VERSION 5.8 ;
BUSBITCHARS "[]" ;
DIVIDERCHAR "/" ;
UNITS
    DATABASE MICRONS 1000 ;
END UNITS

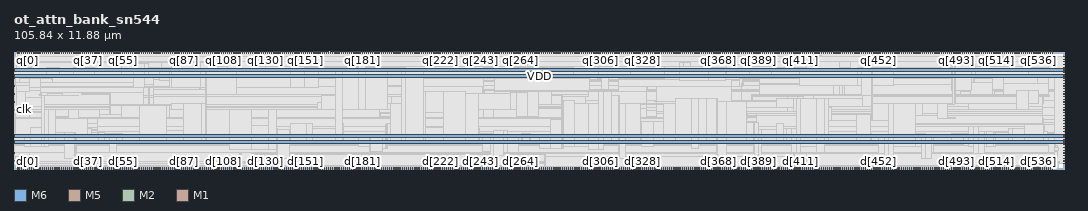
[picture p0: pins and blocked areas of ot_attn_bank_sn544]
MACRO ot_attn_bank_sn544
  FOREIGN ot_attn_bank_sn544 0 0 ;
  CLASS BLOCK ;
  SIZE 105.84 BY 11.88 ;
  PIN clk
    DIRECTION INPUT ;
    USE SIGNAL ;
    PORT
      LAYER M6 ;
        RECT  0 5.952 0.192 5.984 ;
    END
    PORT
      LAYER M6 ;
        RECT  0.144 5.952 0.613 5.984 ;
    END
  END clk
  PIN d[0]
    DIRECTION INPUT ;
    USE SIGNAL ;
    PORT
      LAYER M5 ;
        RECT  0.384 0 0.408 0.192 ;
    END
  END d[0]
  PIN d[100]
    DIRECTION INPUT ;
    USE SIGNAL ;
    PORT
      LAYER M5 ;
        RECT  19.584 0 19.608 0.192 ;
    END
  END d[100]
  PIN d[101]
    DIRECTION INPUT ;
    USE SIGNAL ;
    PORT
      LAYER M5 ;
        RECT  19.776 0 19.8 0.192 ;
    END
  END d[101]
  PIN d[102]
    DIRECTION INPUT ;
    USE SIGNAL ;
    PORT
      LAYER M5 ;
        RECT  19.968 0 19.992 0.192 ;
    END
  END d[102]
  PIN d[103]
    DIRECTION INPUT ;
    USE SIGNAL ;
    PORT
      LAYER M5 ;
        RECT  20.16 0 20.184 0.192 ;
    END
  END d[103]
  PIN d[104]
    DIRECTION INPUT ;
    USE SIGNAL ;
    PORT
      LAYER M5 ;
        RECT  20.352 0 20.376 0.192 ;
    END
  END d[104]
  PIN d[105]
    DIRECTION INPUT ;
    USE SIGNAL ;
    PORT
      LAYER M5 ;
        RECT  20.544 0 20.568 0.192 ;
    END
  END d[105]
  PIN d[106]
    DIRECTION INPUT ;
    USE SIGNAL ;
    PORT
      LAYER M5 ;
        RECT  20.736 0 20.76 0.192 ;
    END
  END d[106]
  PIN d[107]
    DIRECTION INPUT ;
    USE SIGNAL ;
    PORT
      LAYER M5 ;
        RECT  20.928 0 20.952 0.192 ;
    END
  END d[107]
  PIN d[108]
    DIRECTION INPUT ;
    USE SIGNAL ;
    PORT
      LAYER M5 ;
        RECT  21.12 0 21.144 0.192 ;
    END
  END d[108]
  PIN d[109]
    DIRECTION INPUT ;
    USE SIGNAL ;
    PORT
      LAYER M5 ;
        RECT  21.312 0 21.336 0.192 ;
    END
  END d[109]
  PIN d[10]
    DIRECTION INPUT ;
    USE SIGNAL ;
    PORT
      LAYER M5 ;
        RECT  2.304 0 2.328 0.192 ;
    END
  END d[10]
  PIN d[110]
    DIRECTION INPUT ;
    USE SIGNAL ;
    PORT
      LAYER M5 ;
        RECT  21.504 0 21.528 0.192 ;
    END
  END d[110]
  PIN d[111]
    DIRECTION INPUT ;
    USE SIGNAL ;
    PORT
      LAYER M5 ;
        RECT  21.696 0 21.72 0.192 ;
    END
  END d[111]
  PIN d[112]
    DIRECTION INPUT ;
    USE SIGNAL ;
    PORT
      LAYER M5 ;
        RECT  21.888 0 21.912 0.192 ;
    END
  END d[112]
  PIN d[113]
    DIRECTION INPUT ;
    USE SIGNAL ;
    PORT
      LAYER M5 ;
        RECT  22.08 0 22.104 0.192 ;
    END
  END d[113]
  PIN d[114]
    DIRECTION INPUT ;
    USE SIGNAL ;
    PORT
      LAYER M5 ;
        RECT  22.272 0 22.296 0.192 ;
    END
  END d[114]
  PIN d[115]
    DIRECTION INPUT ;
    USE SIGNAL ;
    PORT
      LAYER M5 ;
        RECT  22.464 0 22.488 0.192 ;
    END
  END d[115]
  PIN d[116]
    DIRECTION INPUT ;
    USE SIGNAL ;
    PORT
      LAYER M5 ;
        RECT  22.656 0 22.68 0.192 ;
    END
  END d[116]
  PIN d[117]
    DIRECTION INPUT ;
    USE SIGNAL ;
    PORT
      LAYER M5 ;
        RECT  22.848 0 22.872 0.192 ;
    END
  END d[117]
  PIN d[118]
    DIRECTION INPUT ;
    USE SIGNAL ;
    PORT
      LAYER M5 ;
        RECT  23.04 0 23.064 0.192 ;
    END
  END d[118]
  PIN d[119]
    DIRECTION INPUT ;
    USE SIGNAL ;
    PORT
      LAYER M5 ;
        RECT  23.232 0 23.256 0.192 ;
    END
  END d[119]
  PIN d[11]
    DIRECTION INPUT ;
    USE SIGNAL ;
    PORT
      LAYER M5 ;
        RECT  2.496 0 2.52 0.192 ;
    END
  END d[11]
  PIN d[120]
    DIRECTION INPUT ;
    USE SIGNAL ;
    PORT
      LAYER M5 ;
        RECT  23.424 0 23.448 0.192 ;
    END
  END d[120]
  PIN d[121]
    DIRECTION INPUT ;
    USE SIGNAL ;
    PORT
      LAYER M5 ;
        RECT  23.616 0 23.64 0.192 ;
    END
  END d[121]
  PIN d[122]
    DIRECTION INPUT ;
    USE SIGNAL ;
    PORT
      LAYER M5 ;
        RECT  23.808 0 23.832 0.192 ;
    END
  END d[122]
  PIN d[123]
    DIRECTION INPUT ;
    USE SIGNAL ;
    PORT
      LAYER M5 ;
        RECT  24 0 24.024 0.192 ;
    END
  END d[123]
  PIN d[124]
    DIRECTION INPUT ;
    USE SIGNAL ;
    PORT
      LAYER M5 ;
        RECT  24.192 0 24.216 0.192 ;
    END
  END d[124]
  PIN d[125]
    DIRECTION INPUT ;
    USE SIGNAL ;
    PORT
      LAYER M5 ;
        RECT  24.384 0 24.408 0.192 ;
    END
  END d[125]
  PIN d[126]
    DIRECTION INPUT ;
    USE SIGNAL ;
    PORT
      LAYER M5 ;
        RECT  24.576 0 24.6 0.192 ;
    END
  END d[126]
  PIN d[127]
    DIRECTION INPUT ;
    USE SIGNAL ;
    PORT
      LAYER M5 ;
        RECT  24.768 0 24.792 0.192 ;
    END
  END d[127]
  PIN d[128]
    DIRECTION INPUT ;
    USE SIGNAL ;
    PORT
      LAYER M5 ;
        RECT  24.96 0 24.984 0.192 ;
    END
  END d[128]
  PIN d[129]
    DIRECTION INPUT ;
    USE SIGNAL ;
    PORT
      LAYER M5 ;
        RECT  25.152 0 25.176 0.192 ;
    END
  END d[129]
  PIN d[12]
    DIRECTION INPUT ;
    USE SIGNAL ;
    PORT
      LAYER M5 ;
        RECT  2.688 0 2.712 0.192 ;
    END
  END d[12]
  PIN d[130]
    DIRECTION INPUT ;
    USE SIGNAL ;
    PORT
      LAYER M5 ;
        RECT  25.344 0 25.368 0.192 ;
    END
  END d[130]
  PIN d[131]
    DIRECTION INPUT ;
    USE SIGNAL ;
    PORT
      LAYER M5 ;
        RECT  25.536 0 25.56 0.192 ;
    END
  END d[131]
  PIN d[132]
    DIRECTION INPUT ;
    USE SIGNAL ;
    PORT
      LAYER M5 ;
        RECT  25.728 0 25.752 0.192 ;
    END
  END d[132]
  PIN d[133]
    DIRECTION INPUT ;
    USE SIGNAL ;
    PORT
      LAYER M5 ;
        RECT  25.92 0 25.944 0.192 ;
    END
  END d[133]
  PIN d[134]
    DIRECTION INPUT ;
    USE SIGNAL ;
    PORT
      LAYER M5 ;
        RECT  26.112 0 26.136 0.192 ;
    END
  END d[134]
  PIN d[135]
    DIRECTION INPUT ;
    USE SIGNAL ;
    PORT
      LAYER M5 ;
        RECT  26.304 0 26.328 0.192 ;
    END
  END d[135]
  PIN d[136]
    DIRECTION INPUT ;
    USE SIGNAL ;
    PORT
      LAYER M5 ;
        RECT  26.496 0 26.52 0.192 ;
    END
  END d[136]
  PIN d[137]
    DIRECTION INPUT ;
    USE SIGNAL ;
    PORT
      LAYER M5 ;
        RECT  26.688 0 26.712 0.192 ;
    END
  END d[137]
  PIN d[138]
    DIRECTION INPUT ;
    USE SIGNAL ;
    PORT
      LAYER M5 ;
        RECT  26.88 0 26.904 0.192 ;
    END
  END d[138]
  PIN d[139]
    DIRECTION INPUT ;
    USE SIGNAL ;
    PORT
      LAYER M5 ;
        RECT  27.072 0 27.096 0.192 ;
    END
  END d[139]
  PIN d[13]
    DIRECTION INPUT ;
    USE SIGNAL ;
    PORT
      LAYER M5 ;
        RECT  2.88 0 2.904 0.192 ;
    END
  END d[13]
  PIN d[140]
    DIRECTION INPUT ;
    USE SIGNAL ;
    PORT
      LAYER M5 ;
        RECT  27.264 0 27.288 0.192 ;
    END
  END d[140]
  PIN d[141]
    DIRECTION INPUT ;
    USE SIGNAL ;
    PORT
      LAYER M5 ;
        RECT  27.456 0 27.48 0.192 ;
    END
  END d[141]
  PIN d[142]
    DIRECTION INPUT ;
    USE SIGNAL ;
    PORT
      LAYER M5 ;
        RECT  27.648 0 27.672 0.192 ;
    END
  END d[142]
  PIN d[143]
    DIRECTION INPUT ;
    USE SIGNAL ;
    PORT
      LAYER M5 ;
        RECT  27.84 0 27.864 0.192 ;
    END
  END d[143]
  PIN d[144]
    DIRECTION INPUT ;
    USE SIGNAL ;
    PORT
      LAYER M5 ;
        RECT  28.032 0 28.056 0.192 ;
    END
  END d[144]
  PIN d[145]
    DIRECTION INPUT ;
    USE SIGNAL ;
    PORT
      LAYER M5 ;
        RECT  28.224 0 28.248 0.192 ;
    END
  END d[145]
  PIN d[146]
    DIRECTION INPUT ;
    USE SIGNAL ;
    PORT
      LAYER M5 ;
        RECT  28.416 0 28.44 0.192 ;
    END
  END d[146]
  PIN d[147]
    DIRECTION INPUT ;
    USE SIGNAL ;
    PORT
      LAYER M5 ;
        RECT  28.608 0 28.632 0.192 ;
    END
  END d[147]
  PIN d[148]
    DIRECTION INPUT ;
    USE SIGNAL ;
    PORT
      LAYER M5 ;
        RECT  28.8 0 28.824 0.192 ;
    END
  END d[148]
  PIN d[149]
    DIRECTION INPUT ;
    USE SIGNAL ;
    PORT
      LAYER M5 ;
        RECT  28.992 0 29.016 0.192 ;
    END
  END d[149]
  PIN d[14]
    DIRECTION INPUT ;
    USE SIGNAL ;
    PORT
      LAYER M5 ;
        RECT  3.072 0 3.096 0.192 ;
    END
  END d[14]
  PIN d[150]
    DIRECTION INPUT ;
    USE SIGNAL ;
    PORT
      LAYER M5 ;
        RECT  29.184 0 29.208 0.192 ;
    END
  END d[150]
  PIN d[151]
    DIRECTION INPUT ;
    USE SIGNAL ;
    PORT
      LAYER M5 ;
        RECT  29.376 0 29.4 0.192 ;
    END
  END d[151]
  PIN d[152]
    DIRECTION INPUT ;
    USE SIGNAL ;
    PORT
      LAYER M5 ;
        RECT  29.568 0 29.592 0.192 ;
    END
  END d[152]
  PIN d[153]
    DIRECTION INPUT ;
    USE SIGNAL ;
    PORT
      LAYER M5 ;
        RECT  29.76 0 29.784 0.192 ;
    END
  END d[153]
  PIN d[154]
    DIRECTION INPUT ;
    USE SIGNAL ;
    PORT
      LAYER M5 ;
        RECT  29.952 0 29.976 0.192 ;
    END
  END d[154]
  PIN d[155]
    DIRECTION INPUT ;
    USE SIGNAL ;
    PORT
      LAYER M5 ;
        RECT  30.144 0 30.168 0.192 ;
    END
  END d[155]
  PIN d[156]
    DIRECTION INPUT ;
    USE SIGNAL ;
    PORT
      LAYER M5 ;
        RECT  30.336 0 30.36 0.192 ;
    END
  END d[156]
  PIN d[157]
    DIRECTION INPUT ;
    USE SIGNAL ;
    PORT
      LAYER M5 ;
        RECT  30.528 0 30.552 0.192 ;
    END
  END d[157]
  PIN d[158]
    DIRECTION INPUT ;
    USE SIGNAL ;
    PORT
      LAYER M5 ;
        RECT  30.72 0 30.744 0.192 ;
    END
  END d[158]
  PIN d[159]
    DIRECTION INPUT ;
    USE SIGNAL ;
    PORT
      LAYER M5 ;
        RECT  30.912 0 30.936 0.192 ;
    END
  END d[159]
  PIN d[15]
    DIRECTION INPUT ;
    USE SIGNAL ;
    PORT
      LAYER M5 ;
        RECT  3.264 0 3.288 0.192 ;
    END
  END d[15]
  PIN d[160]
    DIRECTION INPUT ;
    USE SIGNAL ;
    PORT
      LAYER M5 ;
        RECT  31.104 0 31.128 0.192 ;
    END
  END d[160]
  PIN d[161]
    DIRECTION INPUT ;
    USE SIGNAL ;
    PORT
      LAYER M5 ;
        RECT  31.296 0 31.32 0.192 ;
    END
  END d[161]
  PIN d[162]
    DIRECTION INPUT ;
    USE SIGNAL ;
    PORT
      LAYER M5 ;
        RECT  31.488 0 31.512 0.192 ;
    END
  END d[162]
  PIN d[163]
    DIRECTION INPUT ;
    USE SIGNAL ;
    PORT
      LAYER M5 ;
        RECT  31.68 0 31.704 0.192 ;
    END
  END d[163]
  PIN d[164]
    DIRECTION INPUT ;
    USE SIGNAL ;
    PORT
      LAYER M5 ;
        RECT  31.872 0 31.896 0.192 ;
    END
  END d[164]
  PIN d[165]
    DIRECTION INPUT ;
    USE SIGNAL ;
    PORT
      LAYER M5 ;
        RECT  32.064 0 32.088 0.192 ;
    END
  END d[165]
  PIN d[166]
    DIRECTION INPUT ;
    USE SIGNAL ;
    PORT
      LAYER M5 ;
        RECT  32.256 0 32.28 0.192 ;
    END
  END d[166]
  PIN d[167]
    DIRECTION INPUT ;
    USE SIGNAL ;
    PORT
      LAYER M5 ;
        RECT  32.448 0 32.472 0.192 ;
    END
  END d[167]
  PIN d[168]
    DIRECTION INPUT ;
    USE SIGNAL ;
    PORT
      LAYER M5 ;
        RECT  32.64 0 32.664 0.192 ;
    END
  END d[168]
  PIN d[169]
    DIRECTION INPUT ;
    USE SIGNAL ;
    PORT
      LAYER M5 ;
        RECT  32.832 0 32.856 0.192 ;
    END
  END d[169]
  PIN d[16]
    DIRECTION INPUT ;
    USE SIGNAL ;
    PORT
      LAYER M5 ;
        RECT  3.456 0 3.48 0.192 ;
    END
  END d[16]
  PIN d[170]
    DIRECTION INPUT ;
    USE SIGNAL ;
    PORT
      LAYER M5 ;
        RECT  33.024 0 33.048 0.192 ;
    END
  END d[170]
  PIN d[171]
    DIRECTION INPUT ;
    USE SIGNAL ;
    PORT
      LAYER M5 ;
        RECT  33.216 0 33.24 0.192 ;
    END
  END d[171]
  PIN d[172]
    DIRECTION INPUT ;
    USE SIGNAL ;
    PORT
      LAYER M5 ;
        RECT  33.408 0 33.432 0.192 ;
    END
  END d[172]
  PIN d[173]
    DIRECTION INPUT ;
    USE SIGNAL ;
    PORT
      LAYER M5 ;
        RECT  33.6 0 33.624 0.192 ;
    END
  END d[173]
  PIN d[174]
    DIRECTION INPUT ;
    USE SIGNAL ;
    PORT
      LAYER M5 ;
        RECT  33.792 0 33.816 0.192 ;
    END
  END d[174]
  PIN d[175]
    DIRECTION INPUT ;
    USE SIGNAL ;
    PORT
      LAYER M5 ;
        RECT  33.984 0 34.008 0.192 ;
    END
  END d[175]
  PIN d[176]
    DIRECTION INPUT ;
    USE SIGNAL ;
    PORT
      LAYER M5 ;
        RECT  34.176 0 34.2 0.192 ;
    END
  END d[176]
  PIN d[177]
    DIRECTION INPUT ;
    USE SIGNAL ;
    PORT
      LAYER M5 ;
        RECT  34.368 0 34.392 0.192 ;
    END
  END d[177]
  PIN d[178]
    DIRECTION INPUT ;
    USE SIGNAL ;
    PORT
      LAYER M5 ;
        RECT  34.56 0 34.584 0.192 ;
    END
  END d[178]
  PIN d[179]
    DIRECTION INPUT ;
    USE SIGNAL ;
    PORT
      LAYER M5 ;
        RECT  34.752 0 34.776 0.192 ;
    END
  END d[179]
  PIN d[17]
    DIRECTION INPUT ;
    USE SIGNAL ;
    PORT
      LAYER M5 ;
        RECT  3.648 0 3.672 0.192 ;
    END
  END d[17]
  PIN d[180]
    DIRECTION INPUT ;
    USE SIGNAL ;
    PORT
      LAYER M5 ;
        RECT  34.944 0 34.968 0.192 ;
    END
  END d[180]
  PIN d[181]
    DIRECTION INPUT ;
    USE SIGNAL ;
    PORT
      LAYER M5 ;
        RECT  35.136 0 35.16 0.192 ;
    END
  END d[181]
  PIN d[182]
    DIRECTION INPUT ;
    USE SIGNAL ;
    PORT
      LAYER M5 ;
        RECT  35.328 0 35.352 0.192 ;
    END
  END d[182]
  PIN d[183]
    DIRECTION INPUT ;
    USE SIGNAL ;
    PORT
      LAYER M5 ;
        RECT  35.52 0 35.544 0.192 ;
    END
  END d[183]
  PIN d[184]
    DIRECTION INPUT ;
    USE SIGNAL ;
    PORT
      LAYER M5 ;
        RECT  35.712 0 35.736 0.192 ;
    END
  END d[184]
  PIN d[185]
    DIRECTION INPUT ;
    USE SIGNAL ;
    PORT
      LAYER M5 ;
        RECT  35.904 0 35.928 0.192 ;
    END
  END d[185]
  PIN d[186]
    DIRECTION INPUT ;
    USE SIGNAL ;
    PORT
      LAYER M5 ;
        RECT  36.096 0 36.12 0.192 ;
    END
  END d[186]
  PIN d[187]
    DIRECTION INPUT ;
    USE SIGNAL ;
    PORT
      LAYER M5 ;
        RECT  36.288 0 36.312 0.192 ;
    END
  END d[187]
  PIN d[188]
    DIRECTION INPUT ;
    USE SIGNAL ;
    PORT
      LAYER M5 ;
        RECT  36.48 0 36.504 0.192 ;
    END
  END d[188]
  PIN d[189]
    DIRECTION INPUT ;
    USE SIGNAL ;
    PORT
      LAYER M5 ;
        RECT  36.672 0 36.696 0.192 ;
    END
  END d[189]
  PIN d[18]
    DIRECTION INPUT ;
    USE SIGNAL ;
    PORT
      LAYER M5 ;
        RECT  3.84 0 3.864 0.192 ;
    END
  END d[18]
  PIN d[190]
    DIRECTION INPUT ;
    USE SIGNAL ;
    PORT
      LAYER M5 ;
        RECT  36.864 0 36.888 0.192 ;
    END
  END d[190]
  PIN d[191]
    DIRECTION INPUT ;
    USE SIGNAL ;
    PORT
      LAYER M5 ;
        RECT  37.056 0 37.08 0.192 ;
    END
  END d[191]
  PIN d[192]
    DIRECTION INPUT ;
    USE SIGNAL ;
    PORT
      LAYER M5 ;
        RECT  37.248 0 37.272 0.192 ;
    END
  END d[192]
  PIN d[193]
    DIRECTION INPUT ;
    USE SIGNAL ;
    PORT
      LAYER M5 ;
        RECT  37.44 0 37.464 0.192 ;
    END
  END d[193]
  PIN d[194]
    DIRECTION INPUT ;
    USE SIGNAL ;
    PORT
      LAYER M5 ;
        RECT  37.632 0 37.656 0.192 ;
    END
  END d[194]
  PIN d[195]
    DIRECTION INPUT ;
    USE SIGNAL ;
    PORT
      LAYER M5 ;
        RECT  37.824 0 37.848 0.192 ;
    END
  END d[195]
  PIN d[196]
    DIRECTION INPUT ;
    USE SIGNAL ;
    PORT
      LAYER M5 ;
        RECT  38.016 0 38.04 0.192 ;
    END
  END d[196]
  PIN d[197]
    DIRECTION INPUT ;
    USE SIGNAL ;
    PORT
      LAYER M5 ;
        RECT  38.208 0 38.232 0.192 ;
    END
  END d[197]
  PIN d[198]
    DIRECTION INPUT ;
    USE SIGNAL ;
    PORT
      LAYER M5 ;
        RECT  38.4 0 38.424 0.192 ;
    END
  END d[198]
  PIN d[199]
    DIRECTION INPUT ;
    USE SIGNAL ;
    PORT
      LAYER M5 ;
        RECT  38.592 0 38.616 0.192 ;
    END
  END d[199]
  PIN d[19]
    DIRECTION INPUT ;
    USE SIGNAL ;
    PORT
      LAYER M5 ;
        RECT  4.032 0 4.056 0.192 ;
    END
  END d[19]
  PIN d[1]
    DIRECTION INPUT ;
    USE SIGNAL ;
    PORT
      LAYER M5 ;
        RECT  0.576 0 0.6 0.192 ;
    END
  END d[1]
  PIN d[200]
    DIRECTION INPUT ;
    USE SIGNAL ;
    PORT
      LAYER M5 ;
        RECT  38.784 0 38.808 0.192 ;
    END
  END d[200]
  PIN d[201]
    DIRECTION INPUT ;
    USE SIGNAL ;
    PORT
      LAYER M5 ;
        RECT  38.976 0 39 0.192 ;
    END
  END d[201]
  PIN d[202]
    DIRECTION INPUT ;
    USE SIGNAL ;
    PORT
      LAYER M5 ;
        RECT  39.168 0 39.192 0.192 ;
    END
  END d[202]
  PIN d[203]
    DIRECTION INPUT ;
    USE SIGNAL ;
    PORT
      LAYER M5 ;
        RECT  39.36 0 39.384 0.192 ;
    END
  END d[203]
  PIN d[204]
    DIRECTION INPUT ;
    USE SIGNAL ;
    PORT
      LAYER M5 ;
        RECT  39.552 0 39.576 0.192 ;
    END
  END d[204]
  PIN d[205]
    DIRECTION INPUT ;
    USE SIGNAL ;
    PORT
      LAYER M5 ;
        RECT  39.744 0 39.768 0.192 ;
    END
  END d[205]
  PIN d[206]
    DIRECTION INPUT ;
    USE SIGNAL ;
    PORT
      LAYER M5 ;
        RECT  39.936 0 39.96 0.192 ;
    END
  END d[206]
  PIN d[207]
    DIRECTION INPUT ;
    USE SIGNAL ;
    PORT
      LAYER M5 ;
        RECT  40.128 0 40.152 0.192 ;
    END
  END d[207]
  PIN d[208]
    DIRECTION INPUT ;
    USE SIGNAL ;
    PORT
      LAYER M5 ;
        RECT  40.32 0 40.344 0.192 ;
    END
  END d[208]
  PIN d[209]
    DIRECTION INPUT ;
    USE SIGNAL ;
    PORT
      LAYER M5 ;
        RECT  40.512 0 40.536 0.192 ;
    END
  END d[209]
  PIN d[20]
    DIRECTION INPUT ;
    USE SIGNAL ;
    PORT
      LAYER M5 ;
        RECT  4.224 0 4.248 0.192 ;
    END
  END d[20]
  PIN d[210]
    DIRECTION INPUT ;
    USE SIGNAL ;
    PORT
      LAYER M5 ;
        RECT  40.704 0 40.728 0.192 ;
    END
  END d[210]
  PIN d[211]
    DIRECTION INPUT ;
    USE SIGNAL ;
    PORT
      LAYER M5 ;
        RECT  40.896 0 40.92 0.192 ;
    END
  END d[211]
  PIN d[212]
    DIRECTION INPUT ;
    USE SIGNAL ;
    PORT
      LAYER M5 ;
        RECT  41.088 0 41.112 0.192 ;
    END
  END d[212]
  PIN d[213]
    DIRECTION INPUT ;
    USE SIGNAL ;
    PORT
      LAYER M5 ;
        RECT  41.28 0 41.304 0.192 ;
    END
  END d[213]
  PIN d[214]
    DIRECTION INPUT ;
    USE SIGNAL ;
    PORT
      LAYER M5 ;
        RECT  41.472 0 41.496 0.192 ;
    END
  END d[214]
  PIN d[215]
    DIRECTION INPUT ;
    USE SIGNAL ;
    PORT
      LAYER M5 ;
        RECT  41.664 0 41.688 0.192 ;
    END
  END d[215]
  PIN d[216]
    DIRECTION INPUT ;
    USE SIGNAL ;
    PORT
      LAYER M5 ;
        RECT  41.856 0 41.88 0.192 ;
    END
  END d[216]
  PIN d[217]
    DIRECTION INPUT ;
    USE SIGNAL ;
    PORT
      LAYER M5 ;
        RECT  42.048 0 42.072 0.192 ;
    END
  END d[217]
  PIN d[218]
    DIRECTION INPUT ;
    USE SIGNAL ;
    PORT
      LAYER M5 ;
        RECT  42.24 0 42.264 0.192 ;
    END
  END d[218]
  PIN d[219]
    DIRECTION INPUT ;
    USE SIGNAL ;
    PORT
      LAYER M5 ;
        RECT  42.432 0 42.456 0.192 ;
    END
  END d[219]
  PIN d[21]
    DIRECTION INPUT ;
    USE SIGNAL ;
    PORT
      LAYER M5 ;
        RECT  4.416 0 4.44 0.192 ;
    END
  END d[21]
  PIN d[220]
    DIRECTION INPUT ;
    USE SIGNAL ;
    PORT
      LAYER M5 ;
        RECT  42.624 0 42.648 0.192 ;
    END
  END d[220]
  PIN d[221]
    DIRECTION INPUT ;
    USE SIGNAL ;
    PORT
      LAYER M5 ;
        RECT  42.816 0 42.84 0.192 ;
    END
  END d[221]
  PIN d[222]
    DIRECTION INPUT ;
    USE SIGNAL ;
    PORT
      LAYER M5 ;
        RECT  43.008 0 43.032 0.192 ;
    END
  END d[222]
  PIN d[223]
    DIRECTION INPUT ;
    USE SIGNAL ;
    PORT
      LAYER M5 ;
        RECT  43.2 0 43.224 0.192 ;
    END
  END d[223]
  PIN d[224]
    DIRECTION INPUT ;
    USE SIGNAL ;
    PORT
      LAYER M5 ;
        RECT  43.392 0 43.416 0.192 ;
    END
  END d[224]
  PIN d[225]
    DIRECTION INPUT ;
    USE SIGNAL ;
    PORT
      LAYER M5 ;
        RECT  43.584 0 43.608 0.192 ;
    END
  END d[225]
  PIN d[226]
    DIRECTION INPUT ;
    USE SIGNAL ;
    PORT
      LAYER M5 ;
        RECT  43.776 0 43.8 0.192 ;
    END
  END d[226]
  PIN d[227]
    DIRECTION INPUT ;
    USE SIGNAL ;
    PORT
      LAYER M5 ;
        RECT  43.968 0 43.992 0.192 ;
    END
  END d[227]
  PIN d[228]
    DIRECTION INPUT ;
    USE SIGNAL ;
    PORT
      LAYER M5 ;
        RECT  44.16 0 44.184 0.192 ;
    END
  END d[228]
  PIN d[229]
    DIRECTION INPUT ;
    USE SIGNAL ;
    PORT
      LAYER M5 ;
        RECT  44.352 0 44.376 0.192 ;
    END
  END d[229]
  PIN d[22]
    DIRECTION INPUT ;
    USE SIGNAL ;
    PORT
      LAYER M5 ;
        RECT  4.608 0 4.632 0.192 ;
    END
  END d[22]
  PIN d[230]
    DIRECTION INPUT ;
    USE SIGNAL ;
    PORT
      LAYER M5 ;
        RECT  44.544 0 44.568 0.192 ;
    END
  END d[230]
  PIN d[231]
    DIRECTION INPUT ;
    USE SIGNAL ;
    PORT
      LAYER M5 ;
        RECT  44.736 0 44.76 0.192 ;
    END
  END d[231]
  PIN d[232]
    DIRECTION INPUT ;
    USE SIGNAL ;
    PORT
      LAYER M5 ;
        RECT  44.928 0 44.952 0.192 ;
    END
  END d[232]
  PIN d[233]
    DIRECTION INPUT ;
    USE SIGNAL ;
    PORT
      LAYER M5 ;
        RECT  45.12 0 45.144 0.192 ;
    END
  END d[233]
  PIN d[234]
    DIRECTION INPUT ;
    USE SIGNAL ;
    PORT
      LAYER M5 ;
        RECT  45.312 0 45.336 0.192 ;
    END
  END d[234]
  PIN d[235]
    DIRECTION INPUT ;
    USE SIGNAL ;
    PORT
      LAYER M5 ;
        RECT  45.504 0 45.528 0.192 ;
    END
  END d[235]
  PIN d[236]
    DIRECTION INPUT ;
    USE SIGNAL ;
    PORT
      LAYER M5 ;
        RECT  45.696 0 45.72 0.192 ;
    END
  END d[236]
  PIN d[237]
    DIRECTION INPUT ;
    USE SIGNAL ;
    PORT
      LAYER M5 ;
        RECT  45.888 0 45.912 0.192 ;
    END
  END d[237]
  PIN d[238]
    DIRECTION INPUT ;
    USE SIGNAL ;
    PORT
      LAYER M5 ;
        RECT  46.08 0 46.104 0.192 ;
    END
  END d[238]
  PIN d[239]
    DIRECTION INPUT ;
    USE SIGNAL ;
    PORT
      LAYER M5 ;
        RECT  46.272 0 46.296 0.192 ;
    END
  END d[239]
  PIN d[23]
    DIRECTION INPUT ;
    USE SIGNAL ;
    PORT
      LAYER M5 ;
        RECT  4.8 0 4.824 0.192 ;
    END
  END d[23]
  PIN d[240]
    DIRECTION INPUT ;
    USE SIGNAL ;
    PORT
      LAYER M5 ;
        RECT  46.464 0 46.488 0.192 ;
    END
  END d[240]
  PIN d[241]
    DIRECTION INPUT ;
    USE SIGNAL ;
    PORT
      LAYER M5 ;
        RECT  46.656 0 46.68 0.192 ;
    END
  END d[241]
  PIN d[242]
    DIRECTION INPUT ;
    USE SIGNAL ;
    PORT
      LAYER M5 ;
        RECT  46.848 0 46.872 0.192 ;
    END
  END d[242]
  PIN d[243]
    DIRECTION INPUT ;
    USE SIGNAL ;
    PORT
      LAYER M5 ;
        RECT  47.04 0 47.064 0.192 ;
    END
  END d[243]
  PIN d[244]
    DIRECTION INPUT ;
    USE SIGNAL ;
    PORT
      LAYER M5 ;
        RECT  47.232 0 47.256 0.192 ;
    END
  END d[244]
  PIN d[245]
    DIRECTION INPUT ;
    USE SIGNAL ;
    PORT
      LAYER M5 ;
        RECT  47.424 0 47.448 0.192 ;
    END
  END d[245]
  PIN d[246]
    DIRECTION INPUT ;
    USE SIGNAL ;
    PORT
      LAYER M5 ;
        RECT  47.616 0 47.64 0.192 ;
    END
  END d[246]
  PIN d[247]
    DIRECTION INPUT ;
    USE SIGNAL ;
    PORT
      LAYER M5 ;
        RECT  47.808 0 47.832 0.192 ;
    END
  END d[247]
  PIN d[248]
    DIRECTION INPUT ;
    USE SIGNAL ;
    PORT
      LAYER M5 ;
        RECT  48 0 48.024 0.192 ;
    END
  END d[248]
  PIN d[249]
    DIRECTION INPUT ;
    USE SIGNAL ;
    PORT
      LAYER M5 ;
        RECT  48.192 0 48.216 0.192 ;
    END
  END d[249]
  PIN d[24]
    DIRECTION INPUT ;
    USE SIGNAL ;
    PORT
      LAYER M5 ;
        RECT  4.992 0 5.016 0.192 ;
    END
  END d[24]
  PIN d[250]
    DIRECTION INPUT ;
    USE SIGNAL ;
    PORT
      LAYER M5 ;
        RECT  48.384 0 48.408 0.192 ;
    END
  END d[250]
  PIN d[251]
    DIRECTION INPUT ;
    USE SIGNAL ;
    PORT
      LAYER M5 ;
        RECT  48.576 0 48.6 0.192 ;
    END
  END d[251]
  PIN d[252]
    DIRECTION INPUT ;
    USE SIGNAL ;
    PORT
      LAYER M5 ;
        RECT  48.768 0 48.792 0.192 ;
    END
  END d[252]
  PIN d[253]
    DIRECTION INPUT ;
    USE SIGNAL ;
    PORT
      LAYER M5 ;
        RECT  48.96 0 48.984 0.192 ;
    END
  END d[253]
  PIN d[254]
    DIRECTION INPUT ;
    USE SIGNAL ;
    PORT
      LAYER M5 ;
        RECT  49.152 0 49.176 0.192 ;
    END
  END d[254]
  PIN d[255]
    DIRECTION INPUT ;
    USE SIGNAL ;
    PORT
      LAYER M5 ;
        RECT  49.344 0 49.368 0.192 ;
    END
  END d[255]
  PIN d[256]
    DIRECTION INPUT ;
    USE SIGNAL ;
    PORT
      LAYER M5 ;
        RECT  49.536 0 49.56 0.192 ;
    END
  END d[256]
  PIN d[257]
    DIRECTION INPUT ;
    USE SIGNAL ;
    PORT
      LAYER M5 ;
        RECT  49.728 0 49.752 0.192 ;
    END
  END d[257]
  PIN d[258]
    DIRECTION INPUT ;
    USE SIGNAL ;
    PORT
      LAYER M5 ;
        RECT  49.92 0 49.944 0.192 ;
    END
  END d[258]
  PIN d[259]
    DIRECTION INPUT ;
    USE SIGNAL ;
    PORT
      LAYER M5 ;
        RECT  50.112 0 50.136 0.192 ;
    END
  END d[259]
  PIN d[25]
    DIRECTION INPUT ;
    USE SIGNAL ;
    PORT
      LAYER M5 ;
        RECT  5.184 0 5.208 0.192 ;
    END
  END d[25]
  PIN d[260]
    DIRECTION INPUT ;
    USE SIGNAL ;
    PORT
      LAYER M5 ;
        RECT  50.304 0 50.328 0.192 ;
    END
  END d[260]
  PIN d[261]
    DIRECTION INPUT ;
    USE SIGNAL ;
    PORT
      LAYER M5 ;
        RECT  50.496 0 50.52 0.192 ;
    END
  END d[261]
  PIN d[262]
    DIRECTION INPUT ;
    USE SIGNAL ;
    PORT
      LAYER M5 ;
        RECT  50.688 0 50.712 0.192 ;
    END
  END d[262]
  PIN d[263]
    DIRECTION INPUT ;
    USE SIGNAL ;
    PORT
      LAYER M5 ;
        RECT  50.88 0 50.904 0.192 ;
    END
  END d[263]
  PIN d[264]
    DIRECTION INPUT ;
    USE SIGNAL ;
    PORT
      LAYER M5 ;
        RECT  51.072 0 51.096 0.192 ;
    END
  END d[264]
  PIN d[265]
    DIRECTION INPUT ;
    USE SIGNAL ;
    PORT
      LAYER M5 ;
        RECT  51.264 0 51.288 0.192 ;
    END
  END d[265]
  PIN d[266]
    DIRECTION INPUT ;
    USE SIGNAL ;
    PORT
      LAYER M5 ;
        RECT  51.456 0 51.48 0.192 ;
    END
  END d[266]
  PIN d[267]
    DIRECTION INPUT ;
    USE SIGNAL ;
    PORT
      LAYER M5 ;
        RECT  51.648 0 51.672 0.192 ;
    END
  END d[267]
  PIN d[268]
    DIRECTION INPUT ;
    USE SIGNAL ;
    PORT
      LAYER M5 ;
        RECT  51.84 0 51.864 0.192 ;
    END
  END d[268]
  PIN d[269]
    DIRECTION INPUT ;
    USE SIGNAL ;
    PORT
      LAYER M5 ;
        RECT  52.032 0 52.056 0.192 ;
    END
  END d[269]
  PIN d[26]
    DIRECTION INPUT ;
    USE SIGNAL ;
    PORT
      LAYER M5 ;
        RECT  5.376 0 5.4 0.192 ;
    END
  END d[26]
  PIN d[270]
    DIRECTION INPUT ;
    USE SIGNAL ;
    PORT
      LAYER M5 ;
        RECT  52.224 0 52.248 0.192 ;
    END
  END d[270]
  PIN d[271]
    DIRECTION INPUT ;
    USE SIGNAL ;
    PORT
      LAYER M5 ;
        RECT  52.416 0 52.44 0.192 ;
    END
  END d[271]
  PIN d[272]
    DIRECTION INPUT ;
    USE SIGNAL ;
    PORT
      LAYER M5 ;
        RECT  52.608 0 52.632 0.192 ;
    END
  END d[272]
  PIN d[273]
    DIRECTION INPUT ;
    USE SIGNAL ;
    PORT
      LAYER M5 ;
        RECT  52.8 0 52.824 0.192 ;
    END
  END d[273]
  PIN d[274]
    DIRECTION INPUT ;
    USE SIGNAL ;
    PORT
      LAYER M5 ;
        RECT  52.992 0 53.016 0.192 ;
    END
  END d[274]
  PIN d[275]
    DIRECTION INPUT ;
    USE SIGNAL ;
    PORT
      LAYER M5 ;
        RECT  53.184 0 53.208 0.192 ;
    END
  END d[275]
  PIN d[276]
    DIRECTION INPUT ;
    USE SIGNAL ;
    PORT
      LAYER M5 ;
        RECT  53.376 0 53.4 0.192 ;
    END
  END d[276]
  PIN d[277]
    DIRECTION INPUT ;
    USE SIGNAL ;
    PORT
      LAYER M5 ;
        RECT  53.568 0 53.592 0.192 ;
    END
  END d[277]
  PIN d[278]
    DIRECTION INPUT ;
    USE SIGNAL ;
    PORT
      LAYER M5 ;
        RECT  53.76 0 53.784 0.192 ;
    END
  END d[278]
  PIN d[279]
    DIRECTION INPUT ;
    USE SIGNAL ;
    PORT
      LAYER M5 ;
        RECT  53.952 0 53.976 0.192 ;
    END
  END d[279]
  PIN d[27]
    DIRECTION INPUT ;
    USE SIGNAL ;
    PORT
      LAYER M5 ;
        RECT  5.568 0 5.592 0.192 ;
    END
  END d[27]
  PIN d[280]
    DIRECTION INPUT ;
    USE SIGNAL ;
    PORT
      LAYER M5 ;
        RECT  54.144 0 54.168 0.192 ;
    END
  END d[280]
  PIN d[281]
    DIRECTION INPUT ;
    USE SIGNAL ;
    PORT
      LAYER M5 ;
        RECT  54.336 0 54.36 0.192 ;
    END
  END d[281]
  PIN d[282]
    DIRECTION INPUT ;
    USE SIGNAL ;
    PORT
      LAYER M5 ;
        RECT  54.528 0 54.552 0.192 ;
    END
  END d[282]
  PIN d[283]
    DIRECTION INPUT ;
    USE SIGNAL ;
    PORT
      LAYER M5 ;
        RECT  54.72 0 54.744 0.192 ;
    END
  END d[283]
  PIN d[284]
    DIRECTION INPUT ;
    USE SIGNAL ;
    PORT
      LAYER M5 ;
        RECT  54.912 0 54.936 0.192 ;
    END
  END d[284]
  PIN d[285]
    DIRECTION INPUT ;
    USE SIGNAL ;
    PORT
      LAYER M5 ;
        RECT  55.104 0 55.128 0.192 ;
    END
  END d[285]
  PIN d[286]
    DIRECTION INPUT ;
    USE SIGNAL ;
    PORT
      LAYER M5 ;
        RECT  55.296 0 55.32 0.192 ;
    END
  END d[286]
  PIN d[287]
    DIRECTION INPUT ;
    USE SIGNAL ;
    PORT
      LAYER M5 ;
        RECT  55.488 0 55.512 0.192 ;
    END
  END d[287]
  PIN d[288]
    DIRECTION INPUT ;
    USE SIGNAL ;
    PORT
      LAYER M5 ;
        RECT  55.68 0 55.704 0.192 ;
    END
  END d[288]
  PIN d[289]
    DIRECTION INPUT ;
    USE SIGNAL ;
    PORT
      LAYER M5 ;
        RECT  55.872 0 55.896 0.192 ;
    END
  END d[289]
  PIN d[28]
    DIRECTION INPUT ;
    USE SIGNAL ;
    PORT
      LAYER M5 ;
        RECT  5.76 0 5.784 0.192 ;
    END
  END d[28]
  PIN d[290]
    DIRECTION INPUT ;
    USE SIGNAL ;
    PORT
      LAYER M5 ;
        RECT  56.064 0 56.088 0.192 ;
    END
  END d[290]
  PIN d[291]
    DIRECTION INPUT ;
    USE SIGNAL ;
    PORT
      LAYER M5 ;
        RECT  56.256 0 56.28 0.192 ;
    END
  END d[291]
  PIN d[292]
    DIRECTION INPUT ;
    USE SIGNAL ;
    PORT
      LAYER M5 ;
        RECT  56.448 0 56.472 0.192 ;
    END
  END d[292]
  PIN d[293]
    DIRECTION INPUT ;
    USE SIGNAL ;
    PORT
      LAYER M5 ;
        RECT  56.64 0 56.664 0.192 ;
    END
  END d[293]
  PIN d[294]
    DIRECTION INPUT ;
    USE SIGNAL ;
    PORT
      LAYER M5 ;
        RECT  56.832 0 56.856 0.192 ;
    END
  END d[294]
  PIN d[295]
    DIRECTION INPUT ;
    USE SIGNAL ;
    PORT
      LAYER M5 ;
        RECT  57.024 0 57.048 0.192 ;
    END
  END d[295]
  PIN d[296]
    DIRECTION INPUT ;
    USE SIGNAL ;
    PORT
      LAYER M5 ;
        RECT  57.216 0 57.24 0.192 ;
    END
  END d[296]
  PIN d[297]
    DIRECTION INPUT ;
    USE SIGNAL ;
    PORT
      LAYER M5 ;
        RECT  57.408 0 57.432 0.192 ;
    END
  END d[297]
  PIN d[298]
    DIRECTION INPUT ;
    USE SIGNAL ;
    PORT
      LAYER M5 ;
        RECT  57.6 0 57.624 0.192 ;
    END
  END d[298]
  PIN d[299]
    DIRECTION INPUT ;
    USE SIGNAL ;
    PORT
      LAYER M5 ;
        RECT  57.792 0 57.816 0.192 ;
    END
  END d[299]
  PIN d[29]
    DIRECTION INPUT ;
    USE SIGNAL ;
    PORT
      LAYER M5 ;
        RECT  5.952 0 5.976 0.192 ;
    END
  END d[29]
  PIN d[2]
    DIRECTION INPUT ;
    USE SIGNAL ;
    PORT
      LAYER M5 ;
        RECT  0.768 0 0.792 0.192 ;
    END
  END d[2]
  PIN d[300]
    DIRECTION INPUT ;
    USE SIGNAL ;
    PORT
      LAYER M5 ;
        RECT  57.984 0 58.008 0.192 ;
    END
  END d[300]
  PIN d[301]
    DIRECTION INPUT ;
    USE SIGNAL ;
    PORT
      LAYER M5 ;
        RECT  58.176 0 58.2 0.192 ;
    END
  END d[301]
  PIN d[302]
    DIRECTION INPUT ;
    USE SIGNAL ;
    PORT
      LAYER M5 ;
        RECT  58.368 0 58.392 0.192 ;
    END
  END d[302]
  PIN d[303]
    DIRECTION INPUT ;
    USE SIGNAL ;
    PORT
      LAYER M5 ;
        RECT  58.56 0 58.584 0.192 ;
    END
  END d[303]
  PIN d[304]
    DIRECTION INPUT ;
    USE SIGNAL ;
    PORT
      LAYER M5 ;
        RECT  58.752 0 58.776 0.192 ;
    END
  END d[304]
  PIN d[305]
    DIRECTION INPUT ;
    USE SIGNAL ;
    PORT
      LAYER M5 ;
        RECT  58.944 0 58.968 0.192 ;
    END
  END d[305]
  PIN d[306]
    DIRECTION INPUT ;
    USE SIGNAL ;
    PORT
      LAYER M5 ;
        RECT  59.136 0 59.16 0.192 ;
    END
  END d[306]
  PIN d[307]
    DIRECTION INPUT ;
    USE SIGNAL ;
    PORT
      LAYER M5 ;
        RECT  59.328 0 59.352 0.192 ;
    END
  END d[307]
  PIN d[308]
    DIRECTION INPUT ;
    USE SIGNAL ;
    PORT
      LAYER M5 ;
        RECT  59.52 0 59.544 0.192 ;
    END
  END d[308]
  PIN d[309]
    DIRECTION INPUT ;
    USE SIGNAL ;
    PORT
      LAYER M5 ;
        RECT  59.712 0 59.736 0.192 ;
    END
  END d[309]
  PIN d[30]
    DIRECTION INPUT ;
    USE SIGNAL ;
    PORT
      LAYER M5 ;
        RECT  6.144 0 6.168 0.192 ;
    END
  END d[30]
  PIN d[310]
    DIRECTION INPUT ;
    USE SIGNAL ;
    PORT
      LAYER M5 ;
        RECT  59.904 0 59.928 0.192 ;
    END
  END d[310]
  PIN d[311]
    DIRECTION INPUT ;
    USE SIGNAL ;
    PORT
      LAYER M5 ;
        RECT  60.096 0 60.12 0.192 ;
    END
  END d[311]
  PIN d[312]
    DIRECTION INPUT ;
    USE SIGNAL ;
    PORT
      LAYER M5 ;
        RECT  60.288 0 60.312 0.192 ;
    END
  END d[312]
  PIN d[313]
    DIRECTION INPUT ;
    USE SIGNAL ;
    PORT
      LAYER M5 ;
        RECT  60.48 0 60.504 0.192 ;
    END
  END d[313]
  PIN d[314]
    DIRECTION INPUT ;
    USE SIGNAL ;
    PORT
      LAYER M5 ;
        RECT  60.672 0 60.696 0.192 ;
    END
  END d[314]
  PIN d[315]
    DIRECTION INPUT ;
    USE SIGNAL ;
    PORT
      LAYER M5 ;
        RECT  60.864 0 60.888 0.192 ;
    END
  END d[315]
  PIN d[316]
    DIRECTION INPUT ;
    USE SIGNAL ;
    PORT
      LAYER M5 ;
        RECT  61.056 0 61.08 0.192 ;
    END
  END d[316]
  PIN d[317]
    DIRECTION INPUT ;
    USE SIGNAL ;
    PORT
      LAYER M5 ;
        RECT  61.248 0 61.272 0.192 ;
    END
  END d[317]
  PIN d[318]
    DIRECTION INPUT ;
    USE SIGNAL ;
    PORT
      LAYER M5 ;
        RECT  61.44 0 61.464 0.192 ;
    END
  END d[318]
  PIN d[319]
    DIRECTION INPUT ;
    USE SIGNAL ;
    PORT
      LAYER M5 ;
        RECT  61.632 0 61.656 0.192 ;
    END
  END d[319]
  PIN d[31]
    DIRECTION INPUT ;
    USE SIGNAL ;
    PORT
      LAYER M5 ;
        RECT  6.336 0 6.36 0.192 ;
    END
  END d[31]
  PIN d[320]
    DIRECTION INPUT ;
    USE SIGNAL ;
    PORT
      LAYER M5 ;
        RECT  61.824 0 61.848 0.192 ;
    END
  END d[320]
  PIN d[321]
    DIRECTION INPUT ;
    USE SIGNAL ;
    PORT
      LAYER M5 ;
        RECT  62.016 0 62.04 0.192 ;
    END
  END d[321]
  PIN d[322]
    DIRECTION INPUT ;
    USE SIGNAL ;
    PORT
      LAYER M5 ;
        RECT  62.208 0 62.232 0.192 ;
    END
  END d[322]
  PIN d[323]
    DIRECTION INPUT ;
    USE SIGNAL ;
    PORT
      LAYER M5 ;
        RECT  62.4 0 62.424 0.192 ;
    END
  END d[323]
  PIN d[324]
    DIRECTION INPUT ;
    USE SIGNAL ;
    PORT
      LAYER M5 ;
        RECT  62.592 0 62.616 0.192 ;
    END
  END d[324]
  PIN d[325]
    DIRECTION INPUT ;
    USE SIGNAL ;
    PORT
      LAYER M5 ;
        RECT  62.784 0 62.808 0.192 ;
    END
  END d[325]
  PIN d[326]
    DIRECTION INPUT ;
    USE SIGNAL ;
    PORT
      LAYER M5 ;
        RECT  62.976 0 63 0.192 ;
    END
  END d[326]
  PIN d[327]
    DIRECTION INPUT ;
    USE SIGNAL ;
    PORT
      LAYER M5 ;
        RECT  63.168 0 63.192 0.192 ;
    END
  END d[327]
  PIN d[328]
    DIRECTION INPUT ;
    USE SIGNAL ;
    PORT
      LAYER M5 ;
        RECT  63.36 0 63.384 0.192 ;
    END
  END d[328]
  PIN d[329]
    DIRECTION INPUT ;
    USE SIGNAL ;
    PORT
      LAYER M5 ;
        RECT  63.552 0 63.576 0.192 ;
    END
  END d[329]
  PIN d[32]
    DIRECTION INPUT ;
    USE SIGNAL ;
    PORT
      LAYER M5 ;
        RECT  6.528 0 6.552 0.192 ;
    END
  END d[32]
  PIN d[330]
    DIRECTION INPUT ;
    USE SIGNAL ;
    PORT
      LAYER M5 ;
        RECT  63.744 0 63.768 0.192 ;
    END
  END d[330]
  PIN d[331]
    DIRECTION INPUT ;
    USE SIGNAL ;
    PORT
      LAYER M5 ;
        RECT  63.936 0 63.96 0.192 ;
    END
  END d[331]
  PIN d[332]
    DIRECTION INPUT ;
    USE SIGNAL ;
    PORT
      LAYER M5 ;
        RECT  64.128 0 64.152 0.192 ;
    END
  END d[332]
  PIN d[333]
    DIRECTION INPUT ;
    USE SIGNAL ;
    PORT
      LAYER M5 ;
        RECT  64.32 0 64.344 0.192 ;
    END
  END d[333]
  PIN d[334]
    DIRECTION INPUT ;
    USE SIGNAL ;
    PORT
      LAYER M5 ;
        RECT  64.512 0 64.536 0.192 ;
    END
  END d[334]
  PIN d[335]
    DIRECTION INPUT ;
    USE SIGNAL ;
    PORT
      LAYER M5 ;
        RECT  64.704 0 64.728 0.192 ;
    END
  END d[335]
  PIN d[336]
    DIRECTION INPUT ;
    USE SIGNAL ;
    PORT
      LAYER M5 ;
        RECT  64.896 0 64.92 0.192 ;
    END
  END d[336]
  PIN d[337]
    DIRECTION INPUT ;
    USE SIGNAL ;
    PORT
      LAYER M5 ;
        RECT  65.088 0 65.112 0.192 ;
    END
  END d[337]
  PIN d[338]
    DIRECTION INPUT ;
    USE SIGNAL ;
    PORT
      LAYER M5 ;
        RECT  65.28 0 65.304 0.192 ;
    END
  END d[338]
  PIN d[339]
    DIRECTION INPUT ;
    USE SIGNAL ;
    PORT
      LAYER M5 ;
        RECT  65.472 0 65.496 0.192 ;
    END
  END d[339]
  PIN d[33]
    DIRECTION INPUT ;
    USE SIGNAL ;
    PORT
      LAYER M5 ;
        RECT  6.72 0 6.744 0.192 ;
    END
  END d[33]
  PIN d[340]
    DIRECTION INPUT ;
    USE SIGNAL ;
    PORT
      LAYER M5 ;
        RECT  65.664 0 65.688 0.192 ;
    END
  END d[340]
  PIN d[341]
    DIRECTION INPUT ;
    USE SIGNAL ;
    PORT
      LAYER M5 ;
        RECT  65.856 0 65.88 0.192 ;
    END
  END d[341]
  PIN d[342]
    DIRECTION INPUT ;
    USE SIGNAL ;
    PORT
      LAYER M5 ;
        RECT  66.048 0 66.072 0.192 ;
    END
  END d[342]
  PIN d[343]
    DIRECTION INPUT ;
    USE SIGNAL ;
    PORT
      LAYER M5 ;
        RECT  66.24 0 66.264 0.192 ;
    END
  END d[343]
  PIN d[344]
    DIRECTION INPUT ;
    USE SIGNAL ;
    PORT
      LAYER M5 ;
        RECT  66.432 0 66.456 0.192 ;
    END
  END d[344]
  PIN d[345]
    DIRECTION INPUT ;
    USE SIGNAL ;
    PORT
      LAYER M5 ;
        RECT  66.624 0 66.648 0.192 ;
    END
  END d[345]
  PIN d[346]
    DIRECTION INPUT ;
    USE SIGNAL ;
    PORT
      LAYER M5 ;
        RECT  66.816 0 66.84 0.192 ;
    END
  END d[346]
  PIN d[347]
    DIRECTION INPUT ;
    USE SIGNAL ;
    PORT
      LAYER M5 ;
        RECT  67.008 0 67.032 0.192 ;
    END
  END d[347]
  PIN d[348]
    DIRECTION INPUT ;
    USE SIGNAL ;
    PORT
      LAYER M5 ;
        RECT  67.2 0 67.224 0.192 ;
    END
  END d[348]
  PIN d[349]
    DIRECTION INPUT ;
    USE SIGNAL ;
    PORT
      LAYER M5 ;
        RECT  67.392 0 67.416 0.192 ;
    END
  END d[349]
  PIN d[34]
    DIRECTION INPUT ;
    USE SIGNAL ;
    PORT
      LAYER M5 ;
        RECT  6.912 0 6.936 0.192 ;
    END
  END d[34]
  PIN d[350]
    DIRECTION INPUT ;
    USE SIGNAL ;
    PORT
      LAYER M5 ;
        RECT  67.584 0 67.608 0.192 ;
    END
  END d[350]
  PIN d[351]
    DIRECTION INPUT ;
    USE SIGNAL ;
    PORT
      LAYER M5 ;
        RECT  67.776 0 67.8 0.192 ;
    END
  END d[351]
  PIN d[352]
    DIRECTION INPUT ;
    USE SIGNAL ;
    PORT
      LAYER M5 ;
        RECT  67.968 0 67.992 0.192 ;
    END
  END d[352]
  PIN d[353]
    DIRECTION INPUT ;
    USE SIGNAL ;
    PORT
      LAYER M5 ;
        RECT  68.16 0 68.184 0.192 ;
    END
  END d[353]
  PIN d[354]
    DIRECTION INPUT ;
    USE SIGNAL ;
    PORT
      LAYER M5 ;
        RECT  68.352 0 68.376 0.192 ;
    END
  END d[354]
  PIN d[355]
    DIRECTION INPUT ;
    USE SIGNAL ;
    PORT
      LAYER M5 ;
        RECT  68.544 0 68.568 0.192 ;
    END
  END d[355]
  PIN d[356]
    DIRECTION INPUT ;
    USE SIGNAL ;
    PORT
      LAYER M5 ;
        RECT  68.736 0 68.76 0.192 ;
    END
  END d[356]
  PIN d[357]
    DIRECTION INPUT ;
    USE SIGNAL ;
    PORT
      LAYER M5 ;
        RECT  68.928 0 68.952 0.192 ;
    END
  END d[357]
  PIN d[358]
    DIRECTION INPUT ;
    USE SIGNAL ;
    PORT
      LAYER M5 ;
        RECT  69.12 0 69.144 0.192 ;
    END
  END d[358]
  PIN d[359]
    DIRECTION INPUT ;
    USE SIGNAL ;
    PORT
      LAYER M5 ;
        RECT  69.312 0 69.336 0.192 ;
    END
  END d[359]
  PIN d[35]
    DIRECTION INPUT ;
    USE SIGNAL ;
    PORT
      LAYER M5 ;
        RECT  7.104 0 7.128 0.192 ;
    END
  END d[35]
  PIN d[360]
    DIRECTION INPUT ;
    USE SIGNAL ;
    PORT
      LAYER M5 ;
        RECT  69.504 0 69.528 0.192 ;
    END
  END d[360]
  PIN d[361]
    DIRECTION INPUT ;
    USE SIGNAL ;
    PORT
      LAYER M5 ;
        RECT  69.696 0 69.72 0.192 ;
    END
  END d[361]
  PIN d[362]
    DIRECTION INPUT ;
    USE SIGNAL ;
    PORT
      LAYER M5 ;
        RECT  69.888 0 69.912 0.192 ;
    END
  END d[362]
  PIN d[363]
    DIRECTION INPUT ;
    USE SIGNAL ;
    PORT
      LAYER M5 ;
        RECT  70.08 0 70.104 0.192 ;
    END
  END d[363]
  PIN d[364]
    DIRECTION INPUT ;
    USE SIGNAL ;
    PORT
      LAYER M5 ;
        RECT  70.272 0 70.296 0.192 ;
    END
  END d[364]
  PIN d[365]
    DIRECTION INPUT ;
    USE SIGNAL ;
    PORT
      LAYER M5 ;
        RECT  70.464 0 70.488 0.192 ;
    END
  END d[365]
  PIN d[366]
    DIRECTION INPUT ;
    USE SIGNAL ;
    PORT
      LAYER M5 ;
        RECT  70.656 0 70.68 0.192 ;
    END
  END d[366]
  PIN d[367]
    DIRECTION INPUT ;
    USE SIGNAL ;
    PORT
      LAYER M5 ;
        RECT  70.848 0 70.872 0.192 ;
    END
  END d[367]
  PIN d[368]
    DIRECTION INPUT ;
    USE SIGNAL ;
    PORT
      LAYER M5 ;
        RECT  71.04 0 71.064 0.192 ;
    END
  END d[368]
  PIN d[369]
    DIRECTION INPUT ;
    USE SIGNAL ;
    PORT
      LAYER M5 ;
        RECT  71.232 0 71.256 0.192 ;
    END
  END d[369]
  PIN d[36]
    DIRECTION INPUT ;
    USE SIGNAL ;
    PORT
      LAYER M5 ;
        RECT  7.296 0 7.32 0.192 ;
    END
  END d[36]
  PIN d[370]
    DIRECTION INPUT ;
    USE SIGNAL ;
    PORT
      LAYER M5 ;
        RECT  71.424 0 71.448 0.192 ;
    END
  END d[370]
  PIN d[371]
    DIRECTION INPUT ;
    USE SIGNAL ;
    PORT
      LAYER M5 ;
        RECT  71.616 0 71.64 0.192 ;
    END
  END d[371]
  PIN d[372]
    DIRECTION INPUT ;
    USE SIGNAL ;
    PORT
      LAYER M5 ;
        RECT  71.808 0 71.832 0.192 ;
    END
  END d[372]
  PIN d[373]
    DIRECTION INPUT ;
    USE SIGNAL ;
    PORT
      LAYER M5 ;
        RECT  72 0 72.024 0.192 ;
    END
  END d[373]
  PIN d[374]
    DIRECTION INPUT ;
    USE SIGNAL ;
    PORT
      LAYER M5 ;
        RECT  72.192 0 72.216 0.192 ;
    END
  END d[374]
  PIN d[375]
    DIRECTION INPUT ;
    USE SIGNAL ;
    PORT
      LAYER M5 ;
        RECT  72.384 0 72.408 0.192 ;
    END
  END d[375]
  PIN d[376]
    DIRECTION INPUT ;
    USE SIGNAL ;
    PORT
      LAYER M5 ;
        RECT  72.576 0 72.6 0.192 ;
    END
  END d[376]
  PIN d[377]
    DIRECTION INPUT ;
    USE SIGNAL ;
    PORT
      LAYER M5 ;
        RECT  72.768 0 72.792 0.192 ;
    END
  END d[377]
  PIN d[378]
    DIRECTION INPUT ;
    USE SIGNAL ;
    PORT
      LAYER M5 ;
        RECT  72.96 0 72.984 0.192 ;
    END
  END d[378]
  PIN d[379]
    DIRECTION INPUT ;
    USE SIGNAL ;
    PORT
      LAYER M5 ;
        RECT  73.152 0 73.176 0.192 ;
    END
  END d[379]
  PIN d[37]
    DIRECTION INPUT ;
    USE SIGNAL ;
    PORT
      LAYER M5 ;
        RECT  7.488 0 7.512 0.192 ;
    END
  END d[37]
  PIN d[380]
    DIRECTION INPUT ;
    USE SIGNAL ;
    PORT
      LAYER M5 ;
        RECT  73.344 0 73.368 0.192 ;
    END
  END d[380]
  PIN d[381]
    DIRECTION INPUT ;
    USE SIGNAL ;
    PORT
      LAYER M5 ;
        RECT  73.536 0 73.56 0.192 ;
    END
  END d[381]
  PIN d[382]
    DIRECTION INPUT ;
    USE SIGNAL ;
    PORT
      LAYER M5 ;
        RECT  73.728 0 73.752 0.192 ;
    END
  END d[382]
  PIN d[383]
    DIRECTION INPUT ;
    USE SIGNAL ;
    PORT
      LAYER M5 ;
        RECT  73.92 0 73.944 0.192 ;
    END
  END d[383]
  PIN d[384]
    DIRECTION INPUT ;
    USE SIGNAL ;
    PORT
      LAYER M5 ;
        RECT  74.112 0 74.136 0.192 ;
    END
  END d[384]
  PIN d[385]
    DIRECTION INPUT ;
    USE SIGNAL ;
    PORT
      LAYER M5 ;
        RECT  74.304 0 74.328 0.192 ;
    END
  END d[385]
  PIN d[386]
    DIRECTION INPUT ;
    USE SIGNAL ;
    PORT
      LAYER M5 ;
        RECT  74.496 0 74.52 0.192 ;
    END
  END d[386]
  PIN d[387]
    DIRECTION INPUT ;
    USE SIGNAL ;
    PORT
      LAYER M5 ;
        RECT  74.688 0 74.712 0.192 ;
    END
  END d[387]
  PIN d[388]
    DIRECTION INPUT ;
    USE SIGNAL ;
    PORT
      LAYER M5 ;
        RECT  74.88 0 74.904 0.192 ;
    END
  END d[388]
  PIN d[389]
    DIRECTION INPUT ;
    USE SIGNAL ;
    PORT
      LAYER M5 ;
        RECT  75.072 0 75.096 0.192 ;
    END
  END d[389]
  PIN d[38]
    DIRECTION INPUT ;
    USE SIGNAL ;
    PORT
      LAYER M5 ;
        RECT  7.68 0 7.704 0.192 ;
    END
  END d[38]
  PIN d[390]
    DIRECTION INPUT ;
    USE SIGNAL ;
    PORT
      LAYER M5 ;
        RECT  75.264 0 75.288 0.192 ;
    END
  END d[390]
  PIN d[391]
    DIRECTION INPUT ;
    USE SIGNAL ;
    PORT
      LAYER M5 ;
        RECT  75.456 0 75.48 0.192 ;
    END
  END d[391]
  PIN d[392]
    DIRECTION INPUT ;
    USE SIGNAL ;
    PORT
      LAYER M5 ;
        RECT  75.648 0 75.672 0.192 ;
    END
  END d[392]
  PIN d[393]
    DIRECTION INPUT ;
    USE SIGNAL ;
    PORT
      LAYER M5 ;
        RECT  75.84 0 75.864 0.192 ;
    END
  END d[393]
  PIN d[394]
    DIRECTION INPUT ;
    USE SIGNAL ;
    PORT
      LAYER M5 ;
        RECT  76.032 0 76.056 0.192 ;
    END
  END d[394]
  PIN d[395]
    DIRECTION INPUT ;
    USE SIGNAL ;
    PORT
      LAYER M5 ;
        RECT  76.224 0 76.248 0.192 ;
    END
  END d[395]
  PIN d[396]
    DIRECTION INPUT ;
    USE SIGNAL ;
    PORT
      LAYER M5 ;
        RECT  76.416 0 76.44 0.192 ;
    END
  END d[396]
  PIN d[397]
    DIRECTION INPUT ;
    USE SIGNAL ;
    PORT
      LAYER M5 ;
        RECT  76.608 0 76.632 0.192 ;
    END
  END d[397]
  PIN d[398]
    DIRECTION INPUT ;
    USE SIGNAL ;
    PORT
      LAYER M5 ;
        RECT  76.8 0 76.824 0.192 ;
    END
  END d[398]
  PIN d[399]
    DIRECTION INPUT ;
    USE SIGNAL ;
    PORT
      LAYER M5 ;
        RECT  76.992 0 77.016 0.192 ;
    END
  END d[399]
  PIN d[39]
    DIRECTION INPUT ;
    USE SIGNAL ;
    PORT
      LAYER M5 ;
        RECT  7.872 0 7.896 0.192 ;
    END
  END d[39]
  PIN d[3]
    DIRECTION INPUT ;
    USE SIGNAL ;
    PORT
      LAYER M5 ;
        RECT  0.96 0 0.984 0.192 ;
    END
  END d[3]
  PIN d[400]
    DIRECTION INPUT ;
    USE SIGNAL ;
    PORT
      LAYER M5 ;
        RECT  77.184 0 77.208 0.192 ;
    END
  END d[400]
  PIN d[401]
    DIRECTION INPUT ;
    USE SIGNAL ;
    PORT
      LAYER M5 ;
        RECT  77.376 0 77.4 0.192 ;
    END
  END d[401]
  PIN d[402]
    DIRECTION INPUT ;
    USE SIGNAL ;
    PORT
      LAYER M5 ;
        RECT  77.568 0 77.592 0.192 ;
    END
  END d[402]
  PIN d[403]
    DIRECTION INPUT ;
    USE SIGNAL ;
    PORT
      LAYER M5 ;
        RECT  77.76 0 77.784 0.192 ;
    END
  END d[403]
  PIN d[404]
    DIRECTION INPUT ;
    USE SIGNAL ;
    PORT
      LAYER M5 ;
        RECT  77.952 0 77.976 0.192 ;
    END
  END d[404]
  PIN d[405]
    DIRECTION INPUT ;
    USE SIGNAL ;
    PORT
      LAYER M5 ;
        RECT  78.144 0 78.168 0.192 ;
    END
  END d[405]
  PIN d[406]
    DIRECTION INPUT ;
    USE SIGNAL ;
    PORT
      LAYER M5 ;
        RECT  78.336 0 78.36 0.192 ;
    END
  END d[406]
  PIN d[407]
    DIRECTION INPUT ;
    USE SIGNAL ;
    PORT
      LAYER M5 ;
        RECT  78.528 0 78.552 0.192 ;
    END
  END d[407]
  PIN d[408]
    DIRECTION INPUT ;
    USE SIGNAL ;
    PORT
      LAYER M5 ;
        RECT  78.72 0 78.744 0.192 ;
    END
  END d[408]
  PIN d[409]
    DIRECTION INPUT ;
    USE SIGNAL ;
    PORT
      LAYER M5 ;
        RECT  78.912 0 78.936 0.192 ;
    END
  END d[409]
  PIN d[40]
    DIRECTION INPUT ;
    USE SIGNAL ;
    PORT
      LAYER M5 ;
        RECT  8.064 0 8.088 0.192 ;
    END
  END d[40]
  PIN d[410]
    DIRECTION INPUT ;
    USE SIGNAL ;
    PORT
      LAYER M5 ;
        RECT  79.104 0 79.128 0.192 ;
    END
  END d[410]
  PIN d[411]
    DIRECTION INPUT ;
    USE SIGNAL ;
    PORT
      LAYER M5 ;
        RECT  79.296 0 79.32 0.192 ;
    END
  END d[411]
  PIN d[412]
    DIRECTION INPUT ;
    USE SIGNAL ;
    PORT
      LAYER M5 ;
        RECT  79.488 0 79.512 0.192 ;
    END
  END d[412]
  PIN d[413]
    DIRECTION INPUT ;
    USE SIGNAL ;
    PORT
      LAYER M5 ;
        RECT  79.68 0 79.704 0.192 ;
    END
  END d[413]
  PIN d[414]
    DIRECTION INPUT ;
    USE SIGNAL ;
    PORT
      LAYER M5 ;
        RECT  79.872 0 79.896 0.192 ;
    END
  END d[414]
  PIN d[415]
    DIRECTION INPUT ;
    USE SIGNAL ;
    PORT
      LAYER M5 ;
        RECT  80.064 0 80.088 0.192 ;
    END
  END d[415]
  PIN d[416]
    DIRECTION INPUT ;
    USE SIGNAL ;
    PORT
      LAYER M5 ;
        RECT  80.256 0 80.28 0.192 ;
    END
  END d[416]
  PIN d[417]
    DIRECTION INPUT ;
    USE SIGNAL ;
    PORT
      LAYER M5 ;
        RECT  80.448 0 80.472 0.192 ;
    END
  END d[417]
  PIN d[418]
    DIRECTION INPUT ;
    USE SIGNAL ;
    PORT
      LAYER M5 ;
        RECT  80.64 0 80.664 0.192 ;
    END
  END d[418]
  PIN d[419]
    DIRECTION INPUT ;
    USE SIGNAL ;
    PORT
      LAYER M5 ;
        RECT  80.832 0 80.856 0.192 ;
    END
  END d[419]
  PIN d[41]
    DIRECTION INPUT ;
    USE SIGNAL ;
    PORT
      LAYER M5 ;
        RECT  8.256 0 8.28 0.192 ;
    END
  END d[41]
  PIN d[420]
    DIRECTION INPUT ;
    USE SIGNAL ;
    PORT
      LAYER M5 ;
        RECT  81.024 0 81.048 0.192 ;
    END
  END d[420]
  PIN d[421]
    DIRECTION INPUT ;
    USE SIGNAL ;
    PORT
      LAYER M5 ;
        RECT  81.216 0 81.24 0.192 ;
    END
  END d[421]
  PIN d[422]
    DIRECTION INPUT ;
    USE SIGNAL ;
    PORT
      LAYER M5 ;
        RECT  81.408 0 81.432 0.192 ;
    END
  END d[422]
  PIN d[423]
    DIRECTION INPUT ;
    USE SIGNAL ;
    PORT
      LAYER M5 ;
        RECT  81.6 0 81.624 0.192 ;
    END
  END d[423]
  PIN d[424]
    DIRECTION INPUT ;
    USE SIGNAL ;
    PORT
      LAYER M5 ;
        RECT  81.792 0 81.816 0.192 ;
    END
  END d[424]
  PIN d[425]
    DIRECTION INPUT ;
    USE SIGNAL ;
    PORT
      LAYER M5 ;
        RECT  81.984 0 82.008 0.192 ;
    END
  END d[425]
  PIN d[426]
    DIRECTION INPUT ;
    USE SIGNAL ;
    PORT
      LAYER M5 ;
        RECT  82.176 0 82.2 0.192 ;
    END
  END d[426]
  PIN d[427]
    DIRECTION INPUT ;
    USE SIGNAL ;
    PORT
      LAYER M5 ;
        RECT  82.368 0 82.392 0.192 ;
    END
  END d[427]
  PIN d[428]
    DIRECTION INPUT ;
    USE SIGNAL ;
    PORT
      LAYER M5 ;
        RECT  82.56 0 82.584 0.192 ;
    END
  END d[428]
  PIN d[429]
    DIRECTION INPUT ;
    USE SIGNAL ;
    PORT
      LAYER M5 ;
        RECT  82.752 0 82.776 0.192 ;
    END
  END d[429]
  PIN d[42]
    DIRECTION INPUT ;
    USE SIGNAL ;
    PORT
      LAYER M5 ;
        RECT  8.448 0 8.472 0.192 ;
    END
  END d[42]
  PIN d[430]
    DIRECTION INPUT ;
    USE SIGNAL ;
    PORT
      LAYER M5 ;
        RECT  82.944 0 82.968 0.192 ;
    END
  END d[430]
  PIN d[431]
    DIRECTION INPUT ;
    USE SIGNAL ;
    PORT
      LAYER M5 ;
        RECT  83.136 0 83.16 0.192 ;
    END
  END d[431]
  PIN d[432]
    DIRECTION INPUT ;
    USE SIGNAL ;
    PORT
      LAYER M5 ;
        RECT  83.328 0 83.352 0.192 ;
    END
  END d[432]
  PIN d[433]
    DIRECTION INPUT ;
    USE SIGNAL ;
    PORT
      LAYER M5 ;
        RECT  83.52 0 83.544 0.192 ;
    END
  END d[433]
  PIN d[434]
    DIRECTION INPUT ;
    USE SIGNAL ;
    PORT
      LAYER M5 ;
        RECT  83.712 0 83.736 0.192 ;
    END
  END d[434]
  PIN d[435]
    DIRECTION INPUT ;
    USE SIGNAL ;
    PORT
      LAYER M5 ;
        RECT  83.904 0 83.928 0.192 ;
    END
  END d[435]
  PIN d[436]
    DIRECTION INPUT ;
    USE SIGNAL ;
    PORT
      LAYER M5 ;
        RECT  84.096 0 84.12 0.192 ;
    END
  END d[436]
  PIN d[437]
    DIRECTION INPUT ;
    USE SIGNAL ;
    PORT
      LAYER M5 ;
        RECT  84.288 0 84.312 0.192 ;
    END
  END d[437]
  PIN d[438]
    DIRECTION INPUT ;
    USE SIGNAL ;
    PORT
      LAYER M5 ;
        RECT  84.48 0 84.504 0.192 ;
    END
  END d[438]
  PIN d[439]
    DIRECTION INPUT ;
    USE SIGNAL ;
    PORT
      LAYER M5 ;
        RECT  84.672 0 84.696 0.192 ;
    END
  END d[439]
  PIN d[43]
    DIRECTION INPUT ;
    USE SIGNAL ;
    PORT
      LAYER M5 ;
        RECT  8.64 0 8.664 0.192 ;
    END
  END d[43]
  PIN d[440]
    DIRECTION INPUT ;
    USE SIGNAL ;
    PORT
      LAYER M5 ;
        RECT  84.864 0 84.888 0.192 ;
    END
  END d[440]
  PIN d[441]
    DIRECTION INPUT ;
    USE SIGNAL ;
    PORT
      LAYER M5 ;
        RECT  85.056 0 85.08 0.192 ;
    END
  END d[441]
  PIN d[442]
    DIRECTION INPUT ;
    USE SIGNAL ;
    PORT
      LAYER M5 ;
        RECT  85.248 0 85.272 0.192 ;
    END
  END d[442]
  PIN d[443]
    DIRECTION INPUT ;
    USE SIGNAL ;
    PORT
      LAYER M5 ;
        RECT  85.44 0 85.464 0.192 ;
    END
  END d[443]
  PIN d[444]
    DIRECTION INPUT ;
    USE SIGNAL ;
    PORT
      LAYER M5 ;
        RECT  85.632 0 85.656 0.192 ;
    END
  END d[444]
  PIN d[445]
    DIRECTION INPUT ;
    USE SIGNAL ;
    PORT
      LAYER M5 ;
        RECT  85.824 0 85.848 0.192 ;
    END
  END d[445]
  PIN d[446]
    DIRECTION INPUT ;
    USE SIGNAL ;
    PORT
      LAYER M5 ;
        RECT  86.016 0 86.04 0.192 ;
    END
  END d[446]
  PIN d[447]
    DIRECTION INPUT ;
    USE SIGNAL ;
    PORT
      LAYER M5 ;
        RECT  86.208 0 86.232 0.192 ;
    END
  END d[447]
  PIN d[448]
    DIRECTION INPUT ;
    USE SIGNAL ;
    PORT
      LAYER M5 ;
        RECT  86.4 0 86.424 0.192 ;
    END
  END d[448]
  PIN d[449]
    DIRECTION INPUT ;
    USE SIGNAL ;
    PORT
      LAYER M5 ;
        RECT  86.592 0 86.616 0.192 ;
    END
  END d[449]
  PIN d[44]
    DIRECTION INPUT ;
    USE SIGNAL ;
    PORT
      LAYER M5 ;
        RECT  8.832 0 8.856 0.192 ;
    END
  END d[44]
  PIN d[450]
    DIRECTION INPUT ;
    USE SIGNAL ;
    PORT
      LAYER M5 ;
        RECT  86.784 0 86.808 0.192 ;
    END
  END d[450]
  PIN d[451]
    DIRECTION INPUT ;
    USE SIGNAL ;
    PORT
      LAYER M5 ;
        RECT  86.976 0 87 0.192 ;
    END
  END d[451]
  PIN d[452]
    DIRECTION INPUT ;
    USE SIGNAL ;
    PORT
      LAYER M5 ;
        RECT  87.168 0 87.192 0.192 ;
    END
  END d[452]
  PIN d[453]
    DIRECTION INPUT ;
    USE SIGNAL ;
    PORT
      LAYER M5 ;
        RECT  87.36 0 87.384 0.192 ;
    END
  END d[453]
  PIN d[454]
    DIRECTION INPUT ;
    USE SIGNAL ;
    PORT
      LAYER M5 ;
        RECT  87.552 0 87.576 0.192 ;
    END
  END d[454]
  PIN d[455]
    DIRECTION INPUT ;
    USE SIGNAL ;
    PORT
      LAYER M5 ;
        RECT  87.744 0 87.768 0.192 ;
    END
  END d[455]
  PIN d[456]
    DIRECTION INPUT ;
    USE SIGNAL ;
    PORT
      LAYER M5 ;
        RECT  87.936 0 87.96 0.192 ;
    END
  END d[456]
  PIN d[457]
    DIRECTION INPUT ;
    USE SIGNAL ;
    PORT
      LAYER M5 ;
        RECT  88.128 0 88.152 0.192 ;
    END
  END d[457]
  PIN d[458]
    DIRECTION INPUT ;
    USE SIGNAL ;
    PORT
      LAYER M5 ;
        RECT  88.32 0 88.344 0.192 ;
    END
  END d[458]
  PIN d[459]
    DIRECTION INPUT ;
    USE SIGNAL ;
    PORT
      LAYER M5 ;
        RECT  88.512 0 88.536 0.192 ;
    END
  END d[459]
  PIN d[45]
    DIRECTION INPUT ;
    USE SIGNAL ;
    PORT
      LAYER M5 ;
        RECT  9.024 0 9.048 0.192 ;
    END
  END d[45]
  PIN d[460]
    DIRECTION INPUT ;
    USE SIGNAL ;
    PORT
      LAYER M5 ;
        RECT  88.704 0 88.728 0.192 ;
    END
  END d[460]
  PIN d[461]
    DIRECTION INPUT ;
    USE SIGNAL ;
    PORT
      LAYER M5 ;
        RECT  88.896 0 88.92 0.192 ;
    END
  END d[461]
  PIN d[462]
    DIRECTION INPUT ;
    USE SIGNAL ;
    PORT
      LAYER M5 ;
        RECT  89.088 0 89.112 0.192 ;
    END
  END d[462]
  PIN d[463]
    DIRECTION INPUT ;
    USE SIGNAL ;
    PORT
      LAYER M5 ;
        RECT  89.28 0 89.304 0.192 ;
    END
  END d[463]
  PIN d[464]
    DIRECTION INPUT ;
    USE SIGNAL ;
    PORT
      LAYER M5 ;
        RECT  89.472 0 89.496 0.192 ;
    END
  END d[464]
  PIN d[465]
    DIRECTION INPUT ;
    USE SIGNAL ;
    PORT
      LAYER M5 ;
        RECT  89.664 0 89.688 0.192 ;
    END
  END d[465]
  PIN d[466]
    DIRECTION INPUT ;
    USE SIGNAL ;
    PORT
      LAYER M5 ;
        RECT  89.856 0 89.88 0.192 ;
    END
  END d[466]
  PIN d[467]
    DIRECTION INPUT ;
    USE SIGNAL ;
    PORT
      LAYER M5 ;
        RECT  90.048 0 90.072 0.192 ;
    END
  END d[467]
  PIN d[468]
    DIRECTION INPUT ;
    USE SIGNAL ;
    PORT
      LAYER M5 ;
        RECT  90.24 0 90.264 0.192 ;
    END
  END d[468]
  PIN d[469]
    DIRECTION INPUT ;
    USE SIGNAL ;
    PORT
      LAYER M5 ;
        RECT  90.432 0 90.456 0.192 ;
    END
  END d[469]
  PIN d[46]
    DIRECTION INPUT ;
    USE SIGNAL ;
    PORT
      LAYER M5 ;
        RECT  9.216 0 9.24 0.192 ;
    END
  END d[46]
  PIN d[470]
    DIRECTION INPUT ;
    USE SIGNAL ;
    PORT
      LAYER M5 ;
        RECT  90.624 0 90.648 0.192 ;
    END
  END d[470]
  PIN d[471]
    DIRECTION INPUT ;
    USE SIGNAL ;
    PORT
      LAYER M5 ;
        RECT  90.816 0 90.84 0.192 ;
    END
  END d[471]
  PIN d[472]
    DIRECTION INPUT ;
    USE SIGNAL ;
    PORT
      LAYER M5 ;
        RECT  91.008 0 91.032 0.192 ;
    END
  END d[472]
  PIN d[473]
    DIRECTION INPUT ;
    USE SIGNAL ;
    PORT
      LAYER M5 ;
        RECT  91.2 0 91.224 0.192 ;
    END
  END d[473]
  PIN d[474]
    DIRECTION INPUT ;
    USE SIGNAL ;
    PORT
      LAYER M5 ;
        RECT  91.392 0 91.416 0.192 ;
    END
  END d[474]
  PIN d[475]
    DIRECTION INPUT ;
    USE SIGNAL ;
    PORT
      LAYER M5 ;
        RECT  91.584 0 91.608 0.192 ;
    END
  END d[475]
  PIN d[476]
    DIRECTION INPUT ;
    USE SIGNAL ;
    PORT
      LAYER M5 ;
        RECT  91.776 0 91.8 0.192 ;
    END
  END d[476]
  PIN d[477]
    DIRECTION INPUT ;
    USE SIGNAL ;
    PORT
      LAYER M5 ;
        RECT  91.968 0 91.992 0.192 ;
    END
  END d[477]
  PIN d[478]
    DIRECTION INPUT ;
    USE SIGNAL ;
    PORT
      LAYER M5 ;
        RECT  92.16 0 92.184 0.192 ;
    END
  END d[478]
  PIN d[479]
    DIRECTION INPUT ;
    USE SIGNAL ;
    PORT
      LAYER M5 ;
        RECT  92.352 0 92.376 0.192 ;
    END
  END d[479]
  PIN d[47]
    DIRECTION INPUT ;
    USE SIGNAL ;
    PORT
      LAYER M5 ;
        RECT  9.408 0 9.432 0.192 ;
    END
  END d[47]
  PIN d[480]
    DIRECTION INPUT ;
    USE SIGNAL ;
    PORT
      LAYER M5 ;
        RECT  92.544 0 92.568 0.192 ;
    END
  END d[480]
  PIN d[481]
    DIRECTION INPUT ;
    USE SIGNAL ;
    PORT
      LAYER M5 ;
        RECT  92.736 0 92.76 0.192 ;
    END
  END d[481]
  PIN d[482]
    DIRECTION INPUT ;
    USE SIGNAL ;
    PORT
      LAYER M5 ;
        RECT  92.928 0 92.952 0.192 ;
    END
  END d[482]
  PIN d[483]
    DIRECTION INPUT ;
    USE SIGNAL ;
    PORT
      LAYER M5 ;
        RECT  93.12 0 93.144 0.192 ;
    END
  END d[483]
  PIN d[484]
    DIRECTION INPUT ;
    USE SIGNAL ;
    PORT
      LAYER M5 ;
        RECT  93.312 0 93.336 0.192 ;
    END
  END d[484]
  PIN d[485]
    DIRECTION INPUT ;
    USE SIGNAL ;
    PORT
      LAYER M5 ;
        RECT  93.504 0 93.528 0.192 ;
    END
  END d[485]
  PIN d[486]
    DIRECTION INPUT ;
    USE SIGNAL ;
    PORT
      LAYER M5 ;
        RECT  93.696 0 93.72 0.192 ;
    END
  END d[486]
  PIN d[487]
    DIRECTION INPUT ;
    USE SIGNAL ;
    PORT
      LAYER M5 ;
        RECT  93.888 0 93.912 0.192 ;
    END
  END d[487]
  PIN d[488]
    DIRECTION INPUT ;
    USE SIGNAL ;
    PORT
      LAYER M5 ;
        RECT  94.08 0 94.104 0.192 ;
    END
  END d[488]
  PIN d[489]
    DIRECTION INPUT ;
    USE SIGNAL ;
    PORT
      LAYER M5 ;
        RECT  94.272 0 94.296 0.192 ;
    END
  END d[489]
  PIN d[48]
    DIRECTION INPUT ;
    USE SIGNAL ;
    PORT
      LAYER M5 ;
        RECT  9.6 0 9.624 0.192 ;
    END
  END d[48]
  PIN d[490]
    DIRECTION INPUT ;
    USE SIGNAL ;
    PORT
      LAYER M5 ;
        RECT  94.464 0 94.488 0.192 ;
    END
  END d[490]
  PIN d[491]
    DIRECTION INPUT ;
    USE SIGNAL ;
    PORT
      LAYER M5 ;
        RECT  94.656 0 94.68 0.192 ;
    END
  END d[491]
  PIN d[492]
    DIRECTION INPUT ;
    USE SIGNAL ;
    PORT
      LAYER M5 ;
        RECT  94.848 0 94.872 0.192 ;
    END
  END d[492]
  PIN d[493]
    DIRECTION INPUT ;
    USE SIGNAL ;
    PORT
      LAYER M5 ;
        RECT  95.04 0 95.064 0.192 ;
    END
  END d[493]
  PIN d[494]
    DIRECTION INPUT ;
    USE SIGNAL ;
    PORT
      LAYER M5 ;
        RECT  95.232 0 95.256 0.192 ;
    END
  END d[494]
  PIN d[495]
    DIRECTION INPUT ;
    USE SIGNAL ;
    PORT
      LAYER M5 ;
        RECT  95.424 0 95.448 0.192 ;
    END
  END d[495]
  PIN d[496]
    DIRECTION INPUT ;
    USE SIGNAL ;
    PORT
      LAYER M5 ;
        RECT  95.616 0 95.64 0.192 ;
    END
  END d[496]
  PIN d[497]
    DIRECTION INPUT ;
    USE SIGNAL ;
    PORT
      LAYER M5 ;
        RECT  95.808 0 95.832 0.192 ;
    END
  END d[497]
  PIN d[498]
    DIRECTION INPUT ;
    USE SIGNAL ;
    PORT
      LAYER M5 ;
        RECT  96 0 96.024 0.192 ;
    END
  END d[498]
  PIN d[499]
    DIRECTION INPUT ;
    USE SIGNAL ;
    PORT
      LAYER M5 ;
        RECT  96.192 0 96.216 0.192 ;
    END
  END d[499]
  PIN d[49]
    DIRECTION INPUT ;
    USE SIGNAL ;
    PORT
      LAYER M5 ;
        RECT  9.792 0 9.816 0.192 ;
    END
  END d[49]
  PIN d[4]
    DIRECTION INPUT ;
    USE SIGNAL ;
    PORT
      LAYER M5 ;
        RECT  1.152 0 1.176 0.192 ;
    END
  END d[4]
  PIN d[500]
    DIRECTION INPUT ;
    USE SIGNAL ;
    PORT
      LAYER M5 ;
        RECT  96.384 0 96.408 0.192 ;
    END
  END d[500]
  PIN d[501]
    DIRECTION INPUT ;
    USE SIGNAL ;
    PORT
      LAYER M5 ;
        RECT  96.576 0 96.6 0.192 ;
    END
  END d[501]
  PIN d[502]
    DIRECTION INPUT ;
    USE SIGNAL ;
    PORT
      LAYER M5 ;
        RECT  96.768 0 96.792 0.192 ;
    END
  END d[502]
  PIN d[503]
    DIRECTION INPUT ;
    USE SIGNAL ;
    PORT
      LAYER M5 ;
        RECT  96.96 0 96.984 0.192 ;
    END
  END d[503]
  PIN d[504]
    DIRECTION INPUT ;
    USE SIGNAL ;
    PORT
      LAYER M5 ;
        RECT  97.152 0 97.176 0.192 ;
    END
  END d[504]
  PIN d[505]
    DIRECTION INPUT ;
    USE SIGNAL ;
    PORT
      LAYER M5 ;
        RECT  97.344 0 97.368 0.192 ;
    END
  END d[505]
  PIN d[506]
    DIRECTION INPUT ;
    USE SIGNAL ;
    PORT
      LAYER M5 ;
        RECT  97.536 0 97.56 0.192 ;
    END
  END d[506]
  PIN d[507]
    DIRECTION INPUT ;
    USE SIGNAL ;
    PORT
      LAYER M5 ;
        RECT  97.728 0 97.752 0.192 ;
    END
  END d[507]
  PIN d[508]
    DIRECTION INPUT ;
    USE SIGNAL ;
    PORT
      LAYER M5 ;
        RECT  97.92 0 97.944 0.192 ;
    END
  END d[508]
  PIN d[509]
    DIRECTION INPUT ;
    USE SIGNAL ;
    PORT
      LAYER M5 ;
        RECT  98.112 0 98.136 0.192 ;
    END
  END d[509]
  PIN d[50]
    DIRECTION INPUT ;
    USE SIGNAL ;
    PORT
      LAYER M5 ;
        RECT  9.984 0 10.008 0.192 ;
    END
  END d[50]
  PIN d[510]
    DIRECTION INPUT ;
    USE SIGNAL ;
    PORT
      LAYER M5 ;
        RECT  98.304 0 98.328 0.192 ;
    END
  END d[510]
  PIN d[511]
    DIRECTION INPUT ;
    USE SIGNAL ;
    PORT
      LAYER M5 ;
        RECT  98.496 0 98.52 0.192 ;
    END
  END d[511]
  PIN d[512]
    DIRECTION INPUT ;
    USE SIGNAL ;
    PORT
      LAYER M5 ;
        RECT  98.688 0 98.712 0.192 ;
    END
  END d[512]
  PIN d[513]
    DIRECTION INPUT ;
    USE SIGNAL ;
    PORT
      LAYER M5 ;
        RECT  98.88 0 98.904 0.192 ;
    END
  END d[513]
  PIN d[514]
    DIRECTION INPUT ;
    USE SIGNAL ;
    PORT
      LAYER M5 ;
        RECT  99.072 0 99.096 0.192 ;
    END
  END d[514]
  PIN d[515]
    DIRECTION INPUT ;
    USE SIGNAL ;
    PORT
      LAYER M5 ;
        RECT  99.264 0 99.288 0.192 ;
    END
  END d[515]
  PIN d[516]
    DIRECTION INPUT ;
    USE SIGNAL ;
    PORT
      LAYER M5 ;
        RECT  99.456 0 99.48 0.192 ;
    END
  END d[516]
  PIN d[517]
    DIRECTION INPUT ;
    USE SIGNAL ;
    PORT
      LAYER M5 ;
        RECT  99.648 0 99.672 0.192 ;
    END
  END d[517]
  PIN d[518]
    DIRECTION INPUT ;
    USE SIGNAL ;
    PORT
      LAYER M5 ;
        RECT  99.84 0 99.864 0.192 ;
    END
  END d[518]
  PIN d[519]
    DIRECTION INPUT ;
    USE SIGNAL ;
    PORT
      LAYER M5 ;
        RECT  100.032 0 100.056 0.192 ;
    END
  END d[519]
  PIN d[51]
    DIRECTION INPUT ;
    USE SIGNAL ;
    PORT
      LAYER M5 ;
        RECT  10.176 0 10.2 0.192 ;
    END
  END d[51]
  PIN d[520]
    DIRECTION INPUT ;
    USE SIGNAL ;
    PORT
      LAYER M5 ;
        RECT  100.224 0 100.248 0.192 ;
    END
  END d[520]
  PIN d[521]
    DIRECTION INPUT ;
    USE SIGNAL ;
    PORT
      LAYER M5 ;
        RECT  100.416 0 100.44 0.192 ;
    END
  END d[521]
  PIN d[522]
    DIRECTION INPUT ;
    USE SIGNAL ;
    PORT
      LAYER M5 ;
        RECT  100.608 0 100.632 0.192 ;
    END
  END d[522]
  PIN d[523]
    DIRECTION INPUT ;
    USE SIGNAL ;
    PORT
      LAYER M5 ;
        RECT  100.8 0 100.824 0.192 ;
    END
  END d[523]
  PIN d[524]
    DIRECTION INPUT ;
    USE SIGNAL ;
    PORT
      LAYER M5 ;
        RECT  100.992 0 101.016 0.192 ;
    END
  END d[524]
  PIN d[525]
    DIRECTION INPUT ;
    USE SIGNAL ;
    PORT
      LAYER M5 ;
        RECT  101.184 0 101.208 0.192 ;
    END
  END d[525]
  PIN d[526]
    DIRECTION INPUT ;
    USE SIGNAL ;
    PORT
      LAYER M5 ;
        RECT  101.376 0 101.4 0.192 ;
    END
  END d[526]
  PIN d[527]
    DIRECTION INPUT ;
    USE SIGNAL ;
    PORT
      LAYER M5 ;
        RECT  101.568 0 101.592 0.192 ;
    END
  END d[527]
  PIN d[528]
    DIRECTION INPUT ;
    USE SIGNAL ;
    PORT
      LAYER M5 ;
        RECT  101.76 0 101.784 0.192 ;
    END
  END d[528]
  PIN d[529]
    DIRECTION INPUT ;
    USE SIGNAL ;
    PORT
      LAYER M5 ;
        RECT  101.952 0 101.976 0.192 ;
    END
  END d[529]
  PIN d[52]
    DIRECTION INPUT ;
    USE SIGNAL ;
    PORT
      LAYER M5 ;
        RECT  10.368 0 10.392 0.192 ;
    END
  END d[52]
  PIN d[530]
    DIRECTION INPUT ;
    USE SIGNAL ;
    PORT
      LAYER M5 ;
        RECT  102.144 0 102.168 0.192 ;
    END
  END d[530]
  PIN d[531]
    DIRECTION INPUT ;
    USE SIGNAL ;
    PORT
      LAYER M5 ;
        RECT  102.336 0 102.36 0.192 ;
    END
  END d[531]
  PIN d[532]
    DIRECTION INPUT ;
    USE SIGNAL ;
    PORT
      LAYER M5 ;
        RECT  102.528 0 102.552 0.192 ;
    END
  END d[532]
  PIN d[533]
    DIRECTION INPUT ;
    USE SIGNAL ;
    PORT
      LAYER M5 ;
        RECT  102.72 0 102.744 0.192 ;
    END
  END d[533]
  PIN d[534]
    DIRECTION INPUT ;
    USE SIGNAL ;
    PORT
      LAYER M5 ;
        RECT  102.912 0 102.936 0.192 ;
    END
  END d[534]
  PIN d[535]
    DIRECTION INPUT ;
    USE SIGNAL ;
    PORT
      LAYER M5 ;
        RECT  103.104 0 103.128 0.192 ;
    END
  END d[535]
  PIN d[536]
    DIRECTION INPUT ;
    USE SIGNAL ;
    PORT
      LAYER M5 ;
        RECT  103.296 0 103.32 0.192 ;
    END
  END d[536]
  PIN d[537]
    DIRECTION INPUT ;
    USE SIGNAL ;
    PORT
      LAYER M5 ;
        RECT  103.488 0 103.512 0.192 ;
    END
  END d[537]
  PIN d[538]
    DIRECTION INPUT ;
    USE SIGNAL ;
    PORT
      LAYER M5 ;
        RECT  103.68 0 103.704 0.192 ;
    END
  END d[538]
  PIN d[539]
    DIRECTION INPUT ;
    USE SIGNAL ;
    PORT
      LAYER M5 ;
        RECT  103.872 0 103.896 0.192 ;
    END
  END d[539]
  PIN d[53]
    DIRECTION INPUT ;
    USE SIGNAL ;
    PORT
      LAYER M5 ;
        RECT  10.56 0 10.584 0.192 ;
    END
  END d[53]
  PIN d[540]
    DIRECTION INPUT ;
    USE SIGNAL ;
    PORT
      LAYER M5 ;
        RECT  104.064 0 104.088 0.192 ;
    END
  END d[540]
  PIN d[541]
    DIRECTION INPUT ;
    USE SIGNAL ;
    PORT
      LAYER M5 ;
        RECT  104.256 0 104.28 0.192 ;
    END
  END d[541]
  PIN d[542]
    DIRECTION INPUT ;
    USE SIGNAL ;
    PORT
      LAYER M5 ;
        RECT  104.448 0 104.472 0.192 ;
    END
  END d[542]
  PIN d[543]
    DIRECTION INPUT ;
    USE SIGNAL ;
    PORT
      LAYER M5 ;
        RECT  104.64 0 104.664 0.192 ;
    END
  END d[543]
  PIN d[54]
    DIRECTION INPUT ;
    USE SIGNAL ;
    PORT
      LAYER M5 ;
        RECT  10.752 0 10.776 0.192 ;
    END
  END d[54]
  PIN d[55]
    DIRECTION INPUT ;
    USE SIGNAL ;
    PORT
      LAYER M5 ;
        RECT  10.944 0 10.968 0.192 ;
    END
  END d[55]
  PIN d[56]
    DIRECTION INPUT ;
    USE SIGNAL ;
    PORT
      LAYER M5 ;
        RECT  11.136 0 11.16 0.192 ;
    END
  END d[56]
  PIN d[57]
    DIRECTION INPUT ;
    USE SIGNAL ;
    PORT
      LAYER M5 ;
        RECT  11.328 0 11.352 0.192 ;
    END
  END d[57]
  PIN d[58]
    DIRECTION INPUT ;
    USE SIGNAL ;
    PORT
      LAYER M5 ;
        RECT  11.52 0 11.544 0.192 ;
    END
  END d[58]
  PIN d[59]
    DIRECTION INPUT ;
    USE SIGNAL ;
    PORT
      LAYER M5 ;
        RECT  11.712 0 11.736 0.192 ;
    END
  END d[59]
  PIN d[5]
    DIRECTION INPUT ;
    USE SIGNAL ;
    PORT
      LAYER M5 ;
        RECT  1.344 0 1.368 0.192 ;
    END
  END d[5]
  PIN d[60]
    DIRECTION INPUT ;
    USE SIGNAL ;
    PORT
      LAYER M5 ;
        RECT  11.904 0 11.928 0.192 ;
    END
  END d[60]
  PIN d[61]
    DIRECTION INPUT ;
    USE SIGNAL ;
    PORT
      LAYER M5 ;
        RECT  12.096 0 12.12 0.192 ;
    END
  END d[61]
  PIN d[62]
    DIRECTION INPUT ;
    USE SIGNAL ;
    PORT
      LAYER M5 ;
        RECT  12.288 0 12.312 0.192 ;
    END
  END d[62]
  PIN d[63]
    DIRECTION INPUT ;
    USE SIGNAL ;
    PORT
      LAYER M5 ;
        RECT  12.48 0 12.504 0.192 ;
    END
  END d[63]
  PIN d[64]
    DIRECTION INPUT ;
    USE SIGNAL ;
    PORT
      LAYER M5 ;
        RECT  12.672 0 12.696 0.192 ;
    END
  END d[64]
  PIN d[65]
    DIRECTION INPUT ;
    USE SIGNAL ;
    PORT
      LAYER M5 ;
        RECT  12.864 0 12.888 0.192 ;
    END
  END d[65]
  PIN d[66]
    DIRECTION INPUT ;
    USE SIGNAL ;
    PORT
      LAYER M5 ;
        RECT  13.056 0 13.08 0.192 ;
    END
  END d[66]
  PIN d[67]
    DIRECTION INPUT ;
    USE SIGNAL ;
    PORT
      LAYER M5 ;
        RECT  13.248 0 13.272 0.192 ;
    END
  END d[67]
  PIN d[68]
    DIRECTION INPUT ;
    USE SIGNAL ;
    PORT
      LAYER M5 ;
        RECT  13.44 0 13.464 0.192 ;
    END
  END d[68]
  PIN d[69]
    DIRECTION INPUT ;
    USE SIGNAL ;
    PORT
      LAYER M5 ;
        RECT  13.632 0 13.656 0.192 ;
    END
  END d[69]
  PIN d[6]
    DIRECTION INPUT ;
    USE SIGNAL ;
    PORT
      LAYER M5 ;
        RECT  1.536 0 1.56 0.192 ;
    END
  END d[6]
  PIN d[70]
    DIRECTION INPUT ;
    USE SIGNAL ;
    PORT
      LAYER M5 ;
        RECT  13.824 0 13.848 0.192 ;
    END
  END d[70]
  PIN d[71]
    DIRECTION INPUT ;
    USE SIGNAL ;
    PORT
      LAYER M5 ;
        RECT  14.016 0 14.04 0.192 ;
    END
  END d[71]
  PIN d[72]
    DIRECTION INPUT ;
    USE SIGNAL ;
    PORT
      LAYER M5 ;
        RECT  14.208 0 14.232 0.192 ;
    END
  END d[72]
  PIN d[73]
    DIRECTION INPUT ;
    USE SIGNAL ;
    PORT
      LAYER M5 ;
        RECT  14.4 0 14.424 0.192 ;
    END
  END d[73]
  PIN d[74]
    DIRECTION INPUT ;
    USE SIGNAL ;
    PORT
      LAYER M5 ;
        RECT  14.592 0 14.616 0.192 ;
    END
  END d[74]
  PIN d[75]
    DIRECTION INPUT ;
    USE SIGNAL ;
    PORT
      LAYER M5 ;
        RECT  14.784 0 14.808 0.192 ;
    END
  END d[75]
  PIN d[76]
    DIRECTION INPUT ;
    USE SIGNAL ;
    PORT
      LAYER M5 ;
        RECT  14.976 0 15 0.192 ;
    END
  END d[76]
  PIN d[77]
    DIRECTION INPUT ;
    USE SIGNAL ;
    PORT
      LAYER M5 ;
        RECT  15.168 0 15.192 0.192 ;
    END
  END d[77]
  PIN d[78]
    DIRECTION INPUT ;
    USE SIGNAL ;
    PORT
      LAYER M5 ;
        RECT  15.36 0 15.384 0.192 ;
    END
  END d[78]
  PIN d[79]
    DIRECTION INPUT ;
    USE SIGNAL ;
    PORT
      LAYER M5 ;
        RECT  15.552 0 15.576 0.192 ;
    END
  END d[79]
  PIN d[7]
    DIRECTION INPUT ;
    USE SIGNAL ;
    PORT
      LAYER M5 ;
        RECT  1.728 0 1.752 0.192 ;
    END
  END d[7]
  PIN d[80]
    DIRECTION INPUT ;
    USE SIGNAL ;
    PORT
      LAYER M5 ;
        RECT  15.744 0 15.768 0.192 ;
    END
  END d[80]
  PIN d[81]
    DIRECTION INPUT ;
    USE SIGNAL ;
    PORT
      LAYER M5 ;
        RECT  15.936 0 15.96 0.192 ;
    END
  END d[81]
  PIN d[82]
    DIRECTION INPUT ;
    USE SIGNAL ;
    PORT
      LAYER M5 ;
        RECT  16.128 0 16.152 0.192 ;
    END
  END d[82]
  PIN d[83]
    DIRECTION INPUT ;
    USE SIGNAL ;
    PORT
      LAYER M5 ;
        RECT  16.32 0 16.344 0.192 ;
    END
  END d[83]
  PIN d[84]
    DIRECTION INPUT ;
    USE SIGNAL ;
    PORT
      LAYER M5 ;
        RECT  16.512 0 16.536 0.192 ;
    END
  END d[84]
  PIN d[85]
    DIRECTION INPUT ;
    USE SIGNAL ;
    PORT
      LAYER M5 ;
        RECT  16.704 0 16.728 0.192 ;
    END
  END d[85]
  PIN d[86]
    DIRECTION INPUT ;
    USE SIGNAL ;
    PORT
      LAYER M5 ;
        RECT  16.896 0 16.92 0.192 ;
    END
  END d[86]
  PIN d[87]
    DIRECTION INPUT ;
    USE SIGNAL ;
    PORT
      LAYER M5 ;
        RECT  17.088 0 17.112 0.192 ;
    END
  END d[87]
  PIN d[88]
    DIRECTION INPUT ;
    USE SIGNAL ;
    PORT
      LAYER M5 ;
        RECT  17.28 0 17.304 0.192 ;
    END
  END d[88]
  PIN d[89]
    DIRECTION INPUT ;
    USE SIGNAL ;
    PORT
      LAYER M5 ;
        RECT  17.472 0 17.496 0.192 ;
    END
  END d[89]
  PIN d[8]
    DIRECTION INPUT ;
    USE SIGNAL ;
    PORT
      LAYER M5 ;
        RECT  1.92 0 1.944 0.192 ;
    END
  END d[8]
  PIN d[90]
    DIRECTION INPUT ;
    USE SIGNAL ;
    PORT
      LAYER M5 ;
        RECT  17.664 0 17.688 0.192 ;
    END
  END d[90]
  PIN d[91]
    DIRECTION INPUT ;
    USE SIGNAL ;
    PORT
      LAYER M5 ;
        RECT  17.856 0 17.88 0.192 ;
    END
  END d[91]
  PIN d[92]
    DIRECTION INPUT ;
    USE SIGNAL ;
    PORT
      LAYER M5 ;
        RECT  18.048 0 18.072 0.192 ;
    END
  END d[92]
  PIN d[93]
    DIRECTION INPUT ;
    USE SIGNAL ;
    PORT
      LAYER M5 ;
        RECT  18.24 0 18.264 0.192 ;
    END
  END d[93]
  PIN d[94]
    DIRECTION INPUT ;
    USE SIGNAL ;
    PORT
      LAYER M5 ;
        RECT  18.432 0 18.456 0.192 ;
    END
  END d[94]
  PIN d[95]
    DIRECTION INPUT ;
    USE SIGNAL ;
    PORT
      LAYER M5 ;
        RECT  18.624 0 18.648 0.192 ;
    END
  END d[95]
  PIN d[96]
    DIRECTION INPUT ;
    USE SIGNAL ;
    PORT
      LAYER M5 ;
        RECT  18.816 0 18.84 0.192 ;
    END
  END d[96]
  PIN d[97]
    DIRECTION INPUT ;
    USE SIGNAL ;
    PORT
      LAYER M5 ;
        RECT  19.008 0 19.032 0.192 ;
    END
  END d[97]
  PIN d[98]
    DIRECTION INPUT ;
    USE SIGNAL ;
    PORT
      LAYER M5 ;
        RECT  19.2 0 19.224 0.192 ;
    END
  END d[98]
  PIN d[99]
    DIRECTION INPUT ;
    USE SIGNAL ;
    PORT
      LAYER M5 ;
        RECT  19.392 0 19.416 0.192 ;
    END
  END d[99]
  PIN d[9]
    DIRECTION INPUT ;
    USE SIGNAL ;
    PORT
      LAYER M5 ;
        RECT  2.112 0 2.136 0.192 ;
    END
  END d[9]
  PIN q[0]
    DIRECTION OUTPUT ;
    USE SIGNAL ;
    PORT
      LAYER M5 ;
        RECT  0.384 11.688 0.408 11.88 ;
    END
  END q[0]
  PIN q[100]
    DIRECTION OUTPUT ;
    USE SIGNAL ;
    PORT
      LAYER M5 ;
        RECT  19.584 11.688 19.608 11.88 ;
    END
  END q[100]
  PIN q[101]
    DIRECTION OUTPUT ;
    USE SIGNAL ;
    PORT
      LAYER M5 ;
        RECT  19.776 11.688 19.8 11.88 ;
    END
  END q[101]
  PIN q[102]
    DIRECTION OUTPUT ;
    USE SIGNAL ;
    PORT
      LAYER M5 ;
        RECT  19.968 11.688 19.992 11.88 ;
    END
  END q[102]
  PIN q[103]
    DIRECTION OUTPUT ;
    USE SIGNAL ;
    PORT
      LAYER M5 ;
        RECT  20.16 11.688 20.184 11.88 ;
    END
  END q[103]
  PIN q[104]
    DIRECTION OUTPUT ;
    USE SIGNAL ;
    PORT
      LAYER M5 ;
        RECT  20.352 11.688 20.376 11.88 ;
    END
  END q[104]
  PIN q[105]
    DIRECTION OUTPUT ;
    USE SIGNAL ;
    PORT
      LAYER M5 ;
        RECT  20.544 11.688 20.568 11.88 ;
    END
  END q[105]
  PIN q[106]
    DIRECTION OUTPUT ;
    USE SIGNAL ;
    PORT
      LAYER M5 ;
        RECT  20.736 11.688 20.76 11.88 ;
    END
  END q[106]
  PIN q[107]
    DIRECTION OUTPUT ;
    USE SIGNAL ;
    PORT
      LAYER M5 ;
        RECT  20.928 11.688 20.952 11.88 ;
    END
  END q[107]
  PIN q[108]
    DIRECTION OUTPUT ;
    USE SIGNAL ;
    PORT
      LAYER M5 ;
        RECT  21.12 11.688 21.144 11.88 ;
    END
  END q[108]
  PIN q[109]
    DIRECTION OUTPUT ;
    USE SIGNAL ;
    PORT
      LAYER M5 ;
        RECT  21.312 11.688 21.336 11.88 ;
    END
  END q[109]
  PIN q[10]
    DIRECTION OUTPUT ;
    USE SIGNAL ;
    PORT
      LAYER M5 ;
        RECT  2.304 11.688 2.328 11.88 ;
    END
  END q[10]
  PIN q[110]
    DIRECTION OUTPUT ;
    USE SIGNAL ;
    PORT
      LAYER M5 ;
        RECT  21.504 11.688 21.528 11.88 ;
    END
  END q[110]
  PIN q[111]
    DIRECTION OUTPUT ;
    USE SIGNAL ;
    PORT
      LAYER M5 ;
        RECT  21.696 11.688 21.72 11.88 ;
    END
  END q[111]
  PIN q[112]
    DIRECTION OUTPUT ;
    USE SIGNAL ;
    PORT
      LAYER M5 ;
        RECT  21.888 11.688 21.912 11.88 ;
    END
  END q[112]
  PIN q[113]
    DIRECTION OUTPUT ;
    USE SIGNAL ;
    PORT
      LAYER M5 ;
        RECT  22.08 11.688 22.104 11.88 ;
    END
  END q[113]
  PIN q[114]
    DIRECTION OUTPUT ;
    USE SIGNAL ;
    PORT
      LAYER M5 ;
        RECT  22.272 11.688 22.296 11.88 ;
    END
  END q[114]
  PIN q[115]
    DIRECTION OUTPUT ;
    USE SIGNAL ;
    PORT
      LAYER M5 ;
        RECT  22.464 11.688 22.488 11.88 ;
    END
  END q[115]
  PIN q[116]
    DIRECTION OUTPUT ;
    USE SIGNAL ;
    PORT
      LAYER M5 ;
        RECT  22.656 11.688 22.68 11.88 ;
    END
  END q[116]
  PIN q[117]
    DIRECTION OUTPUT ;
    USE SIGNAL ;
    PORT
      LAYER M5 ;
        RECT  22.848 11.688 22.872 11.88 ;
    END
  END q[117]
  PIN q[118]
    DIRECTION OUTPUT ;
    USE SIGNAL ;
    PORT
      LAYER M5 ;
        RECT  23.04 11.688 23.064 11.88 ;
    END
  END q[118]
  PIN q[119]
    DIRECTION OUTPUT ;
    USE SIGNAL ;
    PORT
      LAYER M5 ;
        RECT  23.232 11.688 23.256 11.88 ;
    END
  END q[119]
  PIN q[11]
    DIRECTION OUTPUT ;
    USE SIGNAL ;
    PORT
      LAYER M5 ;
        RECT  2.496 11.688 2.52 11.88 ;
    END
  END q[11]
  PIN q[120]
    DIRECTION OUTPUT ;
    USE SIGNAL ;
    PORT
      LAYER M5 ;
        RECT  23.424 11.688 23.448 11.88 ;
    END
  END q[120]
  PIN q[121]
    DIRECTION OUTPUT ;
    USE SIGNAL ;
    PORT
      LAYER M5 ;
        RECT  23.616 11.688 23.64 11.88 ;
    END
  END q[121]
  PIN q[122]
    DIRECTION OUTPUT ;
    USE SIGNAL ;
    PORT
      LAYER M5 ;
        RECT  23.808 11.688 23.832 11.88 ;
    END
  END q[122]
  PIN q[123]
    DIRECTION OUTPUT ;
    USE SIGNAL ;
    PORT
      LAYER M5 ;
        RECT  24 11.688 24.024 11.88 ;
    END
  END q[123]
  PIN q[124]
    DIRECTION OUTPUT ;
    USE SIGNAL ;
    PORT
      LAYER M5 ;
        RECT  24.192 11.688 24.216 11.88 ;
    END
  END q[124]
  PIN q[125]
    DIRECTION OUTPUT ;
    USE SIGNAL ;
    PORT
      LAYER M5 ;
        RECT  24.384 11.688 24.408 11.88 ;
    END
  END q[125]
  PIN q[126]
    DIRECTION OUTPUT ;
    USE SIGNAL ;
    PORT
      LAYER M5 ;
        RECT  24.576 11.688 24.6 11.88 ;
    END
  END q[126]
  PIN q[127]
    DIRECTION OUTPUT ;
    USE SIGNAL ;
    PORT
      LAYER M5 ;
        RECT  24.768 11.688 24.792 11.88 ;
    END
  END q[127]
  PIN q[128]
    DIRECTION OUTPUT ;
    USE SIGNAL ;
    PORT
      LAYER M5 ;
        RECT  24.96 11.688 24.984 11.88 ;
    END
  END q[128]
  PIN q[129]
    DIRECTION OUTPUT ;
    USE SIGNAL ;
    PORT
      LAYER M5 ;
        RECT  25.152 11.688 25.176 11.88 ;
    END
  END q[129]
  PIN q[12]
    DIRECTION OUTPUT ;
    USE SIGNAL ;
    PORT
      LAYER M5 ;
        RECT  2.688 11.688 2.712 11.88 ;
    END
  END q[12]
  PIN q[130]
    DIRECTION OUTPUT ;
    USE SIGNAL ;
    PORT
      LAYER M5 ;
        RECT  25.344 11.688 25.368 11.88 ;
    END
  END q[130]
  PIN q[131]
    DIRECTION OUTPUT ;
    USE SIGNAL ;
    PORT
      LAYER M5 ;
        RECT  25.536 11.688 25.56 11.88 ;
    END
  END q[131]
  PIN q[132]
    DIRECTION OUTPUT ;
    USE SIGNAL ;
    PORT
      LAYER M5 ;
        RECT  25.728 11.688 25.752 11.88 ;
    END
  END q[132]
  PIN q[133]
    DIRECTION OUTPUT ;
    USE SIGNAL ;
    PORT
      LAYER M5 ;
        RECT  25.92 11.688 25.944 11.88 ;
    END
  END q[133]
  PIN q[134]
    DIRECTION OUTPUT ;
    USE SIGNAL ;
    PORT
      LAYER M5 ;
        RECT  26.112 11.688 26.136 11.88 ;
    END
  END q[134]
  PIN q[135]
    DIRECTION OUTPUT ;
    USE SIGNAL ;
    PORT
      LAYER M5 ;
        RECT  26.304 11.688 26.328 11.88 ;
    END
  END q[135]
  PIN q[136]
    DIRECTION OUTPUT ;
    USE SIGNAL ;
    PORT
      LAYER M5 ;
        RECT  26.496 11.688 26.52 11.88 ;
    END
  END q[136]
  PIN q[137]
    DIRECTION OUTPUT ;
    USE SIGNAL ;
    PORT
      LAYER M5 ;
        RECT  26.688 11.688 26.712 11.88 ;
    END
  END q[137]
  PIN q[138]
    DIRECTION OUTPUT ;
    USE SIGNAL ;
    PORT
      LAYER M5 ;
        RECT  26.88 11.688 26.904 11.88 ;
    END
  END q[138]
  PIN q[139]
    DIRECTION OUTPUT ;
    USE SIGNAL ;
    PORT
      LAYER M5 ;
        RECT  27.072 11.688 27.096 11.88 ;
    END
  END q[139]
  PIN q[13]
    DIRECTION OUTPUT ;
    USE SIGNAL ;
    PORT
      LAYER M5 ;
        RECT  2.88 11.688 2.904 11.88 ;
    END
  END q[13]
  PIN q[140]
    DIRECTION OUTPUT ;
    USE SIGNAL ;
    PORT
      LAYER M5 ;
        RECT  27.264 11.688 27.288 11.88 ;
    END
  END q[140]
  PIN q[141]
    DIRECTION OUTPUT ;
    USE SIGNAL ;
    PORT
      LAYER M5 ;
        RECT  27.456 11.688 27.48 11.88 ;
    END
  END q[141]
  PIN q[142]
    DIRECTION OUTPUT ;
    USE SIGNAL ;
    PORT
      LAYER M5 ;
        RECT  27.648 11.688 27.672 11.88 ;
    END
  END q[142]
  PIN q[143]
    DIRECTION OUTPUT ;
    USE SIGNAL ;
    PORT
      LAYER M5 ;
        RECT  27.84 11.688 27.864 11.88 ;
    END
  END q[143]
  PIN q[144]
    DIRECTION OUTPUT ;
    USE SIGNAL ;
    PORT
      LAYER M5 ;
        RECT  28.032 11.688 28.056 11.88 ;
    END
  END q[144]
  PIN q[145]
    DIRECTION OUTPUT ;
    USE SIGNAL ;
    PORT
      LAYER M5 ;
        RECT  28.224 11.688 28.248 11.88 ;
    END
  END q[145]
  PIN q[146]
    DIRECTION OUTPUT ;
    USE SIGNAL ;
    PORT
      LAYER M5 ;
        RECT  28.416 11.688 28.44 11.88 ;
    END
  END q[146]
  PIN q[147]
    DIRECTION OUTPUT ;
    USE SIGNAL ;
    PORT
      LAYER M5 ;
        RECT  28.608 11.688 28.632 11.88 ;
    END
  END q[147]
  PIN q[148]
    DIRECTION OUTPUT ;
    USE SIGNAL ;
    PORT
      LAYER M5 ;
        RECT  28.8 11.688 28.824 11.88 ;
    END
  END q[148]
  PIN q[149]
    DIRECTION OUTPUT ;
    USE SIGNAL ;
    PORT
      LAYER M5 ;
        RECT  28.992 11.688 29.016 11.88 ;
    END
  END q[149]
  PIN q[14]
    DIRECTION OUTPUT ;
    USE SIGNAL ;
    PORT
      LAYER M5 ;
        RECT  3.072 11.688 3.096 11.88 ;
    END
  END q[14]
  PIN q[150]
    DIRECTION OUTPUT ;
    USE SIGNAL ;
    PORT
      LAYER M5 ;
        RECT  29.184 11.688 29.208 11.88 ;
    END
  END q[150]
  PIN q[151]
    DIRECTION OUTPUT ;
    USE SIGNAL ;
    PORT
      LAYER M5 ;
        RECT  29.376 11.688 29.4 11.88 ;
    END
  END q[151]
  PIN q[152]
    DIRECTION OUTPUT ;
    USE SIGNAL ;
    PORT
      LAYER M5 ;
        RECT  29.568 11.688 29.592 11.88 ;
    END
  END q[152]
  PIN q[153]
    DIRECTION OUTPUT ;
    USE SIGNAL ;
    PORT
      LAYER M5 ;
        RECT  29.76 11.688 29.784 11.88 ;
    END
  END q[153]
  PIN q[154]
    DIRECTION OUTPUT ;
    USE SIGNAL ;
    PORT
      LAYER M5 ;
        RECT  29.952 11.688 29.976 11.88 ;
    END
  END q[154]
  PIN q[155]
    DIRECTION OUTPUT ;
    USE SIGNAL ;
    PORT
      LAYER M5 ;
        RECT  30.144 11.688 30.168 11.88 ;
    END
  END q[155]
  PIN q[156]
    DIRECTION OUTPUT ;
    USE SIGNAL ;
    PORT
      LAYER M5 ;
        RECT  30.336 11.688 30.36 11.88 ;
    END
  END q[156]
  PIN q[157]
    DIRECTION OUTPUT ;
    USE SIGNAL ;
    PORT
      LAYER M5 ;
        RECT  30.528 11.688 30.552 11.88 ;
    END
  END q[157]
  PIN q[158]
    DIRECTION OUTPUT ;
    USE SIGNAL ;
    PORT
      LAYER M5 ;
        RECT  30.72 11.688 30.744 11.88 ;
    END
  END q[158]
  PIN q[159]
    DIRECTION OUTPUT ;
    USE SIGNAL ;
    PORT
      LAYER M5 ;
        RECT  30.912 11.688 30.936 11.88 ;
    END
  END q[159]
  PIN q[15]
    DIRECTION OUTPUT ;
    USE SIGNAL ;
    PORT
      LAYER M5 ;
        RECT  3.264 11.688 3.288 11.88 ;
    END
  END q[15]
  PIN q[160]
    DIRECTION OUTPUT ;
    USE SIGNAL ;
    PORT
      LAYER M5 ;
        RECT  31.104 11.688 31.128 11.88 ;
    END
  END q[160]
  PIN q[161]
    DIRECTION OUTPUT ;
    USE SIGNAL ;
    PORT
      LAYER M5 ;
        RECT  31.296 11.688 31.32 11.88 ;
    END
  END q[161]
  PIN q[162]
    DIRECTION OUTPUT ;
    USE SIGNAL ;
    PORT
      LAYER M5 ;
        RECT  31.488 11.688 31.512 11.88 ;
    END
  END q[162]
  PIN q[163]
    DIRECTION OUTPUT ;
    USE SIGNAL ;
    PORT
      LAYER M5 ;
        RECT  31.68 11.688 31.704 11.88 ;
    END
  END q[163]
  PIN q[164]
    DIRECTION OUTPUT ;
    USE SIGNAL ;
    PORT
      LAYER M5 ;
        RECT  31.872 11.688 31.896 11.88 ;
    END
  END q[164]
  PIN q[165]
    DIRECTION OUTPUT ;
    USE SIGNAL ;
    PORT
      LAYER M5 ;
        RECT  32.064 11.688 32.088 11.88 ;
    END
  END q[165]
  PIN q[166]
    DIRECTION OUTPUT ;
    USE SIGNAL ;
    PORT
      LAYER M5 ;
        RECT  32.256 11.688 32.28 11.88 ;
    END
  END q[166]
  PIN q[167]
    DIRECTION OUTPUT ;
    USE SIGNAL ;
    PORT
      LAYER M5 ;
        RECT  32.448 11.688 32.472 11.88 ;
    END
  END q[167]
  PIN q[168]
    DIRECTION OUTPUT ;
    USE SIGNAL ;
    PORT
      LAYER M5 ;
        RECT  32.64 11.688 32.664 11.88 ;
    END
  END q[168]
  PIN q[169]
    DIRECTION OUTPUT ;
    USE SIGNAL ;
    PORT
      LAYER M5 ;
        RECT  32.832 11.688 32.856 11.88 ;
    END
  END q[169]
  PIN q[16]
    DIRECTION OUTPUT ;
    USE SIGNAL ;
    PORT
      LAYER M5 ;
        RECT  3.456 11.688 3.48 11.88 ;
    END
  END q[16]
  PIN q[170]
    DIRECTION OUTPUT ;
    USE SIGNAL ;
    PORT
      LAYER M5 ;
        RECT  33.024 11.688 33.048 11.88 ;
    END
  END q[170]
  PIN q[171]
    DIRECTION OUTPUT ;
    USE SIGNAL ;
    PORT
      LAYER M5 ;
        RECT  33.216 11.688 33.24 11.88 ;
    END
  END q[171]
  PIN q[172]
    DIRECTION OUTPUT ;
    USE SIGNAL ;
    PORT
      LAYER M5 ;
        RECT  33.408 11.688 33.432 11.88 ;
    END
  END q[172]
  PIN q[173]
    DIRECTION OUTPUT ;
    USE SIGNAL ;
    PORT
      LAYER M5 ;
        RECT  33.6 11.688 33.624 11.88 ;
    END
  END q[173]
  PIN q[174]
    DIRECTION OUTPUT ;
    USE SIGNAL ;
    PORT
      LAYER M5 ;
        RECT  33.792 11.688 33.816 11.88 ;
    END
  END q[174]
  PIN q[175]
    DIRECTION OUTPUT ;
    USE SIGNAL ;
    PORT
      LAYER M5 ;
        RECT  33.984 11.688 34.008 11.88 ;
    END
  END q[175]
  PIN q[176]
    DIRECTION OUTPUT ;
    USE SIGNAL ;
    PORT
      LAYER M5 ;
        RECT  34.176 11.688 34.2 11.88 ;
    END
  END q[176]
  PIN q[177]
    DIRECTION OUTPUT ;
    USE SIGNAL ;
    PORT
      LAYER M5 ;
        RECT  34.368 11.688 34.392 11.88 ;
    END
  END q[177]
  PIN q[178]
    DIRECTION OUTPUT ;
    USE SIGNAL ;
    PORT
      LAYER M5 ;
        RECT  34.56 11.688 34.584 11.88 ;
    END
  END q[178]
  PIN q[179]
    DIRECTION OUTPUT ;
    USE SIGNAL ;
    PORT
      LAYER M5 ;
        RECT  34.752 11.688 34.776 11.88 ;
    END
  END q[179]
  PIN q[17]
    DIRECTION OUTPUT ;
    USE SIGNAL ;
    PORT
      LAYER M5 ;
        RECT  3.648 11.688 3.672 11.88 ;
    END
  END q[17]
  PIN q[180]
    DIRECTION OUTPUT ;
    USE SIGNAL ;
    PORT
      LAYER M5 ;
        RECT  34.944 11.688 34.968 11.88 ;
    END
  END q[180]
  PIN q[181]
    DIRECTION OUTPUT ;
    USE SIGNAL ;
    PORT
      LAYER M5 ;
        RECT  35.136 11.688 35.16 11.88 ;
    END
  END q[181]
  PIN q[182]
    DIRECTION OUTPUT ;
    USE SIGNAL ;
    PORT
      LAYER M5 ;
        RECT  35.328 11.688 35.352 11.88 ;
    END
  END q[182]
  PIN q[183]
    DIRECTION OUTPUT ;
    USE SIGNAL ;
    PORT
      LAYER M5 ;
        RECT  35.52 11.688 35.544 11.88 ;
    END
  END q[183]
  PIN q[184]
    DIRECTION OUTPUT ;
    USE SIGNAL ;
    PORT
      LAYER M5 ;
        RECT  35.712 11.688 35.736 11.88 ;
    END
  END q[184]
  PIN q[185]
    DIRECTION OUTPUT ;
    USE SIGNAL ;
    PORT
      LAYER M5 ;
        RECT  35.904 11.688 35.928 11.88 ;
    END
  END q[185]
  PIN q[186]
    DIRECTION OUTPUT ;
    USE SIGNAL ;
    PORT
      LAYER M5 ;
        RECT  36.096 11.688 36.12 11.88 ;
    END
  END q[186]
  PIN q[187]
    DIRECTION OUTPUT ;
    USE SIGNAL ;
    PORT
      LAYER M5 ;
        RECT  36.288 11.688 36.312 11.88 ;
    END
  END q[187]
  PIN q[188]
    DIRECTION OUTPUT ;
    USE SIGNAL ;
    PORT
      LAYER M5 ;
        RECT  36.48 11.688 36.504 11.88 ;
    END
  END q[188]
  PIN q[189]
    DIRECTION OUTPUT ;
    USE SIGNAL ;
    PORT
      LAYER M5 ;
        RECT  36.672 11.688 36.696 11.88 ;
    END
  END q[189]
  PIN q[18]
    DIRECTION OUTPUT ;
    USE SIGNAL ;
    PORT
      LAYER M5 ;
        RECT  3.84 11.688 3.864 11.88 ;
    END
  END q[18]
  PIN q[190]
    DIRECTION OUTPUT ;
    USE SIGNAL ;
    PORT
      LAYER M5 ;
        RECT  36.864 11.688 36.888 11.88 ;
    END
  END q[190]
  PIN q[191]
    DIRECTION OUTPUT ;
    USE SIGNAL ;
    PORT
      LAYER M5 ;
        RECT  37.056 11.688 37.08 11.88 ;
    END
  END q[191]
  PIN q[192]
    DIRECTION OUTPUT ;
    USE SIGNAL ;
    PORT
      LAYER M5 ;
        RECT  37.248 11.688 37.272 11.88 ;
    END
  END q[192]
  PIN q[193]
    DIRECTION OUTPUT ;
    USE SIGNAL ;
    PORT
      LAYER M5 ;
        RECT  37.44 11.688 37.464 11.88 ;
    END
  END q[193]
  PIN q[194]
    DIRECTION OUTPUT ;
    USE SIGNAL ;
    PORT
      LAYER M5 ;
        RECT  37.632 11.688 37.656 11.88 ;
    END
  END q[194]
  PIN q[195]
    DIRECTION OUTPUT ;
    USE SIGNAL ;
    PORT
      LAYER M5 ;
        RECT  37.824 11.688 37.848 11.88 ;
    END
  END q[195]
  PIN q[196]
    DIRECTION OUTPUT ;
    USE SIGNAL ;
    PORT
      LAYER M5 ;
        RECT  38.016 11.688 38.04 11.88 ;
    END
  END q[196]
  PIN q[197]
    DIRECTION OUTPUT ;
    USE SIGNAL ;
    PORT
      LAYER M5 ;
        RECT  38.208 11.688 38.232 11.88 ;
    END
  END q[197]
  PIN q[198]
    DIRECTION OUTPUT ;
    USE SIGNAL ;
    PORT
      LAYER M5 ;
        RECT  38.4 11.688 38.424 11.88 ;
    END
  END q[198]
  PIN q[199]
    DIRECTION OUTPUT ;
    USE SIGNAL ;
    PORT
      LAYER M5 ;
        RECT  38.592 11.688 38.616 11.88 ;
    END
  END q[199]
  PIN q[19]
    DIRECTION OUTPUT ;
    USE SIGNAL ;
    PORT
      LAYER M5 ;
        RECT  4.032 11.688 4.056 11.88 ;
    END
  END q[19]
  PIN q[1]
    DIRECTION OUTPUT ;
    USE SIGNAL ;
    PORT
      LAYER M5 ;
        RECT  0.576 11.688 0.6 11.88 ;
    END
  END q[1]
  PIN q[200]
    DIRECTION OUTPUT ;
    USE SIGNAL ;
    PORT
      LAYER M5 ;
        RECT  38.784 11.688 38.808 11.88 ;
    END
  END q[200]
  PIN q[201]
    DIRECTION OUTPUT ;
    USE SIGNAL ;
    PORT
      LAYER M5 ;
        RECT  38.976 11.688 39 11.88 ;
    END
  END q[201]
  PIN q[202]
    DIRECTION OUTPUT ;
    USE SIGNAL ;
    PORT
      LAYER M5 ;
        RECT  39.168 11.688 39.192 11.88 ;
    END
  END q[202]
  PIN q[203]
    DIRECTION OUTPUT ;
    USE SIGNAL ;
    PORT
      LAYER M5 ;
        RECT  39.36 11.688 39.384 11.88 ;
    END
  END q[203]
  PIN q[204]
    DIRECTION OUTPUT ;
    USE SIGNAL ;
    PORT
      LAYER M5 ;
        RECT  39.552 11.688 39.576 11.88 ;
    END
  END q[204]
  PIN q[205]
    DIRECTION OUTPUT ;
    USE SIGNAL ;
    PORT
      LAYER M5 ;
        RECT  39.744 11.688 39.768 11.88 ;
    END
  END q[205]
  PIN q[206]
    DIRECTION OUTPUT ;
    USE SIGNAL ;
    PORT
      LAYER M5 ;
        RECT  39.936 11.688 39.96 11.88 ;
    END
  END q[206]
  PIN q[207]
    DIRECTION OUTPUT ;
    USE SIGNAL ;
    PORT
      LAYER M5 ;
        RECT  40.128 11.688 40.152 11.88 ;
    END
  END q[207]
  PIN q[208]
    DIRECTION OUTPUT ;
    USE SIGNAL ;
    PORT
      LAYER M5 ;
        RECT  40.32 11.688 40.344 11.88 ;
    END
  END q[208]
  PIN q[209]
    DIRECTION OUTPUT ;
    USE SIGNAL ;
    PORT
      LAYER M5 ;
        RECT  40.512 11.688 40.536 11.88 ;
    END
  END q[209]
  PIN q[20]
    DIRECTION OUTPUT ;
    USE SIGNAL ;
    PORT
      LAYER M5 ;
        RECT  4.224 11.688 4.248 11.88 ;
    END
  END q[20]
  PIN q[210]
    DIRECTION OUTPUT ;
    USE SIGNAL ;
    PORT
      LAYER M5 ;
        RECT  40.704 11.688 40.728 11.88 ;
    END
  END q[210]
  PIN q[211]
    DIRECTION OUTPUT ;
    USE SIGNAL ;
    PORT
      LAYER M5 ;
        RECT  40.896 11.688 40.92 11.88 ;
    END
  END q[211]
  PIN q[212]
    DIRECTION OUTPUT ;
    USE SIGNAL ;
    PORT
      LAYER M5 ;
        RECT  41.088 11.688 41.112 11.88 ;
    END
  END q[212]
  PIN q[213]
    DIRECTION OUTPUT ;
    USE SIGNAL ;
    PORT
      LAYER M5 ;
        RECT  41.28 11.688 41.304 11.88 ;
    END
  END q[213]
  PIN q[214]
    DIRECTION OUTPUT ;
    USE SIGNAL ;
    PORT
      LAYER M5 ;
        RECT  41.472 11.688 41.496 11.88 ;
    END
  END q[214]
  PIN q[215]
    DIRECTION OUTPUT ;
    USE SIGNAL ;
    PORT
      LAYER M5 ;
        RECT  41.664 11.688 41.688 11.88 ;
    END
  END q[215]
  PIN q[216]
    DIRECTION OUTPUT ;
    USE SIGNAL ;
    PORT
      LAYER M5 ;
        RECT  41.856 11.688 41.88 11.88 ;
    END
  END q[216]
  PIN q[217]
    DIRECTION OUTPUT ;
    USE SIGNAL ;
    PORT
      LAYER M5 ;
        RECT  42.048 11.688 42.072 11.88 ;
    END
  END q[217]
  PIN q[218]
    DIRECTION OUTPUT ;
    USE SIGNAL ;
    PORT
      LAYER M5 ;
        RECT  42.24 11.688 42.264 11.88 ;
    END
  END q[218]
  PIN q[219]
    DIRECTION OUTPUT ;
    USE SIGNAL ;
    PORT
      LAYER M5 ;
        RECT  42.432 11.688 42.456 11.88 ;
    END
  END q[219]
  PIN q[21]
    DIRECTION OUTPUT ;
    USE SIGNAL ;
    PORT
      LAYER M5 ;
        RECT  4.416 11.688 4.44 11.88 ;
    END
  END q[21]
  PIN q[220]
    DIRECTION OUTPUT ;
    USE SIGNAL ;
    PORT
      LAYER M5 ;
        RECT  42.624 11.688 42.648 11.88 ;
    END
  END q[220]
  PIN q[221]
    DIRECTION OUTPUT ;
    USE SIGNAL ;
    PORT
      LAYER M5 ;
        RECT  42.816 11.688 42.84 11.88 ;
    END
  END q[221]
  PIN q[222]
    DIRECTION OUTPUT ;
    USE SIGNAL ;
    PORT
      LAYER M5 ;
        RECT  43.008 11.688 43.032 11.88 ;
    END
  END q[222]
  PIN q[223]
    DIRECTION OUTPUT ;
    USE SIGNAL ;
    PORT
      LAYER M5 ;
        RECT  43.2 11.688 43.224 11.88 ;
    END
  END q[223]
  PIN q[224]
    DIRECTION OUTPUT ;
    USE SIGNAL ;
    PORT
      LAYER M5 ;
        RECT  43.392 11.688 43.416 11.88 ;
    END
  END q[224]
  PIN q[225]
    DIRECTION OUTPUT ;
    USE SIGNAL ;
    PORT
      LAYER M5 ;
        RECT  43.584 11.688 43.608 11.88 ;
    END
  END q[225]
  PIN q[226]
    DIRECTION OUTPUT ;
    USE SIGNAL ;
    PORT
      LAYER M5 ;
        RECT  43.776 11.688 43.8 11.88 ;
    END
  END q[226]
  PIN q[227]
    DIRECTION OUTPUT ;
    USE SIGNAL ;
    PORT
      LAYER M5 ;
        RECT  43.968 11.688 43.992 11.88 ;
    END
  END q[227]
  PIN q[228]
    DIRECTION OUTPUT ;
    USE SIGNAL ;
    PORT
      LAYER M5 ;
        RECT  44.16 11.688 44.184 11.88 ;
    END
  END q[228]
  PIN q[229]
    DIRECTION OUTPUT ;
    USE SIGNAL ;
    PORT
      LAYER M5 ;
        RECT  44.352 11.688 44.376 11.88 ;
    END
  END q[229]
  PIN q[22]
    DIRECTION OUTPUT ;
    USE SIGNAL ;
    PORT
      LAYER M5 ;
        RECT  4.608 11.688 4.632 11.88 ;
    END
  END q[22]
  PIN q[230]
    DIRECTION OUTPUT ;
    USE SIGNAL ;
    PORT
      LAYER M5 ;
        RECT  44.544 11.688 44.568 11.88 ;
    END
  END q[230]
  PIN q[231]
    DIRECTION OUTPUT ;
    USE SIGNAL ;
    PORT
      LAYER M5 ;
        RECT  44.736 11.688 44.76 11.88 ;
    END
  END q[231]
  PIN q[232]
    DIRECTION OUTPUT ;
    USE SIGNAL ;
    PORT
      LAYER M5 ;
        RECT  44.928 11.688 44.952 11.88 ;
    END
  END q[232]
  PIN q[233]
    DIRECTION OUTPUT ;
    USE SIGNAL ;
    PORT
      LAYER M5 ;
        RECT  45.12 11.688 45.144 11.88 ;
    END
  END q[233]
  PIN q[234]
    DIRECTION OUTPUT ;
    USE SIGNAL ;
    PORT
      LAYER M5 ;
        RECT  45.312 11.688 45.336 11.88 ;
    END
  END q[234]
  PIN q[235]
    DIRECTION OUTPUT ;
    USE SIGNAL ;
    PORT
      LAYER M5 ;
        RECT  45.504 11.688 45.528 11.88 ;
    END
  END q[235]
  PIN q[236]
    DIRECTION OUTPUT ;
    USE SIGNAL ;
    PORT
      LAYER M5 ;
        RECT  45.696 11.688 45.72 11.88 ;
    END
  END q[236]
  PIN q[237]
    DIRECTION OUTPUT ;
    USE SIGNAL ;
    PORT
      LAYER M5 ;
        RECT  45.888 11.688 45.912 11.88 ;
    END
  END q[237]
  PIN q[238]
    DIRECTION OUTPUT ;
    USE SIGNAL ;
    PORT
      LAYER M5 ;
        RECT  46.08 11.688 46.104 11.88 ;
    END
  END q[238]
  PIN q[239]
    DIRECTION OUTPUT ;
    USE SIGNAL ;
    PORT
      LAYER M5 ;
        RECT  46.272 11.688 46.296 11.88 ;
    END
  END q[239]
  PIN q[23]
    DIRECTION OUTPUT ;
    USE SIGNAL ;
    PORT
      LAYER M5 ;
        RECT  4.8 11.688 4.824 11.88 ;
    END
  END q[23]
  PIN q[240]
    DIRECTION OUTPUT ;
    USE SIGNAL ;
    PORT
      LAYER M5 ;
        RECT  46.464 11.688 46.488 11.88 ;
    END
  END q[240]
  PIN q[241]
    DIRECTION OUTPUT ;
    USE SIGNAL ;
    PORT
      LAYER M5 ;
        RECT  46.656 11.688 46.68 11.88 ;
    END
  END q[241]
  PIN q[242]
    DIRECTION OUTPUT ;
    USE SIGNAL ;
    PORT
      LAYER M5 ;
        RECT  46.848 11.688 46.872 11.88 ;
    END
  END q[242]
  PIN q[243]
    DIRECTION OUTPUT ;
    USE SIGNAL ;
    PORT
      LAYER M5 ;
        RECT  47.04 11.688 47.064 11.88 ;
    END
  END q[243]
  PIN q[244]
    DIRECTION OUTPUT ;
    USE SIGNAL ;
    PORT
      LAYER M5 ;
        RECT  47.232 11.688 47.256 11.88 ;
    END
  END q[244]
  PIN q[245]
    DIRECTION OUTPUT ;
    USE SIGNAL ;
    PORT
      LAYER M5 ;
        RECT  47.424 11.688 47.448 11.88 ;
    END
  END q[245]
  PIN q[246]
    DIRECTION OUTPUT ;
    USE SIGNAL ;
    PORT
      LAYER M5 ;
        RECT  47.616 11.688 47.64 11.88 ;
    END
  END q[246]
  PIN q[247]
    DIRECTION OUTPUT ;
    USE SIGNAL ;
    PORT
      LAYER M5 ;
        RECT  47.808 11.688 47.832 11.88 ;
    END
  END q[247]
  PIN q[248]
    DIRECTION OUTPUT ;
    USE SIGNAL ;
    PORT
      LAYER M5 ;
        RECT  48 11.688 48.024 11.88 ;
    END
  END q[248]
  PIN q[249]
    DIRECTION OUTPUT ;
    USE SIGNAL ;
    PORT
      LAYER M5 ;
        RECT  48.192 11.688 48.216 11.88 ;
    END
  END q[249]
  PIN q[24]
    DIRECTION OUTPUT ;
    USE SIGNAL ;
    PORT
      LAYER M5 ;
        RECT  4.992 11.688 5.016 11.88 ;
    END
  END q[24]
  PIN q[250]
    DIRECTION OUTPUT ;
    USE SIGNAL ;
    PORT
      LAYER M5 ;
        RECT  48.384 11.688 48.408 11.88 ;
    END
  END q[250]
  PIN q[251]
    DIRECTION OUTPUT ;
    USE SIGNAL ;
    PORT
      LAYER M5 ;
        RECT  48.576 11.688 48.6 11.88 ;
    END
  END q[251]
  PIN q[252]
    DIRECTION OUTPUT ;
    USE SIGNAL ;
    PORT
      LAYER M5 ;
        RECT  48.768 11.688 48.792 11.88 ;
    END
  END q[252]
  PIN q[253]
    DIRECTION OUTPUT ;
    USE SIGNAL ;
    PORT
      LAYER M5 ;
        RECT  48.96 11.688 48.984 11.88 ;
    END
  END q[253]
  PIN q[254]
    DIRECTION OUTPUT ;
    USE SIGNAL ;
    PORT
      LAYER M5 ;
        RECT  49.152 11.688 49.176 11.88 ;
    END
  END q[254]
  PIN q[255]
    DIRECTION OUTPUT ;
    USE SIGNAL ;
    PORT
      LAYER M5 ;
        RECT  49.344 11.688 49.368 11.88 ;
    END
  END q[255]
  PIN q[256]
    DIRECTION OUTPUT ;
    USE SIGNAL ;
    PORT
      LAYER M5 ;
        RECT  49.536 11.688 49.56 11.88 ;
    END
  END q[256]
  PIN q[257]
    DIRECTION OUTPUT ;
    USE SIGNAL ;
    PORT
      LAYER M5 ;
        RECT  49.728 11.688 49.752 11.88 ;
    END
  END q[257]
  PIN q[258]
    DIRECTION OUTPUT ;
    USE SIGNAL ;
    PORT
      LAYER M5 ;
        RECT  49.92 11.688 49.944 11.88 ;
    END
  END q[258]
  PIN q[259]
    DIRECTION OUTPUT ;
    USE SIGNAL ;
    PORT
      LAYER M5 ;
        RECT  50.112 11.688 50.136 11.88 ;
    END
  END q[259]
  PIN q[25]
    DIRECTION OUTPUT ;
    USE SIGNAL ;
    PORT
      LAYER M5 ;
        RECT  5.184 11.688 5.208 11.88 ;
    END
  END q[25]
  PIN q[260]
    DIRECTION OUTPUT ;
    USE SIGNAL ;
    PORT
      LAYER M5 ;
        RECT  50.304 11.688 50.328 11.88 ;
    END
  END q[260]
  PIN q[261]
    DIRECTION OUTPUT ;
    USE SIGNAL ;
    PORT
      LAYER M5 ;
        RECT  50.496 11.688 50.52 11.88 ;
    END
  END q[261]
  PIN q[262]
    DIRECTION OUTPUT ;
    USE SIGNAL ;
    PORT
      LAYER M5 ;
        RECT  50.688 11.688 50.712 11.88 ;
    END
  END q[262]
  PIN q[263]
    DIRECTION OUTPUT ;
    USE SIGNAL ;
    PORT
      LAYER M5 ;
        RECT  50.88 11.688 50.904 11.88 ;
    END
  END q[263]
  PIN q[264]
    DIRECTION OUTPUT ;
    USE SIGNAL ;
    PORT
      LAYER M5 ;
        RECT  51.072 11.688 51.096 11.88 ;
    END
  END q[264]
  PIN q[265]
    DIRECTION OUTPUT ;
    USE SIGNAL ;
    PORT
      LAYER M5 ;
        RECT  51.264 11.688 51.288 11.88 ;
    END
  END q[265]
  PIN q[266]
    DIRECTION OUTPUT ;
    USE SIGNAL ;
    PORT
      LAYER M5 ;
        RECT  51.456 11.688 51.48 11.88 ;
    END
  END q[266]
  PIN q[267]
    DIRECTION OUTPUT ;
    USE SIGNAL ;
    PORT
      LAYER M5 ;
        RECT  51.648 11.688 51.672 11.88 ;
    END
  END q[267]
  PIN q[268]
    DIRECTION OUTPUT ;
    USE SIGNAL ;
    PORT
      LAYER M5 ;
        RECT  51.84 11.688 51.864 11.88 ;
    END
  END q[268]
  PIN q[269]
    DIRECTION OUTPUT ;
    USE SIGNAL ;
    PORT
      LAYER M5 ;
        RECT  52.032 11.688 52.056 11.88 ;
    END
  END q[269]
  PIN q[26]
    DIRECTION OUTPUT ;
    USE SIGNAL ;
    PORT
      LAYER M5 ;
        RECT  5.376 11.688 5.4 11.88 ;
    END
  END q[26]
  PIN q[270]
    DIRECTION OUTPUT ;
    USE SIGNAL ;
    PORT
      LAYER M5 ;
        RECT  52.224 11.688 52.248 11.88 ;
    END
  END q[270]
  PIN q[271]
    DIRECTION OUTPUT ;
    USE SIGNAL ;
    PORT
      LAYER M5 ;
        RECT  52.416 11.688 52.44 11.88 ;
    END
  END q[271]
  PIN q[272]
    DIRECTION OUTPUT ;
    USE SIGNAL ;
    PORT
      LAYER M5 ;
        RECT  52.608 11.688 52.632 11.88 ;
    END
  END q[272]
  PIN q[273]
    DIRECTION OUTPUT ;
    USE SIGNAL ;
    PORT
      LAYER M5 ;
        RECT  52.8 11.688 52.824 11.88 ;
    END
  END q[273]
  PIN q[274]
    DIRECTION OUTPUT ;
    USE SIGNAL ;
    PORT
      LAYER M5 ;
        RECT  52.992 11.688 53.016 11.88 ;
    END
  END q[274]
  PIN q[275]
    DIRECTION OUTPUT ;
    USE SIGNAL ;
    PORT
      LAYER M5 ;
        RECT  53.184 11.688 53.208 11.88 ;
    END
  END q[275]
  PIN q[276]
    DIRECTION OUTPUT ;
    USE SIGNAL ;
    PORT
      LAYER M5 ;
        RECT  53.376 11.688 53.4 11.88 ;
    END
  END q[276]
  PIN q[277]
    DIRECTION OUTPUT ;
    USE SIGNAL ;
    PORT
      LAYER M5 ;
        RECT  53.568 11.688 53.592 11.88 ;
    END
  END q[277]
  PIN q[278]
    DIRECTION OUTPUT ;
    USE SIGNAL ;
    PORT
      LAYER M5 ;
        RECT  53.76 11.688 53.784 11.88 ;
    END
  END q[278]
  PIN q[279]
    DIRECTION OUTPUT ;
    USE SIGNAL ;
    PORT
      LAYER M5 ;
        RECT  53.952 11.688 53.976 11.88 ;
    END
  END q[279]
  PIN q[27]
    DIRECTION OUTPUT ;
    USE SIGNAL ;
    PORT
      LAYER M5 ;
        RECT  5.568 11.688 5.592 11.88 ;
    END
  END q[27]
  PIN q[280]
    DIRECTION OUTPUT ;
    USE SIGNAL ;
    PORT
      LAYER M5 ;
        RECT  54.144 11.688 54.168 11.88 ;
    END
  END q[280]
  PIN q[281]
    DIRECTION OUTPUT ;
    USE SIGNAL ;
    PORT
      LAYER M5 ;
        RECT  54.336 11.688 54.36 11.88 ;
    END
  END q[281]
  PIN q[282]
    DIRECTION OUTPUT ;
    USE SIGNAL ;
    PORT
      LAYER M5 ;
        RECT  54.528 11.688 54.552 11.88 ;
    END
  END q[282]
  PIN q[283]
    DIRECTION OUTPUT ;
    USE SIGNAL ;
    PORT
      LAYER M5 ;
        RECT  54.72 11.688 54.744 11.88 ;
    END
  END q[283]
  PIN q[284]
    DIRECTION OUTPUT ;
    USE SIGNAL ;
    PORT
      LAYER M5 ;
        RECT  54.912 11.688 54.936 11.88 ;
    END
  END q[284]
  PIN q[285]
    DIRECTION OUTPUT ;
    USE SIGNAL ;
    PORT
      LAYER M5 ;
        RECT  55.104 11.688 55.128 11.88 ;
    END
  END q[285]
  PIN q[286]
    DIRECTION OUTPUT ;
    USE SIGNAL ;
    PORT
      LAYER M5 ;
        RECT  55.296 11.688 55.32 11.88 ;
    END
  END q[286]
  PIN q[287]
    DIRECTION OUTPUT ;
    USE SIGNAL ;
    PORT
      LAYER M5 ;
        RECT  55.488 11.688 55.512 11.88 ;
    END
  END q[287]
  PIN q[288]
    DIRECTION OUTPUT ;
    USE SIGNAL ;
    PORT
      LAYER M5 ;
        RECT  55.68 11.688 55.704 11.88 ;
    END
  END q[288]
  PIN q[289]
    DIRECTION OUTPUT ;
    USE SIGNAL ;
    PORT
      LAYER M5 ;
        RECT  55.872 11.688 55.896 11.88 ;
    END
  END q[289]
  PIN q[28]
    DIRECTION OUTPUT ;
    USE SIGNAL ;
    PORT
      LAYER M5 ;
        RECT  5.76 11.688 5.784 11.88 ;
    END
  END q[28]
  PIN q[290]
    DIRECTION OUTPUT ;
    USE SIGNAL ;
    PORT
      LAYER M5 ;
        RECT  56.064 11.688 56.088 11.88 ;
    END
  END q[290]
  PIN q[291]
    DIRECTION OUTPUT ;
    USE SIGNAL ;
    PORT
      LAYER M5 ;
        RECT  56.256 11.688 56.28 11.88 ;
    END
  END q[291]
  PIN q[292]
    DIRECTION OUTPUT ;
    USE SIGNAL ;
    PORT
      LAYER M5 ;
        RECT  56.448 11.688 56.472 11.88 ;
    END
  END q[292]
  PIN q[293]
    DIRECTION OUTPUT ;
    USE SIGNAL ;
    PORT
      LAYER M5 ;
        RECT  56.64 11.688 56.664 11.88 ;
    END
  END q[293]
  PIN q[294]
    DIRECTION OUTPUT ;
    USE SIGNAL ;
    PORT
      LAYER M5 ;
        RECT  56.832 11.688 56.856 11.88 ;
    END
  END q[294]
  PIN q[295]
    DIRECTION OUTPUT ;
    USE SIGNAL ;
    PORT
      LAYER M5 ;
        RECT  57.024 11.688 57.048 11.88 ;
    END
  END q[295]
  PIN q[296]
    DIRECTION OUTPUT ;
    USE SIGNAL ;
    PORT
      LAYER M5 ;
        RECT  57.216 11.688 57.24 11.88 ;
    END
  END q[296]
  PIN q[297]
    DIRECTION OUTPUT ;
    USE SIGNAL ;
    PORT
      LAYER M5 ;
        RECT  57.408 11.688 57.432 11.88 ;
    END
  END q[297]
  PIN q[298]
    DIRECTION OUTPUT ;
    USE SIGNAL ;
    PORT
      LAYER M5 ;
        RECT  57.6 11.688 57.624 11.88 ;
    END
  END q[298]
  PIN q[299]
    DIRECTION OUTPUT ;
    USE SIGNAL ;
    PORT
      LAYER M5 ;
        RECT  57.792 11.688 57.816 11.88 ;
    END
  END q[299]
  PIN q[29]
    DIRECTION OUTPUT ;
    USE SIGNAL ;
    PORT
      LAYER M5 ;
        RECT  5.952 11.688 5.976 11.88 ;
    END
  END q[29]
  PIN q[2]
    DIRECTION OUTPUT ;
    USE SIGNAL ;
    PORT
      LAYER M5 ;
        RECT  0.768 11.688 0.792 11.88 ;
    END
  END q[2]
  PIN q[300]
    DIRECTION OUTPUT ;
    USE SIGNAL ;
    PORT
      LAYER M5 ;
        RECT  57.984 11.688 58.008 11.88 ;
    END
  END q[300]
  PIN q[301]
    DIRECTION OUTPUT ;
    USE SIGNAL ;
    PORT
      LAYER M5 ;
        RECT  58.176 11.688 58.2 11.88 ;
    END
  END q[301]
  PIN q[302]
    DIRECTION OUTPUT ;
    USE SIGNAL ;
    PORT
      LAYER M5 ;
        RECT  58.368 11.688 58.392 11.88 ;
    END
  END q[302]
  PIN q[303]
    DIRECTION OUTPUT ;
    USE SIGNAL ;
    PORT
      LAYER M5 ;
        RECT  58.56 11.688 58.584 11.88 ;
    END
  END q[303]
  PIN q[304]
    DIRECTION OUTPUT ;
    USE SIGNAL ;
    PORT
      LAYER M5 ;
        RECT  58.752 11.688 58.776 11.88 ;
    END
  END q[304]
  PIN q[305]
    DIRECTION OUTPUT ;
    USE SIGNAL ;
    PORT
      LAYER M5 ;
        RECT  58.944 11.688 58.968 11.88 ;
    END
  END q[305]
  PIN q[306]
    DIRECTION OUTPUT ;
    USE SIGNAL ;
    PORT
      LAYER M5 ;
        RECT  59.136 11.688 59.16 11.88 ;
    END
  END q[306]
  PIN q[307]
    DIRECTION OUTPUT ;
    USE SIGNAL ;
    PORT
      LAYER M5 ;
        RECT  59.328 11.688 59.352 11.88 ;
    END
  END q[307]
  PIN q[308]
    DIRECTION OUTPUT ;
    USE SIGNAL ;
    PORT
      LAYER M5 ;
        RECT  59.52 11.688 59.544 11.88 ;
    END
  END q[308]
  PIN q[309]
    DIRECTION OUTPUT ;
    USE SIGNAL ;
    PORT
      LAYER M5 ;
        RECT  59.712 11.688 59.736 11.88 ;
    END
  END q[309]
  PIN q[30]
    DIRECTION OUTPUT ;
    USE SIGNAL ;
    PORT
      LAYER M5 ;
        RECT  6.144 11.688 6.168 11.88 ;
    END
  END q[30]
  PIN q[310]
    DIRECTION OUTPUT ;
    USE SIGNAL ;
    PORT
      LAYER M5 ;
        RECT  59.904 11.688 59.928 11.88 ;
    END
  END q[310]
  PIN q[311]
    DIRECTION OUTPUT ;
    USE SIGNAL ;
    PORT
      LAYER M5 ;
        RECT  60.096 11.688 60.12 11.88 ;
    END
  END q[311]
  PIN q[312]
    DIRECTION OUTPUT ;
    USE SIGNAL ;
    PORT
      LAYER M5 ;
        RECT  60.288 11.688 60.312 11.88 ;
    END
  END q[312]
  PIN q[313]
    DIRECTION OUTPUT ;
    USE SIGNAL ;
    PORT
      LAYER M5 ;
        RECT  60.48 11.688 60.504 11.88 ;
    END
  END q[313]
  PIN q[314]
    DIRECTION OUTPUT ;
    USE SIGNAL ;
    PORT
      LAYER M5 ;
        RECT  60.672 11.688 60.696 11.88 ;
    END
  END q[314]
  PIN q[315]
    DIRECTION OUTPUT ;
    USE SIGNAL ;
    PORT
      LAYER M5 ;
        RECT  60.864 11.688 60.888 11.88 ;
    END
  END q[315]
  PIN q[316]
    DIRECTION OUTPUT ;
    USE SIGNAL ;
    PORT
      LAYER M5 ;
        RECT  61.056 11.688 61.08 11.88 ;
    END
  END q[316]
  PIN q[317]
    DIRECTION OUTPUT ;
    USE SIGNAL ;
    PORT
      LAYER M5 ;
        RECT  61.248 11.688 61.272 11.88 ;
    END
  END q[317]
  PIN q[318]
    DIRECTION OUTPUT ;
    USE SIGNAL ;
    PORT
      LAYER M5 ;
        RECT  61.44 11.688 61.464 11.88 ;
    END
  END q[318]
  PIN q[319]
    DIRECTION OUTPUT ;
    USE SIGNAL ;
    PORT
      LAYER M5 ;
        RECT  61.632 11.688 61.656 11.88 ;
    END
  END q[319]
  PIN q[31]
    DIRECTION OUTPUT ;
    USE SIGNAL ;
    PORT
      LAYER M5 ;
        RECT  6.336 11.688 6.36 11.88 ;
    END
  END q[31]
  PIN q[320]
    DIRECTION OUTPUT ;
    USE SIGNAL ;
    PORT
      LAYER M5 ;
        RECT  61.824 11.688 61.848 11.88 ;
    END
  END q[320]
  PIN q[321]
    DIRECTION OUTPUT ;
    USE SIGNAL ;
    PORT
      LAYER M5 ;
        RECT  62.016 11.688 62.04 11.88 ;
    END
  END q[321]
  PIN q[322]
    DIRECTION OUTPUT ;
    USE SIGNAL ;
    PORT
      LAYER M5 ;
        RECT  62.208 11.688 62.232 11.88 ;
    END
  END q[322]
  PIN q[323]
    DIRECTION OUTPUT ;
    USE SIGNAL ;
    PORT
      LAYER M5 ;
        RECT  62.4 11.688 62.424 11.88 ;
    END
  END q[323]
  PIN q[324]
    DIRECTION OUTPUT ;
    USE SIGNAL ;
    PORT
      LAYER M5 ;
        RECT  62.592 11.688 62.616 11.88 ;
    END
  END q[324]
  PIN q[325]
    DIRECTION OUTPUT ;
    USE SIGNAL ;
    PORT
      LAYER M5 ;
        RECT  62.784 11.688 62.808 11.88 ;
    END
  END q[325]
  PIN q[326]
    DIRECTION OUTPUT ;
    USE SIGNAL ;
    PORT
      LAYER M5 ;
        RECT  62.976 11.688 63 11.88 ;
    END
  END q[326]
  PIN q[327]
    DIRECTION OUTPUT ;
    USE SIGNAL ;
    PORT
      LAYER M5 ;
        RECT  63.168 11.688 63.192 11.88 ;
    END
  END q[327]
  PIN q[328]
    DIRECTION OUTPUT ;
    USE SIGNAL ;
    PORT
      LAYER M5 ;
        RECT  63.36 11.688 63.384 11.88 ;
    END
  END q[328]
  PIN q[329]
    DIRECTION OUTPUT ;
    USE SIGNAL ;
    PORT
      LAYER M5 ;
        RECT  63.552 11.688 63.576 11.88 ;
    END
  END q[329]
  PIN q[32]
    DIRECTION OUTPUT ;
    USE SIGNAL ;
    PORT
      LAYER M5 ;
        RECT  6.528 11.688 6.552 11.88 ;
    END
  END q[32]
  PIN q[330]
    DIRECTION OUTPUT ;
    USE SIGNAL ;
    PORT
      LAYER M5 ;
        RECT  63.744 11.688 63.768 11.88 ;
    END
  END q[330]
  PIN q[331]
    DIRECTION OUTPUT ;
    USE SIGNAL ;
    PORT
      LAYER M5 ;
        RECT  63.936 11.688 63.96 11.88 ;
    END
  END q[331]
  PIN q[332]
    DIRECTION OUTPUT ;
    USE SIGNAL ;
    PORT
      LAYER M5 ;
        RECT  64.128 11.688 64.152 11.88 ;
    END
  END q[332]
  PIN q[333]
    DIRECTION OUTPUT ;
    USE SIGNAL ;
    PORT
      LAYER M5 ;
        RECT  64.32 11.688 64.344 11.88 ;
    END
  END q[333]
  PIN q[334]
    DIRECTION OUTPUT ;
    USE SIGNAL ;
    PORT
      LAYER M5 ;
        RECT  64.512 11.688 64.536 11.88 ;
    END
  END q[334]
  PIN q[335]
    DIRECTION OUTPUT ;
    USE SIGNAL ;
    PORT
      LAYER M5 ;
        RECT  64.704 11.688 64.728 11.88 ;
    END
  END q[335]
  PIN q[336]
    DIRECTION OUTPUT ;
    USE SIGNAL ;
    PORT
      LAYER M5 ;
        RECT  64.896 11.688 64.92 11.88 ;
    END
  END q[336]
  PIN q[337]
    DIRECTION OUTPUT ;
    USE SIGNAL ;
    PORT
      LAYER M5 ;
        RECT  65.088 11.688 65.112 11.88 ;
    END
  END q[337]
  PIN q[338]
    DIRECTION OUTPUT ;
    USE SIGNAL ;
    PORT
      LAYER M5 ;
        RECT  65.28 11.688 65.304 11.88 ;
    END
  END q[338]
  PIN q[339]
    DIRECTION OUTPUT ;
    USE SIGNAL ;
    PORT
      LAYER M5 ;
        RECT  65.472 11.688 65.496 11.88 ;
    END
  END q[339]
  PIN q[33]
    DIRECTION OUTPUT ;
    USE SIGNAL ;
    PORT
      LAYER M5 ;
        RECT  6.72 11.688 6.744 11.88 ;
    END
  END q[33]
  PIN q[340]
    DIRECTION OUTPUT ;
    USE SIGNAL ;
    PORT
      LAYER M5 ;
        RECT  65.664 11.688 65.688 11.88 ;
    END
  END q[340]
  PIN q[341]
    DIRECTION OUTPUT ;
    USE SIGNAL ;
    PORT
      LAYER M5 ;
        RECT  65.856 11.688 65.88 11.88 ;
    END
  END q[341]
  PIN q[342]
    DIRECTION OUTPUT ;
    USE SIGNAL ;
    PORT
      LAYER M5 ;
        RECT  66.048 11.688 66.072 11.88 ;
    END
  END q[342]
  PIN q[343]
    DIRECTION OUTPUT ;
    USE SIGNAL ;
    PORT
      LAYER M5 ;
        RECT  66.24 11.688 66.264 11.88 ;
    END
  END q[343]
  PIN q[344]
    DIRECTION OUTPUT ;
    USE SIGNAL ;
    PORT
      LAYER M5 ;
        RECT  66.432 11.688 66.456 11.88 ;
    END
  END q[344]
  PIN q[345]
    DIRECTION OUTPUT ;
    USE SIGNAL ;
    PORT
      LAYER M5 ;
        RECT  66.624 11.688 66.648 11.88 ;
    END
  END q[345]
  PIN q[346]
    DIRECTION OUTPUT ;
    USE SIGNAL ;
    PORT
      LAYER M5 ;
        RECT  66.816 11.688 66.84 11.88 ;
    END
  END q[346]
  PIN q[347]
    DIRECTION OUTPUT ;
    USE SIGNAL ;
    PORT
      LAYER M5 ;
        RECT  67.008 11.688 67.032 11.88 ;
    END
  END q[347]
  PIN q[348]
    DIRECTION OUTPUT ;
    USE SIGNAL ;
    PORT
      LAYER M5 ;
        RECT  67.2 11.688 67.224 11.88 ;
    END
  END q[348]
  PIN q[349]
    DIRECTION OUTPUT ;
    USE SIGNAL ;
    PORT
      LAYER M5 ;
        RECT  67.392 11.688 67.416 11.88 ;
    END
  END q[349]
  PIN q[34]
    DIRECTION OUTPUT ;
    USE SIGNAL ;
    PORT
      LAYER M5 ;
        RECT  6.912 11.688 6.936 11.88 ;
    END
  END q[34]
  PIN q[350]
    DIRECTION OUTPUT ;
    USE SIGNAL ;
    PORT
      LAYER M5 ;
        RECT  67.584 11.688 67.608 11.88 ;
    END
  END q[350]
  PIN q[351]
    DIRECTION OUTPUT ;
    USE SIGNAL ;
    PORT
      LAYER M5 ;
        RECT  67.776 11.688 67.8 11.88 ;
    END
  END q[351]
  PIN q[352]
    DIRECTION OUTPUT ;
    USE SIGNAL ;
    PORT
      LAYER M5 ;
        RECT  67.968 11.688 67.992 11.88 ;
    END
  END q[352]
  PIN q[353]
    DIRECTION OUTPUT ;
    USE SIGNAL ;
    PORT
      LAYER M5 ;
        RECT  68.16 11.688 68.184 11.88 ;
    END
  END q[353]
  PIN q[354]
    DIRECTION OUTPUT ;
    USE SIGNAL ;
    PORT
      LAYER M5 ;
        RECT  68.352 11.688 68.376 11.88 ;
    END
  END q[354]
  PIN q[355]
    DIRECTION OUTPUT ;
    USE SIGNAL ;
    PORT
      LAYER M5 ;
        RECT  68.544 11.688 68.568 11.88 ;
    END
  END q[355]
  PIN q[356]
    DIRECTION OUTPUT ;
    USE SIGNAL ;
    PORT
      LAYER M5 ;
        RECT  68.736 11.688 68.76 11.88 ;
    END
  END q[356]
  PIN q[357]
    DIRECTION OUTPUT ;
    USE SIGNAL ;
    PORT
      LAYER M5 ;
        RECT  68.928 11.688 68.952 11.88 ;
    END
  END q[357]
  PIN q[358]
    DIRECTION OUTPUT ;
    USE SIGNAL ;
    PORT
      LAYER M5 ;
        RECT  69.12 11.688 69.144 11.88 ;
    END
  END q[358]
  PIN q[359]
    DIRECTION OUTPUT ;
    USE SIGNAL ;
    PORT
      LAYER M5 ;
        RECT  69.312 11.688 69.336 11.88 ;
    END
  END q[359]
  PIN q[35]
    DIRECTION OUTPUT ;
    USE SIGNAL ;
    PORT
      LAYER M5 ;
        RECT  7.104 11.688 7.128 11.88 ;
    END
  END q[35]
  PIN q[360]
    DIRECTION OUTPUT ;
    USE SIGNAL ;
    PORT
      LAYER M5 ;
        RECT  69.504 11.688 69.528 11.88 ;
    END
  END q[360]
  PIN q[361]
    DIRECTION OUTPUT ;
    USE SIGNAL ;
    PORT
      LAYER M5 ;
        RECT  69.696 11.688 69.72 11.88 ;
    END
  END q[361]
  PIN q[362]
    DIRECTION OUTPUT ;
    USE SIGNAL ;
    PORT
      LAYER M5 ;
        RECT  69.888 11.688 69.912 11.88 ;
    END
  END q[362]
  PIN q[363]
    DIRECTION OUTPUT ;
    USE SIGNAL ;
    PORT
      LAYER M5 ;
        RECT  70.08 11.688 70.104 11.88 ;
    END
  END q[363]
  PIN q[364]
    DIRECTION OUTPUT ;
    USE SIGNAL ;
    PORT
      LAYER M5 ;
        RECT  70.272 11.688 70.296 11.88 ;
    END
  END q[364]
  PIN q[365]
    DIRECTION OUTPUT ;
    USE SIGNAL ;
    PORT
      LAYER M5 ;
        RECT  70.464 11.688 70.488 11.88 ;
    END
  END q[365]
  PIN q[366]
    DIRECTION OUTPUT ;
    USE SIGNAL ;
    PORT
      LAYER M5 ;
        RECT  70.656 11.688 70.68 11.88 ;
    END
  END q[366]
  PIN q[367]
    DIRECTION OUTPUT ;
    USE SIGNAL ;
    PORT
      LAYER M5 ;
        RECT  70.848 11.688 70.872 11.88 ;
    END
  END q[367]
  PIN q[368]
    DIRECTION OUTPUT ;
    USE SIGNAL ;
    PORT
      LAYER M5 ;
        RECT  71.04 11.688 71.064 11.88 ;
    END
  END q[368]
  PIN q[369]
    DIRECTION OUTPUT ;
    USE SIGNAL ;
    PORT
      LAYER M5 ;
        RECT  71.232 11.688 71.256 11.88 ;
    END
  END q[369]
  PIN q[36]
    DIRECTION OUTPUT ;
    USE SIGNAL ;
    PORT
      LAYER M5 ;
        RECT  7.296 11.688 7.32 11.88 ;
    END
  END q[36]
  PIN q[370]
    DIRECTION OUTPUT ;
    USE SIGNAL ;
    PORT
      LAYER M5 ;
        RECT  71.424 11.688 71.448 11.88 ;
    END
  END q[370]
  PIN q[371]
    DIRECTION OUTPUT ;
    USE SIGNAL ;
    PORT
      LAYER M5 ;
        RECT  71.616 11.688 71.64 11.88 ;
    END
  END q[371]
  PIN q[372]
    DIRECTION OUTPUT ;
    USE SIGNAL ;
    PORT
      LAYER M5 ;
        RECT  71.808 11.688 71.832 11.88 ;
    END
  END q[372]
  PIN q[373]
    DIRECTION OUTPUT ;
    USE SIGNAL ;
    PORT
      LAYER M5 ;
        RECT  72 11.688 72.024 11.88 ;
    END
  END q[373]
  PIN q[374]
    DIRECTION OUTPUT ;
    USE SIGNAL ;
    PORT
      LAYER M5 ;
        RECT  72.192 11.688 72.216 11.88 ;
    END
  END q[374]
  PIN q[375]
    DIRECTION OUTPUT ;
    USE SIGNAL ;
    PORT
      LAYER M5 ;
        RECT  72.384 11.688 72.408 11.88 ;
    END
  END q[375]
  PIN q[376]
    DIRECTION OUTPUT ;
    USE SIGNAL ;
    PORT
      LAYER M5 ;
        RECT  72.576 11.688 72.6 11.88 ;
    END
  END q[376]
  PIN q[377]
    DIRECTION OUTPUT ;
    USE SIGNAL ;
    PORT
      LAYER M5 ;
        RECT  72.768 11.688 72.792 11.88 ;
    END
  END q[377]
  PIN q[378]
    DIRECTION OUTPUT ;
    USE SIGNAL ;
    PORT
      LAYER M5 ;
        RECT  72.96 11.688 72.984 11.88 ;
    END
  END q[378]
  PIN q[379]
    DIRECTION OUTPUT ;
    USE SIGNAL ;
    PORT
      LAYER M5 ;
        RECT  73.152 11.688 73.176 11.88 ;
    END
  END q[379]
  PIN q[37]
    DIRECTION OUTPUT ;
    USE SIGNAL ;
    PORT
      LAYER M5 ;
        RECT  7.488 11.688 7.512 11.88 ;
    END
  END q[37]
  PIN q[380]
    DIRECTION OUTPUT ;
    USE SIGNAL ;
    PORT
      LAYER M5 ;
        RECT  73.344 11.688 73.368 11.88 ;
    END
  END q[380]
  PIN q[381]
    DIRECTION OUTPUT ;
    USE SIGNAL ;
    PORT
      LAYER M5 ;
        RECT  73.536 11.688 73.56 11.88 ;
    END
  END q[381]
  PIN q[382]
    DIRECTION OUTPUT ;
    USE SIGNAL ;
    PORT
      LAYER M5 ;
        RECT  73.728 11.688 73.752 11.88 ;
    END
  END q[382]
  PIN q[383]
    DIRECTION OUTPUT ;
    USE SIGNAL ;
    PORT
      LAYER M5 ;
        RECT  73.92 11.688 73.944 11.88 ;
    END
  END q[383]
  PIN q[384]
    DIRECTION OUTPUT ;
    USE SIGNAL ;
    PORT
      LAYER M5 ;
        RECT  74.112 11.688 74.136 11.88 ;
    END
  END q[384]
  PIN q[385]
    DIRECTION OUTPUT ;
    USE SIGNAL ;
    PORT
      LAYER M5 ;
        RECT  74.304 11.688 74.328 11.88 ;
    END
  END q[385]
  PIN q[386]
    DIRECTION OUTPUT ;
    USE SIGNAL ;
    PORT
      LAYER M5 ;
        RECT  74.496 11.688 74.52 11.88 ;
    END
  END q[386]
  PIN q[387]
    DIRECTION OUTPUT ;
    USE SIGNAL ;
    PORT
      LAYER M5 ;
        RECT  74.688 11.688 74.712 11.88 ;
    END
  END q[387]
  PIN q[388]
    DIRECTION OUTPUT ;
    USE SIGNAL ;
    PORT
      LAYER M5 ;
        RECT  74.88 11.688 74.904 11.88 ;
    END
  END q[388]
  PIN q[389]
    DIRECTION OUTPUT ;
    USE SIGNAL ;
    PORT
      LAYER M5 ;
        RECT  75.072 11.688 75.096 11.88 ;
    END
  END q[389]
  PIN q[38]
    DIRECTION OUTPUT ;
    USE SIGNAL ;
    PORT
      LAYER M5 ;
        RECT  7.68 11.688 7.704 11.88 ;
    END
  END q[38]
  PIN q[390]
    DIRECTION OUTPUT ;
    USE SIGNAL ;
    PORT
      LAYER M5 ;
        RECT  75.264 11.688 75.288 11.88 ;
    END
  END q[390]
  PIN q[391]
    DIRECTION OUTPUT ;
    USE SIGNAL ;
    PORT
      LAYER M5 ;
        RECT  75.456 11.688 75.48 11.88 ;
    END
  END q[391]
  PIN q[392]
    DIRECTION OUTPUT ;
    USE SIGNAL ;
    PORT
      LAYER M5 ;
        RECT  75.648 11.688 75.672 11.88 ;
    END
  END q[392]
  PIN q[393]
    DIRECTION OUTPUT ;
    USE SIGNAL ;
    PORT
      LAYER M5 ;
        RECT  75.84 11.688 75.864 11.88 ;
    END
  END q[393]
  PIN q[394]
    DIRECTION OUTPUT ;
    USE SIGNAL ;
    PORT
      LAYER M5 ;
        RECT  76.032 11.688 76.056 11.88 ;
    END
  END q[394]
  PIN q[395]
    DIRECTION OUTPUT ;
    USE SIGNAL ;
    PORT
      LAYER M5 ;
        RECT  76.224 11.688 76.248 11.88 ;
    END
  END q[395]
  PIN q[396]
    DIRECTION OUTPUT ;
    USE SIGNAL ;
    PORT
      LAYER M5 ;
        RECT  76.416 11.688 76.44 11.88 ;
    END
  END q[396]
  PIN q[397]
    DIRECTION OUTPUT ;
    USE SIGNAL ;
    PORT
      LAYER M5 ;
        RECT  76.608 11.688 76.632 11.88 ;
    END
  END q[397]
  PIN q[398]
    DIRECTION OUTPUT ;
    USE SIGNAL ;
    PORT
      LAYER M5 ;
        RECT  76.8 11.688 76.824 11.88 ;
    END
  END q[398]
  PIN q[399]
    DIRECTION OUTPUT ;
    USE SIGNAL ;
    PORT
      LAYER M5 ;
        RECT  76.992 11.688 77.016 11.88 ;
    END
  END q[399]
  PIN q[39]
    DIRECTION OUTPUT ;
    USE SIGNAL ;
    PORT
      LAYER M5 ;
        RECT  7.872 11.688 7.896 11.88 ;
    END
  END q[39]
  PIN q[3]
    DIRECTION OUTPUT ;
    USE SIGNAL ;
    PORT
      LAYER M5 ;
        RECT  0.96 11.688 0.984 11.88 ;
    END
  END q[3]
  PIN q[400]
    DIRECTION OUTPUT ;
    USE SIGNAL ;
    PORT
      LAYER M5 ;
        RECT  77.184 11.688 77.208 11.88 ;
    END
  END q[400]
  PIN q[401]
    DIRECTION OUTPUT ;
    USE SIGNAL ;
    PORT
      LAYER M5 ;
        RECT  77.376 11.688 77.4 11.88 ;
    END
  END q[401]
  PIN q[402]
    DIRECTION OUTPUT ;
    USE SIGNAL ;
    PORT
      LAYER M5 ;
        RECT  77.568 11.688 77.592 11.88 ;
    END
  END q[402]
  PIN q[403]
    DIRECTION OUTPUT ;
    USE SIGNAL ;
    PORT
      LAYER M5 ;
        RECT  77.76 11.688 77.784 11.88 ;
    END
  END q[403]
  PIN q[404]
    DIRECTION OUTPUT ;
    USE SIGNAL ;
    PORT
      LAYER M5 ;
        RECT  77.952 11.688 77.976 11.88 ;
    END
  END q[404]
  PIN q[405]
    DIRECTION OUTPUT ;
    USE SIGNAL ;
    PORT
      LAYER M5 ;
        RECT  78.144 11.688 78.168 11.88 ;
    END
  END q[405]
  PIN q[406]
    DIRECTION OUTPUT ;
    USE SIGNAL ;
    PORT
      LAYER M5 ;
        RECT  78.336 11.688 78.36 11.88 ;
    END
  END q[406]
  PIN q[407]
    DIRECTION OUTPUT ;
    USE SIGNAL ;
    PORT
      LAYER M5 ;
        RECT  78.528 11.688 78.552 11.88 ;
    END
  END q[407]
  PIN q[408]
    DIRECTION OUTPUT ;
    USE SIGNAL ;
    PORT
      LAYER M5 ;
        RECT  78.72 11.688 78.744 11.88 ;
    END
  END q[408]
  PIN q[409]
    DIRECTION OUTPUT ;
    USE SIGNAL ;
    PORT
      LAYER M5 ;
        RECT  78.912 11.688 78.936 11.88 ;
    END
  END q[409]
  PIN q[40]
    DIRECTION OUTPUT ;
    USE SIGNAL ;
    PORT
      LAYER M5 ;
        RECT  8.064 11.688 8.088 11.88 ;
    END
  END q[40]
  PIN q[410]
    DIRECTION OUTPUT ;
    USE SIGNAL ;
    PORT
      LAYER M5 ;
        RECT  79.104 11.688 79.128 11.88 ;
    END
  END q[410]
  PIN q[411]
    DIRECTION OUTPUT ;
    USE SIGNAL ;
    PORT
      LAYER M5 ;
        RECT  79.296 11.688 79.32 11.88 ;
    END
  END q[411]
  PIN q[412]
    DIRECTION OUTPUT ;
    USE SIGNAL ;
    PORT
      LAYER M5 ;
        RECT  79.488 11.688 79.512 11.88 ;
    END
  END q[412]
  PIN q[413]
    DIRECTION OUTPUT ;
    USE SIGNAL ;
    PORT
      LAYER M5 ;
        RECT  79.68 11.688 79.704 11.88 ;
    END
  END q[413]
  PIN q[414]
    DIRECTION OUTPUT ;
    USE SIGNAL ;
    PORT
      LAYER M5 ;
        RECT  79.872 11.688 79.896 11.88 ;
    END
  END q[414]
  PIN q[415]
    DIRECTION OUTPUT ;
    USE SIGNAL ;
    PORT
      LAYER M5 ;
        RECT  80.064 11.688 80.088 11.88 ;
    END
  END q[415]
  PIN q[416]
    DIRECTION OUTPUT ;
    USE SIGNAL ;
    PORT
      LAYER M5 ;
        RECT  80.256 11.688 80.28 11.88 ;
    END
  END q[416]
  PIN q[417]
    DIRECTION OUTPUT ;
    USE SIGNAL ;
    PORT
      LAYER M5 ;
        RECT  80.448 11.688 80.472 11.88 ;
    END
  END q[417]
  PIN q[418]
    DIRECTION OUTPUT ;
    USE SIGNAL ;
    PORT
      LAYER M5 ;
        RECT  80.64 11.688 80.664 11.88 ;
    END
  END q[418]
  PIN q[419]
    DIRECTION OUTPUT ;
    USE SIGNAL ;
    PORT
      LAYER M5 ;
        RECT  80.832 11.688 80.856 11.88 ;
    END
  END q[419]
  PIN q[41]
    DIRECTION OUTPUT ;
    USE SIGNAL ;
    PORT
      LAYER M5 ;
        RECT  8.256 11.688 8.28 11.88 ;
    END
  END q[41]
  PIN q[420]
    DIRECTION OUTPUT ;
    USE SIGNAL ;
    PORT
      LAYER M5 ;
        RECT  81.024 11.688 81.048 11.88 ;
    END
  END q[420]
  PIN q[421]
    DIRECTION OUTPUT ;
    USE SIGNAL ;
    PORT
      LAYER M5 ;
        RECT  81.216 11.688 81.24 11.88 ;
    END
  END q[421]
  PIN q[422]
    DIRECTION OUTPUT ;
    USE SIGNAL ;
    PORT
      LAYER M5 ;
        RECT  81.408 11.688 81.432 11.88 ;
    END
  END q[422]
  PIN q[423]
    DIRECTION OUTPUT ;
    USE SIGNAL ;
    PORT
      LAYER M5 ;
        RECT  81.6 11.688 81.624 11.88 ;
    END
  END q[423]
  PIN q[424]
    DIRECTION OUTPUT ;
    USE SIGNAL ;
    PORT
      LAYER M5 ;
        RECT  81.792 11.688 81.816 11.88 ;
    END
  END q[424]
  PIN q[425]
    DIRECTION OUTPUT ;
    USE SIGNAL ;
    PORT
      LAYER M5 ;
        RECT  81.984 11.688 82.008 11.88 ;
    END
  END q[425]
  PIN q[426]
    DIRECTION OUTPUT ;
    USE SIGNAL ;
    PORT
      LAYER M5 ;
        RECT  82.176 11.688 82.2 11.88 ;
    END
  END q[426]
  PIN q[427]
    DIRECTION OUTPUT ;
    USE SIGNAL ;
    PORT
      LAYER M5 ;
        RECT  82.368 11.688 82.392 11.88 ;
    END
  END q[427]
  PIN q[428]
    DIRECTION OUTPUT ;
    USE SIGNAL ;
    PORT
      LAYER M5 ;
        RECT  82.56 11.688 82.584 11.88 ;
    END
  END q[428]
  PIN q[429]
    DIRECTION OUTPUT ;
    USE SIGNAL ;
    PORT
      LAYER M5 ;
        RECT  82.752 11.688 82.776 11.88 ;
    END
  END q[429]
  PIN q[42]
    DIRECTION OUTPUT ;
    USE SIGNAL ;
    PORT
      LAYER M5 ;
        RECT  8.448 11.688 8.472 11.88 ;
    END
  END q[42]
  PIN q[430]
    DIRECTION OUTPUT ;
    USE SIGNAL ;
    PORT
      LAYER M5 ;
        RECT  82.944 11.688 82.968 11.88 ;
    END
  END q[430]
  PIN q[431]
    DIRECTION OUTPUT ;
    USE SIGNAL ;
    PORT
      LAYER M5 ;
        RECT  83.136 11.688 83.16 11.88 ;
    END
  END q[431]
  PIN q[432]
    DIRECTION OUTPUT ;
    USE SIGNAL ;
    PORT
      LAYER M5 ;
        RECT  83.328 11.688 83.352 11.88 ;
    END
  END q[432]
  PIN q[433]
    DIRECTION OUTPUT ;
    USE SIGNAL ;
    PORT
      LAYER M5 ;
        RECT  83.52 11.688 83.544 11.88 ;
    END
  END q[433]
  PIN q[434]
    DIRECTION OUTPUT ;
    USE SIGNAL ;
    PORT
      LAYER M5 ;
        RECT  83.712 11.688 83.736 11.88 ;
    END
  END q[434]
  PIN q[435]
    DIRECTION OUTPUT ;
    USE SIGNAL ;
    PORT
      LAYER M5 ;
        RECT  83.904 11.688 83.928 11.88 ;
    END
  END q[435]
  PIN q[436]
    DIRECTION OUTPUT ;
    USE SIGNAL ;
    PORT
      LAYER M5 ;
        RECT  84.096 11.688 84.12 11.88 ;
    END
  END q[436]
  PIN q[437]
    DIRECTION OUTPUT ;
    USE SIGNAL ;
    PORT
      LAYER M5 ;
        RECT  84.288 11.688 84.312 11.88 ;
    END
  END q[437]
  PIN q[438]
    DIRECTION OUTPUT ;
    USE SIGNAL ;
    PORT
      LAYER M5 ;
        RECT  84.48 11.688 84.504 11.88 ;
    END
  END q[438]
  PIN q[439]
    DIRECTION OUTPUT ;
    USE SIGNAL ;
    PORT
      LAYER M5 ;
        RECT  84.672 11.688 84.696 11.88 ;
    END
  END q[439]
  PIN q[43]
    DIRECTION OUTPUT ;
    USE SIGNAL ;
    PORT
      LAYER M5 ;
        RECT  8.64 11.688 8.664 11.88 ;
    END
  END q[43]
  PIN q[440]
    DIRECTION OUTPUT ;
    USE SIGNAL ;
    PORT
      LAYER M5 ;
        RECT  84.864 11.688 84.888 11.88 ;
    END
  END q[440]
  PIN q[441]
    DIRECTION OUTPUT ;
    USE SIGNAL ;
    PORT
      LAYER M5 ;
        RECT  85.056 11.688 85.08 11.88 ;
    END
  END q[441]
  PIN q[442]
    DIRECTION OUTPUT ;
    USE SIGNAL ;
    PORT
      LAYER M5 ;
        RECT  85.248 11.688 85.272 11.88 ;
    END
  END q[442]
  PIN q[443]
    DIRECTION OUTPUT ;
    USE SIGNAL ;
    PORT
      LAYER M5 ;
        RECT  85.44 11.688 85.464 11.88 ;
    END
  END q[443]
  PIN q[444]
    DIRECTION OUTPUT ;
    USE SIGNAL ;
    PORT
      LAYER M5 ;
        RECT  85.632 11.688 85.656 11.88 ;
    END
  END q[444]
  PIN q[445]
    DIRECTION OUTPUT ;
    USE SIGNAL ;
    PORT
      LAYER M5 ;
        RECT  85.824 11.688 85.848 11.88 ;
    END
  END q[445]
  PIN q[446]
    DIRECTION OUTPUT ;
    USE SIGNAL ;
    PORT
      LAYER M5 ;
        RECT  86.016 11.688 86.04 11.88 ;
    END
  END q[446]
  PIN q[447]
    DIRECTION OUTPUT ;
    USE SIGNAL ;
    PORT
      LAYER M5 ;
        RECT  86.208 11.688 86.232 11.88 ;
    END
  END q[447]
  PIN q[448]
    DIRECTION OUTPUT ;
    USE SIGNAL ;
    PORT
      LAYER M5 ;
        RECT  86.4 11.688 86.424 11.88 ;
    END
  END q[448]
  PIN q[449]
    DIRECTION OUTPUT ;
    USE SIGNAL ;
    PORT
      LAYER M5 ;
        RECT  86.592 11.688 86.616 11.88 ;
    END
  END q[449]
  PIN q[44]
    DIRECTION OUTPUT ;
    USE SIGNAL ;
    PORT
      LAYER M5 ;
        RECT  8.832 11.688 8.856 11.88 ;
    END
  END q[44]
  PIN q[450]
    DIRECTION OUTPUT ;
    USE SIGNAL ;
    PORT
      LAYER M5 ;
        RECT  86.784 11.688 86.808 11.88 ;
    END
  END q[450]
  PIN q[451]
    DIRECTION OUTPUT ;
    USE SIGNAL ;
    PORT
      LAYER M5 ;
        RECT  86.976 11.688 87 11.88 ;
    END
  END q[451]
  PIN q[452]
    DIRECTION OUTPUT ;
    USE SIGNAL ;
    PORT
      LAYER M5 ;
        RECT  87.168 11.688 87.192 11.88 ;
    END
  END q[452]
  PIN q[453]
    DIRECTION OUTPUT ;
    USE SIGNAL ;
    PORT
      LAYER M5 ;
        RECT  87.36 11.688 87.384 11.88 ;
    END
  END q[453]
  PIN q[454]
    DIRECTION OUTPUT ;
    USE SIGNAL ;
    PORT
      LAYER M5 ;
        RECT  87.552 11.688 87.576 11.88 ;
    END
  END q[454]
  PIN q[455]
    DIRECTION OUTPUT ;
    USE SIGNAL ;
    PORT
      LAYER M5 ;
        RECT  87.744 11.688 87.768 11.88 ;
    END
  END q[455]
  PIN q[456]
    DIRECTION OUTPUT ;
    USE SIGNAL ;
    PORT
      LAYER M5 ;
        RECT  87.936 11.688 87.96 11.88 ;
    END
  END q[456]
  PIN q[457]
    DIRECTION OUTPUT ;
    USE SIGNAL ;
    PORT
      LAYER M5 ;
        RECT  88.128 11.688 88.152 11.88 ;
    END
  END q[457]
  PIN q[458]
    DIRECTION OUTPUT ;
    USE SIGNAL ;
    PORT
      LAYER M5 ;
        RECT  88.32 11.688 88.344 11.88 ;
    END
  END q[458]
  PIN q[459]
    DIRECTION OUTPUT ;
    USE SIGNAL ;
    PORT
      LAYER M5 ;
        RECT  88.512 11.688 88.536 11.88 ;
    END
  END q[459]
  PIN q[45]
    DIRECTION OUTPUT ;
    USE SIGNAL ;
    PORT
      LAYER M5 ;
        RECT  9.024 11.688 9.048 11.88 ;
    END
  END q[45]
  PIN q[460]
    DIRECTION OUTPUT ;
    USE SIGNAL ;
    PORT
      LAYER M5 ;
        RECT  88.704 11.688 88.728 11.88 ;
    END
  END q[460]
  PIN q[461]
    DIRECTION OUTPUT ;
    USE SIGNAL ;
    PORT
      LAYER M5 ;
        RECT  88.896 11.688 88.92 11.88 ;
    END
  END q[461]
  PIN q[462]
    DIRECTION OUTPUT ;
    USE SIGNAL ;
    PORT
      LAYER M5 ;
        RECT  89.088 11.688 89.112 11.88 ;
    END
  END q[462]
  PIN q[463]
    DIRECTION OUTPUT ;
    USE SIGNAL ;
    PORT
      LAYER M5 ;
        RECT  89.28 11.688 89.304 11.88 ;
    END
  END q[463]
  PIN q[464]
    DIRECTION OUTPUT ;
    USE SIGNAL ;
    PORT
      LAYER M5 ;
        RECT  89.472 11.688 89.496 11.88 ;
    END
  END q[464]
  PIN q[465]
    DIRECTION OUTPUT ;
    USE SIGNAL ;
    PORT
      LAYER M5 ;
        RECT  89.664 11.688 89.688 11.88 ;
    END
  END q[465]
  PIN q[466]
    DIRECTION OUTPUT ;
    USE SIGNAL ;
    PORT
      LAYER M5 ;
        RECT  89.856 11.688 89.88 11.88 ;
    END
  END q[466]
  PIN q[467]
    DIRECTION OUTPUT ;
    USE SIGNAL ;
    PORT
      LAYER M5 ;
        RECT  90.048 11.688 90.072 11.88 ;
    END
  END q[467]
  PIN q[468]
    DIRECTION OUTPUT ;
    USE SIGNAL ;
    PORT
      LAYER M5 ;
        RECT  90.24 11.688 90.264 11.88 ;
    END
  END q[468]
  PIN q[469]
    DIRECTION OUTPUT ;
    USE SIGNAL ;
    PORT
      LAYER M5 ;
        RECT  90.432 11.688 90.456 11.88 ;
    END
  END q[469]
  PIN q[46]
    DIRECTION OUTPUT ;
    USE SIGNAL ;
    PORT
      LAYER M5 ;
        RECT  9.216 11.688 9.24 11.88 ;
    END
  END q[46]
  PIN q[470]
    DIRECTION OUTPUT ;
    USE SIGNAL ;
    PORT
      LAYER M5 ;
        RECT  90.624 11.688 90.648 11.88 ;
    END
  END q[470]
  PIN q[471]
    DIRECTION OUTPUT ;
    USE SIGNAL ;
    PORT
      LAYER M5 ;
        RECT  90.816 11.688 90.84 11.88 ;
    END
  END q[471]
  PIN q[472]
    DIRECTION OUTPUT ;
    USE SIGNAL ;
    PORT
      LAYER M5 ;
        RECT  91.008 11.688 91.032 11.88 ;
    END
  END q[472]
  PIN q[473]
    DIRECTION OUTPUT ;
    USE SIGNAL ;
    PORT
      LAYER M5 ;
        RECT  91.2 11.688 91.224 11.88 ;
    END
  END q[473]
  PIN q[474]
    DIRECTION OUTPUT ;
    USE SIGNAL ;
    PORT
      LAYER M5 ;
        RECT  91.392 11.688 91.416 11.88 ;
    END
  END q[474]
  PIN q[475]
    DIRECTION OUTPUT ;
    USE SIGNAL ;
    PORT
      LAYER M5 ;
        RECT  91.584 11.688 91.608 11.88 ;
    END
  END q[475]
  PIN q[476]
    DIRECTION OUTPUT ;
    USE SIGNAL ;
    PORT
      LAYER M5 ;
        RECT  91.776 11.688 91.8 11.88 ;
    END
  END q[476]
  PIN q[477]
    DIRECTION OUTPUT ;
    USE SIGNAL ;
    PORT
      LAYER M5 ;
        RECT  91.968 11.688 91.992 11.88 ;
    END
  END q[477]
  PIN q[478]
    DIRECTION OUTPUT ;
    USE SIGNAL ;
    PORT
      LAYER M5 ;
        RECT  92.16 11.688 92.184 11.88 ;
    END
  END q[478]
  PIN q[479]
    DIRECTION OUTPUT ;
    USE SIGNAL ;
    PORT
      LAYER M5 ;
        RECT  92.352 11.688 92.376 11.88 ;
    END
  END q[479]
  PIN q[47]
    DIRECTION OUTPUT ;
    USE SIGNAL ;
    PORT
      LAYER M5 ;
        RECT  9.408 11.688 9.432 11.88 ;
    END
  END q[47]
  PIN q[480]
    DIRECTION OUTPUT ;
    USE SIGNAL ;
    PORT
      LAYER M5 ;
        RECT  92.544 11.688 92.568 11.88 ;
    END
  END q[480]
  PIN q[481]
    DIRECTION OUTPUT ;
    USE SIGNAL ;
    PORT
      LAYER M5 ;
        RECT  92.736 11.688 92.76 11.88 ;
    END
  END q[481]
  PIN q[482]
    DIRECTION OUTPUT ;
    USE SIGNAL ;
    PORT
      LAYER M5 ;
        RECT  92.928 11.688 92.952 11.88 ;
    END
  END q[482]
  PIN q[483]
    DIRECTION OUTPUT ;
    USE SIGNAL ;
    PORT
      LAYER M5 ;
        RECT  93.12 11.688 93.144 11.88 ;
    END
  END q[483]
  PIN q[484]
    DIRECTION OUTPUT ;
    USE SIGNAL ;
    PORT
      LAYER M5 ;
        RECT  93.312 11.688 93.336 11.88 ;
    END
  END q[484]
  PIN q[485]
    DIRECTION OUTPUT ;
    USE SIGNAL ;
    PORT
      LAYER M5 ;
        RECT  93.504 11.688 93.528 11.88 ;
    END
  END q[485]
  PIN q[486]
    DIRECTION OUTPUT ;
    USE SIGNAL ;
    PORT
      LAYER M5 ;
        RECT  93.696 11.688 93.72 11.88 ;
    END
  END q[486]
  PIN q[487]
    DIRECTION OUTPUT ;
    USE SIGNAL ;
    PORT
      LAYER M5 ;
        RECT  93.888 11.688 93.912 11.88 ;
    END
  END q[487]
  PIN q[488]
    DIRECTION OUTPUT ;
    USE SIGNAL ;
    PORT
      LAYER M5 ;
        RECT  94.08 11.688 94.104 11.88 ;
    END
  END q[488]
  PIN q[489]
    DIRECTION OUTPUT ;
    USE SIGNAL ;
    PORT
      LAYER M5 ;
        RECT  94.272 11.688 94.296 11.88 ;
    END
  END q[489]
  PIN q[48]
    DIRECTION OUTPUT ;
    USE SIGNAL ;
    PORT
      LAYER M5 ;
        RECT  9.6 11.688 9.624 11.88 ;
    END
  END q[48]
  PIN q[490]
    DIRECTION OUTPUT ;
    USE SIGNAL ;
    PORT
      LAYER M5 ;
        RECT  94.464 11.688 94.488 11.88 ;
    END
  END q[490]
  PIN q[491]
    DIRECTION OUTPUT ;
    USE SIGNAL ;
    PORT
      LAYER M5 ;
        RECT  94.656 11.688 94.68 11.88 ;
    END
  END q[491]
  PIN q[492]
    DIRECTION OUTPUT ;
    USE SIGNAL ;
    PORT
      LAYER M5 ;
        RECT  94.848 11.688 94.872 11.88 ;
    END
  END q[492]
  PIN q[493]
    DIRECTION OUTPUT ;
    USE SIGNAL ;
    PORT
      LAYER M5 ;
        RECT  95.04 11.688 95.064 11.88 ;
    END
  END q[493]
  PIN q[494]
    DIRECTION OUTPUT ;
    USE SIGNAL ;
    PORT
      LAYER M5 ;
        RECT  95.232 11.688 95.256 11.88 ;
    END
  END q[494]
  PIN q[495]
    DIRECTION OUTPUT ;
    USE SIGNAL ;
    PORT
      LAYER M5 ;
        RECT  95.424 11.688 95.448 11.88 ;
    END
  END q[495]
  PIN q[496]
    DIRECTION OUTPUT ;
    USE SIGNAL ;
    PORT
      LAYER M5 ;
        RECT  95.616 11.688 95.64 11.88 ;
    END
  END q[496]
  PIN q[497]
    DIRECTION OUTPUT ;
    USE SIGNAL ;
    PORT
      LAYER M5 ;
        RECT  95.808 11.688 95.832 11.88 ;
    END
  END q[497]
  PIN q[498]
    DIRECTION OUTPUT ;
    USE SIGNAL ;
    PORT
      LAYER M5 ;
        RECT  96 11.688 96.024 11.88 ;
    END
  END q[498]
  PIN q[499]
    DIRECTION OUTPUT ;
    USE SIGNAL ;
    PORT
      LAYER M5 ;
        RECT  96.192 11.688 96.216 11.88 ;
    END
  END q[499]
  PIN q[49]
    DIRECTION OUTPUT ;
    USE SIGNAL ;
    PORT
      LAYER M5 ;
        RECT  9.792 11.688 9.816 11.88 ;
    END
  END q[49]
  PIN q[4]
    DIRECTION OUTPUT ;
    USE SIGNAL ;
    PORT
      LAYER M5 ;
        RECT  1.152 11.688 1.176 11.88 ;
    END
  END q[4]
  PIN q[500]
    DIRECTION OUTPUT ;
    USE SIGNAL ;
    PORT
      LAYER M5 ;
        RECT  96.384 11.688 96.408 11.88 ;
    END
  END q[500]
  PIN q[501]
    DIRECTION OUTPUT ;
    USE SIGNAL ;
    PORT
      LAYER M5 ;
        RECT  96.576 11.688 96.6 11.88 ;
    END
  END q[501]
  PIN q[502]
    DIRECTION OUTPUT ;
    USE SIGNAL ;
    PORT
      LAYER M5 ;
        RECT  96.768 11.688 96.792 11.88 ;
    END
  END q[502]
  PIN q[503]
    DIRECTION OUTPUT ;
    USE SIGNAL ;
    PORT
      LAYER M5 ;
        RECT  96.96 11.688 96.984 11.88 ;
    END
  END q[503]
  PIN q[504]
    DIRECTION OUTPUT ;
    USE SIGNAL ;
    PORT
      LAYER M5 ;
        RECT  97.152 11.688 97.176 11.88 ;
    END
  END q[504]
  PIN q[505]
    DIRECTION OUTPUT ;
    USE SIGNAL ;
    PORT
      LAYER M5 ;
        RECT  97.344 11.688 97.368 11.88 ;
    END
  END q[505]
  PIN q[506]
    DIRECTION OUTPUT ;
    USE SIGNAL ;
    PORT
      LAYER M5 ;
        RECT  97.536 11.688 97.56 11.88 ;
    END
  END q[506]
  PIN q[507]
    DIRECTION OUTPUT ;
    USE SIGNAL ;
    PORT
      LAYER M5 ;
        RECT  97.728 11.688 97.752 11.88 ;
    END
  END q[507]
  PIN q[508]
    DIRECTION OUTPUT ;
    USE SIGNAL ;
    PORT
      LAYER M5 ;
        RECT  97.92 11.688 97.944 11.88 ;
    END
  END q[508]
  PIN q[509]
    DIRECTION OUTPUT ;
    USE SIGNAL ;
    PORT
      LAYER M5 ;
        RECT  98.112 11.688 98.136 11.88 ;
    END
  END q[509]
  PIN q[50]
    DIRECTION OUTPUT ;
    USE SIGNAL ;
    PORT
      LAYER M5 ;
        RECT  9.984 11.688 10.008 11.88 ;
    END
  END q[50]
  PIN q[510]
    DIRECTION OUTPUT ;
    USE SIGNAL ;
    PORT
      LAYER M5 ;
        RECT  98.304 11.688 98.328 11.88 ;
    END
  END q[510]
  PIN q[511]
    DIRECTION OUTPUT ;
    USE SIGNAL ;
    PORT
      LAYER M5 ;
        RECT  98.496 11.688 98.52 11.88 ;
    END
  END q[511]
  PIN q[512]
    DIRECTION OUTPUT ;
    USE SIGNAL ;
    PORT
      LAYER M5 ;
        RECT  98.688 11.688 98.712 11.88 ;
    END
  END q[512]
  PIN q[513]
    DIRECTION OUTPUT ;
    USE SIGNAL ;
    PORT
      LAYER M5 ;
        RECT  98.88 11.688 98.904 11.88 ;
    END
  END q[513]
  PIN q[514]
    DIRECTION OUTPUT ;
    USE SIGNAL ;
    PORT
      LAYER M5 ;
        RECT  99.072 11.688 99.096 11.88 ;
    END
  END q[514]
  PIN q[515]
    DIRECTION OUTPUT ;
    USE SIGNAL ;
    PORT
      LAYER M5 ;
        RECT  99.264 11.688 99.288 11.88 ;
    END
  END q[515]
  PIN q[516]
    DIRECTION OUTPUT ;
    USE SIGNAL ;
    PORT
      LAYER M5 ;
        RECT  99.456 11.688 99.48 11.88 ;
    END
  END q[516]
  PIN q[517]
    DIRECTION OUTPUT ;
    USE SIGNAL ;
    PORT
      LAYER M5 ;
        RECT  99.648 11.688 99.672 11.88 ;
    END
  END q[517]
  PIN q[518]
    DIRECTION OUTPUT ;
    USE SIGNAL ;
    PORT
      LAYER M5 ;
        RECT  99.84 11.688 99.864 11.88 ;
    END
  END q[518]
  PIN q[519]
    DIRECTION OUTPUT ;
    USE SIGNAL ;
    PORT
      LAYER M5 ;
        RECT  100.032 11.688 100.056 11.88 ;
    END
  END q[519]
  PIN q[51]
    DIRECTION OUTPUT ;
    USE SIGNAL ;
    PORT
      LAYER M5 ;
        RECT  10.176 11.688 10.2 11.88 ;
    END
  END q[51]
  PIN q[520]
    DIRECTION OUTPUT ;
    USE SIGNAL ;
    PORT
      LAYER M5 ;
        RECT  100.224 11.688 100.248 11.88 ;
    END
  END q[520]
  PIN q[521]
    DIRECTION OUTPUT ;
    USE SIGNAL ;
    PORT
      LAYER M5 ;
        RECT  100.416 11.688 100.44 11.88 ;
    END
  END q[521]
  PIN q[522]
    DIRECTION OUTPUT ;
    USE SIGNAL ;
    PORT
      LAYER M5 ;
        RECT  100.608 11.688 100.632 11.88 ;
    END
  END q[522]
  PIN q[523]
    DIRECTION OUTPUT ;
    USE SIGNAL ;
    PORT
      LAYER M5 ;
        RECT  100.8 11.688 100.824 11.88 ;
    END
  END q[523]
  PIN q[524]
    DIRECTION OUTPUT ;
    USE SIGNAL ;
    PORT
      LAYER M5 ;
        RECT  100.992 11.688 101.016 11.88 ;
    END
  END q[524]
  PIN q[525]
    DIRECTION OUTPUT ;
    USE SIGNAL ;
    PORT
      LAYER M5 ;
        RECT  101.184 11.688 101.208 11.88 ;
    END
  END q[525]
  PIN q[526]
    DIRECTION OUTPUT ;
    USE SIGNAL ;
    PORT
      LAYER M5 ;
        RECT  101.376 11.688 101.4 11.88 ;
    END
  END q[526]
  PIN q[527]
    DIRECTION OUTPUT ;
    USE SIGNAL ;
    PORT
      LAYER M5 ;
        RECT  101.568 11.688 101.592 11.88 ;
    END
  END q[527]
  PIN q[528]
    DIRECTION OUTPUT ;
    USE SIGNAL ;
    PORT
      LAYER M5 ;
        RECT  101.76 11.688 101.784 11.88 ;
    END
  END q[528]
  PIN q[529]
    DIRECTION OUTPUT ;
    USE SIGNAL ;
    PORT
      LAYER M5 ;
        RECT  101.952 11.688 101.976 11.88 ;
    END
  END q[529]
  PIN q[52]
    DIRECTION OUTPUT ;
    USE SIGNAL ;
    PORT
      LAYER M5 ;
        RECT  10.368 11.688 10.392 11.88 ;
    END
  END q[52]
  PIN q[530]
    DIRECTION OUTPUT ;
    USE SIGNAL ;
    PORT
      LAYER M5 ;
        RECT  102.144 11.688 102.168 11.88 ;
    END
  END q[530]
  PIN q[531]
    DIRECTION OUTPUT ;
    USE SIGNAL ;
    PORT
      LAYER M5 ;
        RECT  102.336 11.688 102.36 11.88 ;
    END
  END q[531]
  PIN q[532]
    DIRECTION OUTPUT ;
    USE SIGNAL ;
    PORT
      LAYER M5 ;
        RECT  102.528 11.688 102.552 11.88 ;
    END
  END q[532]
  PIN q[533]
    DIRECTION OUTPUT ;
    USE SIGNAL ;
    PORT
      LAYER M5 ;
        RECT  102.72 11.688 102.744 11.88 ;
    END
  END q[533]
  PIN q[534]
    DIRECTION OUTPUT ;
    USE SIGNAL ;
    PORT
      LAYER M5 ;
        RECT  102.912 11.688 102.936 11.88 ;
    END
  END q[534]
  PIN q[535]
    DIRECTION OUTPUT ;
    USE SIGNAL ;
    PORT
      LAYER M5 ;
        RECT  103.104 11.688 103.128 11.88 ;
    END
  END q[535]
  PIN q[536]
    DIRECTION OUTPUT ;
    USE SIGNAL ;
    PORT
      LAYER M5 ;
        RECT  103.296 11.688 103.32 11.88 ;
    END
  END q[536]
  PIN q[537]
    DIRECTION OUTPUT ;
    USE SIGNAL ;
    PORT
      LAYER M5 ;
        RECT  103.488 11.688 103.512 11.88 ;
    END
  END q[537]
  PIN q[538]
    DIRECTION OUTPUT ;
    USE SIGNAL ;
    PORT
      LAYER M5 ;
        RECT  103.68 11.688 103.704 11.88 ;
    END
  END q[538]
  PIN q[539]
    DIRECTION OUTPUT ;
    USE SIGNAL ;
    PORT
      LAYER M5 ;
        RECT  103.872 11.688 103.896 11.88 ;
    END
  END q[539]
  PIN q[53]
    DIRECTION OUTPUT ;
    USE SIGNAL ;
    PORT
      LAYER M5 ;
        RECT  10.56 11.688 10.584 11.88 ;
    END
  END q[53]
  PIN q[540]
    DIRECTION OUTPUT ;
    USE SIGNAL ;
    PORT
      LAYER M5 ;
        RECT  104.064 11.688 104.088 11.88 ;
    END
  END q[540]
  PIN q[541]
    DIRECTION OUTPUT ;
    USE SIGNAL ;
    PORT
      LAYER M5 ;
        RECT  104.256 11.688 104.28 11.88 ;
    END
  END q[541]
  PIN q[542]
    DIRECTION OUTPUT ;
    USE SIGNAL ;
    PORT
      LAYER M5 ;
        RECT  104.448 11.688 104.472 11.88 ;
    END
  END q[542]
  PIN q[543]
    DIRECTION OUTPUT ;
    USE SIGNAL ;
    PORT
      LAYER M5 ;
        RECT  104.64 11.688 104.664 11.88 ;
    END
  END q[543]
  PIN q[54]
    DIRECTION OUTPUT ;
    USE SIGNAL ;
    PORT
      LAYER M5 ;
        RECT  10.752 11.688 10.776 11.88 ;
    END
  END q[54]
  PIN q[55]
    DIRECTION OUTPUT ;
    USE SIGNAL ;
    PORT
      LAYER M5 ;
        RECT  10.944 11.688 10.968 11.88 ;
    END
  END q[55]
  PIN q[56]
    DIRECTION OUTPUT ;
    USE SIGNAL ;
    PORT
      LAYER M5 ;
        RECT  11.136 11.688 11.16 11.88 ;
    END
  END q[56]
  PIN q[57]
    DIRECTION OUTPUT ;
    USE SIGNAL ;
    PORT
      LAYER M5 ;
        RECT  11.328 11.688 11.352 11.88 ;
    END
  END q[57]
  PIN q[58]
    DIRECTION OUTPUT ;
    USE SIGNAL ;
    PORT
      LAYER M5 ;
        RECT  11.52 11.688 11.544 11.88 ;
    END
  END q[58]
  PIN q[59]
    DIRECTION OUTPUT ;
    USE SIGNAL ;
    PORT
      LAYER M5 ;
        RECT  11.712 11.688 11.736 11.88 ;
    END
  END q[59]
  PIN q[5]
    DIRECTION OUTPUT ;
    USE SIGNAL ;
    PORT
      LAYER M5 ;
        RECT  1.344 11.688 1.368 11.88 ;
    END
  END q[5]
  PIN q[60]
    DIRECTION OUTPUT ;
    USE SIGNAL ;
    PORT
      LAYER M5 ;
        RECT  11.904 11.688 11.928 11.88 ;
    END
  END q[60]
  PIN q[61]
    DIRECTION OUTPUT ;
    USE SIGNAL ;
    PORT
      LAYER M5 ;
        RECT  12.096 11.688 12.12 11.88 ;
    END
  END q[61]
  PIN q[62]
    DIRECTION OUTPUT ;
    USE SIGNAL ;
    PORT
      LAYER M5 ;
        RECT  12.288 11.688 12.312 11.88 ;
    END
  END q[62]
  PIN q[63]
    DIRECTION OUTPUT ;
    USE SIGNAL ;
    PORT
      LAYER M5 ;
        RECT  12.48 11.688 12.504 11.88 ;
    END
  END q[63]
  PIN q[64]
    DIRECTION OUTPUT ;
    USE SIGNAL ;
    PORT
      LAYER M5 ;
        RECT  12.672 11.688 12.696 11.88 ;
    END
  END q[64]
  PIN q[65]
    DIRECTION OUTPUT ;
    USE SIGNAL ;
    PORT
      LAYER M5 ;
        RECT  12.864 11.688 12.888 11.88 ;
    END
  END q[65]
  PIN q[66]
    DIRECTION OUTPUT ;
    USE SIGNAL ;
    PORT
      LAYER M5 ;
        RECT  13.056 11.688 13.08 11.88 ;
    END
  END q[66]
  PIN q[67]
    DIRECTION OUTPUT ;
    USE SIGNAL ;
    PORT
      LAYER M5 ;
        RECT  13.248 11.688 13.272 11.88 ;
    END
  END q[67]
  PIN q[68]
    DIRECTION OUTPUT ;
    USE SIGNAL ;
    PORT
      LAYER M5 ;
        RECT  13.44 11.688 13.464 11.88 ;
    END
  END q[68]
  PIN q[69]
    DIRECTION OUTPUT ;
    USE SIGNAL ;
    PORT
      LAYER M5 ;
        RECT  13.632 11.688 13.656 11.88 ;
    END
  END q[69]
  PIN q[6]
    DIRECTION OUTPUT ;
    USE SIGNAL ;
    PORT
      LAYER M5 ;
        RECT  1.536 11.688 1.56 11.88 ;
    END
  END q[6]
  PIN q[70]
    DIRECTION OUTPUT ;
    USE SIGNAL ;
    PORT
      LAYER M5 ;
        RECT  13.824 11.688 13.848 11.88 ;
    END
  END q[70]
  PIN q[71]
    DIRECTION OUTPUT ;
    USE SIGNAL ;
    PORT
      LAYER M5 ;
        RECT  14.016 11.688 14.04 11.88 ;
    END
  END q[71]
  PIN q[72]
    DIRECTION OUTPUT ;
    USE SIGNAL ;
    PORT
      LAYER M5 ;
        RECT  14.208 11.688 14.232 11.88 ;
    END
  END q[72]
  PIN q[73]
    DIRECTION OUTPUT ;
    USE SIGNAL ;
    PORT
      LAYER M5 ;
        RECT  14.4 11.688 14.424 11.88 ;
    END
  END q[73]
  PIN q[74]
    DIRECTION OUTPUT ;
    USE SIGNAL ;
    PORT
      LAYER M5 ;
        RECT  14.592 11.688 14.616 11.88 ;
    END
  END q[74]
  PIN q[75]
    DIRECTION OUTPUT ;
    USE SIGNAL ;
    PORT
      LAYER M5 ;
        RECT  14.784 11.688 14.808 11.88 ;
    END
  END q[75]
  PIN q[76]
    DIRECTION OUTPUT ;
    USE SIGNAL ;
    PORT
      LAYER M5 ;
        RECT  14.976 11.688 15 11.88 ;
    END
  END q[76]
  PIN q[77]
    DIRECTION OUTPUT ;
    USE SIGNAL ;
    PORT
      LAYER M5 ;
        RECT  15.168 11.688 15.192 11.88 ;
    END
  END q[77]
  PIN q[78]
    DIRECTION OUTPUT ;
    USE SIGNAL ;
    PORT
      LAYER M5 ;
        RECT  15.36 11.688 15.384 11.88 ;
    END
  END q[78]
  PIN q[79]
    DIRECTION OUTPUT ;
    USE SIGNAL ;
    PORT
      LAYER M5 ;
        RECT  15.552 11.688 15.576 11.88 ;
    END
  END q[79]
  PIN q[7]
    DIRECTION OUTPUT ;
    USE SIGNAL ;
    PORT
      LAYER M5 ;
        RECT  1.728 11.688 1.752 11.88 ;
    END
  END q[7]
  PIN q[80]
    DIRECTION OUTPUT ;
    USE SIGNAL ;
    PORT
      LAYER M5 ;
        RECT  15.744 11.688 15.768 11.88 ;
    END
  END q[80]
  PIN q[81]
    DIRECTION OUTPUT ;
    USE SIGNAL ;
    PORT
      LAYER M5 ;
        RECT  15.936 11.688 15.96 11.88 ;
    END
  END q[81]
  PIN q[82]
    DIRECTION OUTPUT ;
    USE SIGNAL ;
    PORT
      LAYER M5 ;
        RECT  16.128 11.688 16.152 11.88 ;
    END
  END q[82]
  PIN q[83]
    DIRECTION OUTPUT ;
    USE SIGNAL ;
    PORT
      LAYER M5 ;
        RECT  16.32 11.688 16.344 11.88 ;
    END
  END q[83]
  PIN q[84]
    DIRECTION OUTPUT ;
    USE SIGNAL ;
    PORT
      LAYER M5 ;
        RECT  16.512 11.688 16.536 11.88 ;
    END
  END q[84]
  PIN q[85]
    DIRECTION OUTPUT ;
    USE SIGNAL ;
    PORT
      LAYER M5 ;
        RECT  16.704 11.688 16.728 11.88 ;
    END
  END q[85]
  PIN q[86]
    DIRECTION OUTPUT ;
    USE SIGNAL ;
    PORT
      LAYER M5 ;
        RECT  16.896 11.688 16.92 11.88 ;
    END
  END q[86]
  PIN q[87]
    DIRECTION OUTPUT ;
    USE SIGNAL ;
    PORT
      LAYER M5 ;
        RECT  17.088 11.688 17.112 11.88 ;
    END
  END q[87]
  PIN q[88]
    DIRECTION OUTPUT ;
    USE SIGNAL ;
    PORT
      LAYER M5 ;
        RECT  17.28 11.688 17.304 11.88 ;
    END
  END q[88]
  PIN q[89]
    DIRECTION OUTPUT ;
    USE SIGNAL ;
    PORT
      LAYER M5 ;
        RECT  17.472 11.688 17.496 11.88 ;
    END
  END q[89]
  PIN q[8]
    DIRECTION OUTPUT ;
    USE SIGNAL ;
    PORT
      LAYER M5 ;
        RECT  1.92 11.688 1.944 11.88 ;
    END
  END q[8]
  PIN q[90]
    DIRECTION OUTPUT ;
    USE SIGNAL ;
    PORT
      LAYER M5 ;
        RECT  17.664 11.688 17.688 11.88 ;
    END
  END q[90]
  PIN q[91]
    DIRECTION OUTPUT ;
    USE SIGNAL ;
    PORT
      LAYER M5 ;
        RECT  17.856 11.688 17.88 11.88 ;
    END
  END q[91]
  PIN q[92]
    DIRECTION OUTPUT ;
    USE SIGNAL ;
    PORT
      LAYER M5 ;
        RECT  18.048 11.688 18.072 11.88 ;
    END
  END q[92]
  PIN q[93]
    DIRECTION OUTPUT ;
    USE SIGNAL ;
    PORT
      LAYER M5 ;
        RECT  18.24 11.688 18.264 11.88 ;
    END
  END q[93]
  PIN q[94]
    DIRECTION OUTPUT ;
    USE SIGNAL ;
    PORT
      LAYER M5 ;
        RECT  18.432 11.688 18.456 11.88 ;
    END
  END q[94]
  PIN q[95]
    DIRECTION OUTPUT ;
    USE SIGNAL ;
    PORT
      LAYER M5 ;
        RECT  18.624 11.688 18.648 11.88 ;
    END
  END q[95]
  PIN q[96]
    DIRECTION OUTPUT ;
    USE SIGNAL ;
    PORT
      LAYER M5 ;
        RECT  18.816 11.688 18.84 11.88 ;
    END
  END q[96]
  PIN q[97]
    DIRECTION OUTPUT ;
    USE SIGNAL ;
    PORT
      LAYER M5 ;
        RECT  19.008 11.688 19.032 11.88 ;
    END
  END q[97]
  PIN q[98]
    DIRECTION OUTPUT ;
    USE SIGNAL ;
    PORT
      LAYER M5 ;
        RECT  19.2 11.688 19.224 11.88 ;
    END
  END q[98]
  PIN q[99]
    DIRECTION OUTPUT ;
    USE SIGNAL ;
    PORT
      LAYER M5 ;
        RECT  19.392 11.688 19.416 11.88 ;
    END
  END q[99]
  PIN q[9]
    DIRECTION OUTPUT ;
    USE SIGNAL ;
    PORT
      LAYER M5 ;
        RECT  2.112 11.688 2.136 11.88 ;
    END
  END q[9]
  PIN VDD
    DIRECTION INOUT ;
    USE POWER ;
    PORT
      LAYER M6 ;
        RECT  105.808 9.804 105.84 10.092 ;
        RECT  0 9.804 0.032 10.092 ;
        RECT  0 9.804 105.84 10.092 ;
        RECT  105.808 3.148 105.84 3.436 ;
        RECT  0 3.148 0.032 3.436 ;
        RECT  0 3.148 105.84 3.436 ;
      LAYER M2 ;
        RECT  105.822 11.061 105.84 11.079 ;
        RECT  0 11.061 0.018 11.079 ;
        RECT  105.822 10.521 105.84 10.539 ;
        RECT  0 10.521 0.018 10.539 ;
        RECT  105.822 9.981 105.84 9.999 ;
        RECT  0 9.981 0.018 9.999 ;
        RECT  105.822 9.441 105.84 9.459 ;
        RECT  0 9.441 0.018 9.459 ;
        RECT  105.822 8.901 105.84 8.919 ;
        RECT  0 8.901 0.018 8.919 ;
        RECT  105.822 8.361 105.84 8.379 ;
        RECT  0 8.361 0.018 8.379 ;
        RECT  105.822 7.821 105.84 7.839 ;
        RECT  0 7.821 0.018 7.839 ;
        RECT  105.822 7.281 105.84 7.299 ;
        RECT  0 7.281 0.018 7.299 ;
        RECT  105.822 6.741 105.84 6.759 ;
        RECT  0 6.741 0.018 6.759 ;
        RECT  105.822 6.201 105.84 6.219 ;
        RECT  0 6.201 0.018 6.219 ;
        RECT  105.822 5.661 105.84 5.679 ;
        RECT  0 5.661 0.018 5.679 ;
        RECT  105.822 5.121 105.84 5.139 ;
        RECT  0 5.121 0.018 5.139 ;
        RECT  105.822 4.581 105.84 4.599 ;
        RECT  0 4.581 0.018 4.599 ;
        RECT  105.822 4.041 105.84 4.059 ;
        RECT  0 4.041 0.018 4.059 ;
        RECT  105.822 3.501 105.84 3.519 ;
        RECT  0 3.501 0.018 3.519 ;
        RECT  105.822 2.961 105.84 2.979 ;
        RECT  0 2.961 0.018 2.979 ;
        RECT  105.822 2.421 105.84 2.439 ;
        RECT  0 2.421 0.018 2.439 ;
        RECT  105.822 1.881 105.84 1.899 ;
        RECT  0 1.881 0.018 1.899 ;
        RECT  105.822 1.341 105.84 1.359 ;
        RECT  0 1.341 0.018 1.359 ;
        RECT  105.822 0.801 105.84 0.819 ;
        RECT  0 0.801 0.018 0.819 ;
      LAYER M1 ;
        RECT  105.822 11.061 105.84 11.079 ;
        RECT  0 11.061 0.018 11.079 ;
        RECT  105.822 10.521 105.84 10.539 ;
        RECT  0 10.521 0.018 10.539 ;
        RECT  105.822 9.981 105.84 9.999 ;
        RECT  0 9.981 0.018 9.999 ;
        RECT  105.822 9.441 105.84 9.459 ;
        RECT  0 9.441 0.018 9.459 ;
        RECT  105.822 8.901 105.84 8.919 ;
        RECT  0 8.901 0.018 8.919 ;
        RECT  105.822 8.361 105.84 8.379 ;
        RECT  0 8.361 0.018 8.379 ;
        RECT  105.822 7.821 105.84 7.839 ;
        RECT  0 7.821 0.018 7.839 ;
        RECT  105.822 7.281 105.84 7.299 ;
        RECT  0 7.281 0.018 7.299 ;
        RECT  105.822 6.741 105.84 6.759 ;
        RECT  0 6.741 0.018 6.759 ;
        RECT  105.822 6.201 105.84 6.219 ;
        RECT  0 6.201 0.018 6.219 ;
        RECT  105.822 5.661 105.84 5.679 ;
        RECT  0 5.661 0.018 5.679 ;
        RECT  105.822 5.121 105.84 5.139 ;
        RECT  0 5.121 0.018 5.139 ;
        RECT  105.822 4.581 105.84 4.599 ;
        RECT  0 4.581 0.018 4.599 ;
        RECT  105.822 4.041 105.84 4.059 ;
        RECT  0 4.041 0.018 4.059 ;
        RECT  105.822 3.501 105.84 3.519 ;
        RECT  0 3.501 0.018 3.519 ;
        RECT  105.822 2.961 105.84 2.979 ;
        RECT  0 2.961 0.018 2.979 ;
        RECT  105.822 2.421 105.84 2.439 ;
        RECT  0 2.421 0.018 2.439 ;
        RECT  105.822 1.881 105.84 1.899 ;
        RECT  0 1.881 0.018 1.899 ;
        RECT  105.822 1.341 105.84 1.359 ;
        RECT  0 1.341 0.018 1.359 ;
        RECT  105.822 0.801 105.84 0.819 ;
        RECT  0 0.801 0.018 0.819 ;
    END
  END VDD
  PIN VSS
    DIRECTION INOUT ;
    USE GROUND ;
    PORT
      LAYER M6 ;
        RECT  105.808 9.228 105.84 9.516 ;
        RECT  0 9.228 0.032 9.516 ;
        RECT  0 9.228 105.84 9.516 ;
        RECT  105.808 2.572 105.84 2.86 ;
        RECT  0 2.572 0.032 2.86 ;
        RECT  0 2.572 105.84 2.86 ;
      LAYER M2 ;
        RECT  105.822 11.331 105.84 11.349 ;
        RECT  0 11.331 0.018 11.349 ;
        RECT  105.822 10.791 105.84 10.809 ;
        RECT  0 10.791 0.018 10.809 ;
        RECT  105.822 10.251 105.84 10.269 ;
        RECT  0 10.251 0.018 10.269 ;
        RECT  105.822 9.711 105.84 9.729 ;
        RECT  0 9.711 0.018 9.729 ;
        RECT  105.822 9.171 105.84 9.189 ;
        RECT  0 9.171 0.018 9.189 ;
        RECT  105.822 8.631 105.84 8.649 ;
        RECT  0 8.631 0.018 8.649 ;
        RECT  105.822 8.091 105.84 8.109 ;
        RECT  0 8.091 0.018 8.109 ;
        RECT  105.822 7.551 105.84 7.569 ;
        RECT  0 7.551 0.018 7.569 ;
        RECT  105.822 7.011 105.84 7.029 ;
        RECT  0 7.011 0.018 7.029 ;
        RECT  105.822 6.471 105.84 6.489 ;
        RECT  0 6.471 0.018 6.489 ;
        RECT  105.822 5.931 105.84 5.949 ;
        RECT  0 5.931 0.018 5.949 ;
        RECT  105.822 5.391 105.84 5.409 ;
        RECT  0 5.391 0.018 5.409 ;
        RECT  105.822 4.851 105.84 4.869 ;
        RECT  0 4.851 0.018 4.869 ;
        RECT  105.822 4.311 105.84 4.329 ;
        RECT  0 4.311 0.018 4.329 ;
        RECT  105.822 3.771 105.84 3.789 ;
        RECT  0 3.771 0.018 3.789 ;
        RECT  105.822 3.231 105.84 3.249 ;
        RECT  0 3.231 0.018 3.249 ;
        RECT  105.822 2.691 105.84 2.709 ;
        RECT  0 2.691 0.018 2.709 ;
        RECT  105.822 2.151 105.84 2.169 ;
        RECT  0 2.151 0.018 2.169 ;
        RECT  105.822 1.611 105.84 1.629 ;
        RECT  0 1.611 0.018 1.629 ;
        RECT  105.822 1.071 105.84 1.089 ;
        RECT  0 1.071 0.018 1.089 ;
        RECT  105.822 0.531 105.84 0.549 ;
        RECT  0 0.531 0.018 0.549 ;
      LAYER M1 ;
        RECT  105.822 11.331 105.84 11.349 ;
        RECT  0 11.331 0.018 11.349 ;
        RECT  105.822 10.791 105.84 10.809 ;
        RECT  0 10.791 0.018 10.809 ;
        RECT  105.822 10.251 105.84 10.269 ;
        RECT  0 10.251 0.018 10.269 ;
        RECT  105.822 9.711 105.84 9.729 ;
        RECT  0 9.711 0.018 9.729 ;
        RECT  105.822 9.171 105.84 9.189 ;
        RECT  0 9.171 0.018 9.189 ;
        RECT  105.822 8.631 105.84 8.649 ;
        RECT  0 8.631 0.018 8.649 ;
        RECT  105.822 8.091 105.84 8.109 ;
        RECT  0 8.091 0.018 8.109 ;
        RECT  105.822 7.551 105.84 7.569 ;
        RECT  0 7.551 0.018 7.569 ;
        RECT  105.822 7.011 105.84 7.029 ;
        RECT  0 7.011 0.018 7.029 ;
        RECT  105.822 6.471 105.84 6.489 ;
        RECT  0 6.471 0.018 6.489 ;
        RECT  105.822 5.931 105.84 5.949 ;
        RECT  0 5.931 0.018 5.949 ;
        RECT  105.822 5.391 105.84 5.409 ;
        RECT  0 5.391 0.018 5.409 ;
        RECT  105.822 4.851 105.84 4.869 ;
        RECT  0 4.851 0.018 4.869 ;
        RECT  105.822 4.311 105.84 4.329 ;
        RECT  0 4.311 0.018 4.329 ;
        RECT  105.822 3.771 105.84 3.789 ;
        RECT  0 3.771 0.018 3.789 ;
        RECT  105.822 3.231 105.84 3.249 ;
        RECT  0 3.231 0.018 3.249 ;
        RECT  105.822 2.691 105.84 2.709 ;
        RECT  0 2.691 0.018 2.709 ;
        RECT  105.822 2.151 105.84 2.169 ;
        RECT  0 2.151 0.018 2.169 ;
        RECT  105.822 1.611 105.84 1.629 ;
        RECT  0 1.611 0.018 1.629 ;
        RECT  105.822 1.071 105.84 1.089 ;
        RECT  0 1.071 0.018 1.089 ;
        RECT  105.822 0.531 105.84 0.549 ;
        RECT  0 0.531 0.018 0.549 ;
    END
  END VSS
  OBS
    LAYER RVTN ;
     RECT  0 0.54 105.84 0.675 ;
     RECT  0 0.945 105.84 1.215 ;
     RECT  0 1.485 105.84 1.755 ;
     RECT  0 2.025 105.84 2.295 ;
     RECT  0 2.565 105.84 2.835 ;
     RECT  0 3.105 105.84 3.375 ;
     RECT  0 3.645 105.84 3.915 ;
     RECT  0 4.185 105.84 4.455 ;
     RECT  0 4.725 105.84 4.995 ;
     RECT  0 5.265 105.84 5.535 ;
     RECT  0 5.805 105.84 6.075 ;
     RECT  0 6.345 105.84 6.615 ;
     RECT  0 6.885 105.84 7.155 ;
     RECT  0 7.425 105.84 7.695 ;
     RECT  0 7.965 105.84 8.235 ;
     RECT  0 8.505 105.84 8.775 ;
     RECT  0 9.045 105.84 9.315 ;
     RECT  0 9.585 105.84 9.855 ;
     RECT  0 10.125 105.84 10.395 ;
     RECT  0 10.665 105.84 10.935 ;
     RECT  0 11.205 105.84 11.34 ;
    LAYER RVTP ;
     RECT  0 0.675 105.84 0.945 ;
     RECT  0 1.215 105.84 1.485 ;
     RECT  0 1.755 105.84 2.025 ;
     RECT  0 2.295 105.84 2.565 ;
     RECT  0 2.835 105.84 3.105 ;
     RECT  0 3.375 105.84 3.645 ;
     RECT  0 3.915 105.84 4.185 ;
     RECT  0 4.455 105.84 4.725 ;
     RECT  0 4.995 105.84 5.265 ;
     RECT  0 5.535 105.84 5.805 ;
     RECT  0 6.075 105.84 6.345 ;
     RECT  0 6.615 105.84 6.885 ;
     RECT  0 7.155 105.84 7.425 ;
     RECT  0 7.695 105.84 7.965 ;
     RECT  0 8.235 105.84 8.505 ;
     RECT  0 8.775 105.84 9.045 ;
     RECT  0 9.315 105.84 9.585 ;
     RECT  0 9.855 105.84 10.125 ;
     RECT  0 10.395 105.84 10.665 ;
     RECT  0 10.935 105.84 11.205 ;
    LAYER M1 ;
     RECT  0 0.531 105.84 11.349 ;
    LAYER M2 ;
     RECT  0 0.531 105.84 11.349 ;
    LAYER M3 ;
     RECT  28.656 0.187 49.086 0.235 ;
     RECT  50.04 0.187 55.35 0.235 ;
     RECT  58.032 0.187 94.266 0.235 ;
     RECT  95.076 0.187 104.49 0.235 ;
     RECT  0.468 0.187 27.81 0.523 ;
     RECT  0.255 0.523 27.81 0.571 ;
     RECT  28.548 0.235 55.35 0.571 ;
     RECT  56.52 0.187 57.294 0.571 ;
     RECT  0.255 0.571 57.294 0.679 ;
     RECT  105.228 0.187 105.246 0.679 ;
     RECT  0.072 0.679 57.294 0.715 ;
     RECT  58.032 0.235 104.49 0.715 ;
     RECT  0.072 0.715 104.49 0.751 ;
     RECT  105.228 0.679 105.354 0.751 ;
     RECT  0.072 0.751 105.354 0.779 ;
     RECT  0.072 0.779 105.138 1.715 ;
     RECT  0.108 1.715 105.138 1.831 ;
     RECT  0.108 1.831 105.318 2.129 ;
     RECT  0.18 2.129 105.138 2.363 ;
     RECT  0.18 2.363 105.03 2.525 ;
     RECT  0.255 2.525 105.03 2.831 ;
     RECT  0.255 2.831 104.994 3.137 ;
     RECT  0.255 3.137 104.85 3.403 ;
     RECT  0.18 3.403 104.85 3.605 ;
     RECT  0.255 3.605 104.85 3.713 ;
     RECT  0.255 3.713 71.442 3.839 ;
     RECT  0.255 3.839 71.37 3.983 ;
     RECT  0.255 3.983 71.226 4.145 ;
     RECT  51.984 4.145 71.226 4.415 ;
     RECT  72.18 3.713 104.85 4.531 ;
     RECT  0.255 4.145 51.03 4.559 ;
     RECT  52.02 4.415 71.226 4.559 ;
     RECT  72.18 4.531 104.886 4.649 ;
     RECT  12.384 4.559 51.03 4.685 ;
     RECT  56.952 4.559 71.226 4.801 ;
     RECT  72.18 4.649 75.042 4.801 ;
     RECT  75.78 4.649 104.886 4.991 ;
     RECT  12.384 4.685 31.446 5.117 ;
     RECT  42.804 4.685 51.03 5.131 ;
     RECT  56.952 4.801 75.042 5.225 ;
     RECT  32.256 4.685 42.066 5.261 ;
     RECT  67.644 5.225 75.042 5.261 ;
     RECT  42.804 5.131 51.282 5.341 ;
     RECT  52.02 4.559 56.142 5.341 ;
     RECT  67.68 5.261 75.042 5.405 ;
     RECT  75.78 4.991 104.85 5.405 ;
     RECT  12.384 5.117 28.386 5.495 ;
     RECT  29.376 5.117 31.446 5.611 ;
     RECT  32.256 5.261 38.61 5.611 ;
     RECT  70.02 5.405 75.042 5.611 ;
     RECT  75.78 5.405 94.806 5.611 ;
     RECT  42.804 5.341 56.142 5.645 ;
     RECT  0.255 4.559 11.646 5.707 ;
     RECT  39.384 5.261 42.066 5.707 ;
     RECT  42.804 5.645 44.73 5.707 ;
     RECT  29.376 5.611 38.61 5.729 ;
     RECT  0.18 5.707 11.646 5.765 ;
     RECT  12.564 5.495 28.386 5.881 ;
     RECT  29.376 5.729 29.862 5.881 ;
     RECT  47.052 5.645 56.142 5.881 ;
     RECT  47.052 5.881 56.214 5.947 ;
     RECT  56.952 5.225 66.834 5.947 ;
     RECT  30.672 5.729 38.61 5.999 ;
     RECT  67.68 5.405 69.282 5.999 ;
     RECT  70.02 5.611 94.806 6.151 ;
     RECT  39.384 5.707 44.73 6.221 ;
     RECT  35.64 5.999 38.61 6.235 ;
     RECT  39.384 6.221 44.262 6.235 ;
     RECT  69.408 6.151 94.986 6.235 ;
     RECT  95.724 5.405 104.85 6.235 ;
     RECT  0.255 5.765 11.646 6.241 ;
     RECT  12.564 5.881 29.862 6.241 ;
     RECT  47.052 5.947 66.834 6.241 ;
     RECT  67.68 5.999 68.67 6.241 ;
     RECT  0.255 6.241 29.862 6.269 ;
     RECT  9 6.269 29.862 6.317 ;
     RECT  35.64 6.235 44.262 6.317 ;
     RECT  29.844 6.317 29.862 6.511 ;
     RECT  30.672 5.999 34.866 6.511 ;
     RECT  45.504 5.645 46.242 6.523 ;
     RECT  47.052 6.241 68.67 6.523 ;
     RECT  35.64 6.317 38.61 6.539 ;
     RECT  35.64 6.539 36.882 6.575 ;
     RECT  45.108 6.523 68.67 6.575 ;
     RECT  39.564 6.317 44.262 6.845 ;
     RECT  45.504 6.575 68.67 6.859 ;
     RECT  69.408 6.235 104.85 6.859 ;
     RECT  29.844 6.511 34.866 6.961 ;
     RECT  35.64 6.575 36.594 6.961 ;
     RECT  0.255 6.269 8.154 7.231 ;
     RECT  9.036 6.317 29.106 7.231 ;
     RECT  37.656 6.539 38.61 7.321 ;
     RECT  39.564 6.845 39.942 7.321 ;
     RECT  29.844 6.961 36.594 7.435 ;
     RECT  40.968 6.845 44.262 7.435 ;
     RECT  37.656 7.321 39.942 7.771 ;
     RECT  40.968 7.435 44.766 7.771 ;
     RECT  45.504 6.859 104.85 7.771 ;
     RECT  37.656 7.771 104.85 7.861 ;
     RECT  29.844 7.435 36.81 7.933 ;
     RECT  37.584 7.861 104.85 7.933 ;
     RECT  0.255 7.231 29.106 7.949 ;
     RECT  29.844 7.933 104.85 7.963 ;
     RECT  29.412 7.963 104.85 7.997 ;
     RECT  37.728 7.997 104.85 8.045 ;
     RECT  29.412 7.997 36.594 8.195 ;
     RECT  0.255 7.949 28.674 8.231 ;
     RECT  29.484 8.195 36.594 8.285 ;
     RECT  29.484 8.285 30.87 8.381 ;
     RECT  37.728 8.045 88.83 8.429 ;
     RECT  8.676 8.231 28.674 8.525 ;
     RECT  9.036 8.525 28.674 8.537 ;
     RECT  31.68 8.285 36.594 8.851 ;
     RECT  37.728 8.429 88.794 8.851 ;
     RECT  29.52 8.381 30.87 8.879 ;
     RECT  31.68 8.851 88.794 8.909 ;
     RECT  51.984 8.909 88.794 9.005 ;
     RECT  31.68 8.909 51.246 9.101 ;
     RECT  0.255 8.231 7.902 9.121 ;
     RECT  24.48 8.537 28.674 9.121 ;
     RECT  29.52 8.879 30.798 9.121 ;
     RECT  72.252 9.005 88.794 9.149 ;
     RECT  89.568 8.045 104.85 9.211 ;
     RECT  9.036 8.537 23.742 9.239 ;
     RECT  24.48 9.121 30.798 9.239 ;
     RECT  34.2 9.101 51.246 9.239 ;
     RECT  89.388 9.211 104.85 9.275 ;
     RECT  10.26 9.239 23.742 9.391 ;
     RECT  24.48 9.239 25.434 9.391 ;
     RECT  45.216 9.239 51.246 9.437 ;
     RECT  26.28 9.239 30.798 9.629 ;
     RECT  30.6 9.629 30.798 9.661 ;
     RECT  31.68 9.101 33.318 9.661 ;
     RECT  51.984 9.005 71.442 9.677 ;
     RECT  0.255 9.121 8.262 9.691 ;
     RECT  30.6 9.661 33.318 9.931 ;
     RECT  34.2 9.239 44.406 9.931 ;
     RECT  46.8 9.437 51.246 9.931 ;
     RECT  51.984 9.677 66.474 9.931 ;
     RECT  72.252 9.149 88.47 9.959 ;
     RECT  10.26 9.391 25.434 10.021 ;
     RECT  26.28 9.629 29.862 10.021 ;
     RECT  89.604 9.275 104.85 10.021 ;
     RECT  72.252 9.959 82.458 10.049 ;
     RECT  10.26 10.021 29.862 10.085 ;
     RECT  30.6 9.931 44.406 10.121 ;
     RECT  0.255 9.691 8.298 10.165 ;
     RECT  9.036 9.239 9.414 10.165 ;
     RECT  30.6 10.121 30.798 10.193 ;
     RECT  31.788 10.121 44.406 10.201 ;
     RECT  45.216 9.437 45.558 10.201 ;
     RECT  46.8 9.931 66.474 10.201 ;
     RECT  67.5 9.677 71.442 10.201 ;
     RECT  72.252 10.049 82.422 10.201 ;
     RECT  83.232 9.959 88.47 10.201 ;
     RECT  0.255 10.165 9.414 10.253 ;
     RECT  46.764 10.201 66.474 10.253 ;
     RECT  67.5 10.201 82.422 10.253 ;
     RECT  19.44 10.085 29.862 10.301 ;
     RECT  46.8 10.253 66.474 10.301 ;
     RECT  0.255 10.253 2.502 10.471 ;
     RECT  3.312 10.253 9.414 10.471 ;
     RECT  26.64 10.301 29.862 10.471 ;
     RECT  30.6 10.193 30.762 10.471 ;
     RECT  50.292 10.301 66.474 10.589 ;
     RECT  61.02 10.589 66.474 10.741 ;
     RECT  67.5 10.253 68.958 10.741 ;
     RECT  3.312 10.471 9.45 10.781 ;
     RECT  5.292 10.781 9.45 10.829 ;
     RECT  19.44 10.301 25.758 10.829 ;
     RECT  31.788 10.201 45.558 10.829 ;
     RECT  61.02 10.741 68.958 10.829 ;
     RECT  0.216 10.471 2.502 10.877 ;
     RECT  3.312 10.781 4.482 10.877 ;
     RECT  10.26 10.085 18.702 10.877 ;
     RECT  19.44 10.829 19.602 10.877 ;
     RECT  20.448 10.829 25.758 10.877 ;
     RECT  26.64 10.471 30.762 10.877 ;
     RECT  31.788 10.829 33.858 10.877 ;
     RECT  36.756 10.829 45.558 10.877 ;
     RECT  50.292 10.589 60.246 10.877 ;
     RECT  61.02 10.829 61.47 10.877 ;
     RECT  62.208 10.829 68.958 10.877 ;
     RECT  69.696 10.253 82.422 10.877 ;
     RECT  83.232 10.201 88.758 10.877 ;
     RECT  89.532 10.021 104.85 10.877 ;
     RECT  7.848 10.829 9.45 10.895 ;
     RECT  13.68 10.877 18.702 10.895 ;
     RECT  23.58 10.877 25.758 10.895 ;
     RECT  0.216 10.877 2.07 10.925 ;
     RECT  23.616 10.895 25.758 10.925 ;
     RECT  41.796 10.877 45.558 10.925 ;
     RECT  50.292 10.877 52.614 10.925 ;
     RECT  58.824 10.877 60.246 10.925 ;
     RECT  68.688 10.877 68.958 10.925 ;
     RECT  70.416 10.877 73.494 10.925 ;
     RECT  74.34 10.877 78.534 10.925 ;
     RECT  79.524 10.877 79.794 10.925 ;
     RECT  77.148 10.925 78.534 11.003 ;
     RECT  17.748 10.895 18.702 11.011 ;
     RECT  19.44 10.877 19.458 11.011 ;
     RECT  81.036 10.877 82.422 11.011 ;
     RECT  83.232 10.877 85.482 11.011 ;
     RECT  86.655 10.877 88.758 11.011 ;
     RECT  89.532 10.877 100.494 11.011 ;
     RECT  53.424 10.877 55.674 11.021 ;
     RECT  27.255 10.877 30.762 11.039 ;
     RECT  7.92 10.895 9.45 11.069 ;
     RECT  17.748 11.011 19.458 11.069 ;
     RECT  35.352 10.829 36.018 11.069 ;
     RECT  36.756 10.877 40.662 11.069 ;
     RECT  42.264 10.925 45.558 11.069 ;
     RECT  62.208 10.877 62.874 11.069 ;
     RECT  63.792 10.877 65.337 11.069 ;
     RECT  66.42 10.877 66.834 11.069 ;
     RECT  77.148 11.003 77.166 11.069 ;
     RECT  77.904 11.003 78.534 11.069 ;
     RECT  81.036 11.011 85.482 11.069 ;
     RECT  46.8 10.301 49.518 11.083 ;
     RECT  64.98 11.069 65.337 11.087 ;
     RECT  8.46 11.069 9.45 11.129 ;
     RECT  18.288 11.069 19.458 11.129 ;
     RECT  39.6 11.069 40.662 11.129 ;
     RECT  42.264 11.069 44.37 11.129 ;
     RECT  45.144 11.069 45.558 11.129 ;
     RECT  46.656 11.083 49.518 11.129 ;
     RECT  66.42 11.069 66.798 11.129 ;
     RECT  67.572 10.877 67.77 11.129 ;
     RECT  81.036 11.069 82.062 11.129 ;
     RECT  82.8 11.069 85.482 11.129 ;
     RECT  0.216 10.925 0.702 11.165 ;
     RECT  1.476 10.925 2.07 11.165 ;
     RECT  13.68 10.895 17.01 11.165 ;
     RECT  18.288 11.129 18.306 11.165 ;
     RECT  21.78 10.877 22.59 11.165 ;
     RECT  23.616 10.925 24.858 11.165 ;
     RECT  25.74 10.925 25.758 11.165 ;
     RECT  27.255 11.039 29.97 11.165 ;
     RECT  30.744 11.039 30.762 11.165 ;
     RECT  35.928 11.069 36.018 11.165 ;
     RECT  36.756 11.069 38.466 11.165 ;
     RECT  43.416 11.129 44.226 11.165 ;
     RECT  45.324 11.129 45.558 11.165 ;
     RECT  47.664 11.129 49.518 11.165 ;
     RECT  53.424 11.021 55.422 11.165 ;
     RECT  56.448 10.877 57.942 11.165 ;
     RECT  59.256 10.925 60.246 11.165 ;
     RECT  61.308 10.877 61.47 11.165 ;
     RECT  63.792 11.069 63.954 11.165 ;
     RECT  64.98 11.087 65.145 11.165 ;
     RECT  67.68 11.129 67.77 11.165 ;
     RECT  70.455 10.925 73.494 11.165 ;
     RECT  74.988 10.925 76.194 11.165 ;
     RECT  77.904 11.069 78.03 11.165 ;
     RECT  79.524 10.925 79.65 11.165 ;
     RECT  81.036 11.129 81.918 11.165 ;
     RECT  83.052 11.129 85.482 11.165 ;
     RECT  101.664 10.877 102.078 11.165 ;
     RECT  5.292 10.829 6.894 11.201 ;
     RECT  86.655 11.011 100.494 11.201 ;
     RECT  102.855 10.877 104.418 11.201 ;
     RECT  10.26 10.877 12.582 11.213 ;
     RECT  13.824 11.165 17.01 11.213 ;
     RECT  21.816 11.165 22.59 11.213 ;
     RECT  59.4 11.165 60.246 11.213 ;
     RECT  81.036 11.165 81.774 11.213 ;
     RECT  86.655 11.201 99.27 11.213 ;
     RECT  11.055 11.213 12.582 11.273 ;
     RECT  81.036 11.213 81.594 11.273 ;
     RECT  92.916 11.213 99.27 11.273 ;
     RECT  45.36 11.165 45.558 11.281 ;
     RECT  47.772 11.165 49.518 11.281 ;
     RECT  50.292 10.925 52.11 11.281 ;
     RECT  0.255 11.165 0.702 11.357 ;
     RECT  1.62 11.165 2.07 11.357 ;
     RECT  3.456 10.877 4.482 11.357 ;
     RECT  5.292 11.201 6.858 11.357 ;
     RECT  8.46 11.129 8.478 11.357 ;
     RECT  9.288 11.129 9.306 11.357 ;
     RECT  10.26 11.213 10.278 11.357 ;
     RECT  11.055 11.273 11.61 11.357 ;
     RECT  12.564 11.273 12.582 11.357 ;
     RECT  13.824 11.213 16.614 11.357 ;
     RECT  19.44 11.129 19.458 11.357 ;
     RECT  20.628 10.877 21.006 11.357 ;
     RECT  21.816 11.213 21.945 11.357 ;
     RECT  23.796 11.165 24.858 11.357 ;
     RECT  25.848 11.281 25.866 11.357 ;
     RECT  27.255 11.165 27.345 11.357 ;
     RECT  28.116 11.165 29.97 11.357 ;
     RECT  30.924 11.281 30.942 11.357 ;
     RECT  31.788 10.877 33.282 11.357 ;
     RECT  36 11.165 36.018 11.357 ;
     RECT  36.864 11.165 38.466 11.357 ;
     RECT  39.888 11.129 40.662 11.357 ;
     RECT  42.264 11.129 42.462 11.357 ;
     RECT  43.416 11.165 43.545 11.357 ;
     RECT  45.36 11.281 45.702 11.357 ;
     RECT  47.772 11.281 52.11 11.357 ;
     RECT  53.604 11.165 55.422 11.357 ;
     RECT  56.52 11.165 57.942 11.357 ;
     RECT  59.4 11.213 60.21 11.357 ;
     RECT  61.452 11.165 61.47 11.357 ;
     RECT  62.208 11.069 62.226 11.357 ;
     RECT  63.936 11.165 63.954 11.357 ;
     RECT  65.016 11.165 65.145 11.357 ;
     RECT  66.42 11.129 66.438 11.357 ;
     RECT  67.752 11.165 67.77 11.357 ;
     RECT  68.688 10.925 68.706 11.357 ;
     RECT  70.455 11.165 71.622 11.357 ;
     RECT  72.396 11.165 73.494 11.357 ;
     RECT  78.012 11.165 78.03 11.357 ;
     RECT  79.632 11.165 79.65 11.357 ;
     RECT  81.036 11.273 81.345 11.357 ;
     RECT  83.052 11.165 84.69 11.357 ;
     RECT  85.464 11.165 85.482 11.357 ;
     RECT  86.655 11.213 92.145 11.357 ;
     RECT  92.916 11.273 92.934 11.357 ;
     RECT  93.888 11.273 99.27 11.357 ;
     RECT  100.224 11.201 100.494 11.357 ;
     RECT  101.772 11.165 102.078 11.357 ;
     RECT  102.855 11.201 104.022 11.357 ;
     RECT  2.052 11.357 2.07 11.405 ;
     RECT  4.464 11.357 4.482 11.405 ;
     RECT  15.804 11.357 15.822 11.405 ;
     RECT  24.588 11.357 24.606 11.405 ;
     RECT  29.7 11.357 29.718 11.405 ;
     RECT  40.644 11.357 40.662 11.405 ;
     RECT  48.06 11.357 48.798 11.405 ;
     RECT  50.868 11.357 50.886 11.405 ;
     RECT  51.768 11.357 51.786 11.405 ;
     RECT  54.828 11.357 55.422 11.405 ;
     RECT  57.672 11.357 57.69 11.405 ;
     RECT  75.096 11.165 76.194 11.405 ;
     RECT  88.92 11.357 88.938 11.405 ;
     RECT  89.964 11.357 89.982 11.405 ;
     RECT  95.04 11.357 95.058 11.405 ;
     RECT  97.128 11.357 97.794 11.405 ;
     RECT  102.06 11.357 102.078 11.405 ;
     RECT  21.816 11.357 21.834 11.453 ;
     RECT  59.94 11.357 59.958 11.453 ;
     RECT  75.816 11.405 76.194 11.453 ;
     RECT  0.396 11.357 0.414 11.501 ;
     RECT  5.796 11.357 5.814 11.501 ;
     RECT  16.596 11.357 16.614 11.501 ;
     RECT  32.616 11.357 32.634 11.501 ;
     RECT  37.728 11.357 37.746 11.501 ;
     RECT  43.416 11.357 43.434 11.501 ;
     RECT  48.78 11.405 48.798 11.501 ;
     RECT  54.828 11.405 54.846 11.501 ;
     RECT  65.016 11.357 65.034 11.501 ;
     RECT  75.816 11.453 75.834 11.501 ;
     RECT  86.796 11.357 87.03 11.501 ;
     RECT  92.016 11.357 92.034 11.501 ;
     RECT  97.776 11.405 97.794 11.501 ;
     RECT  103.032 11.357 103.05 11.501 ;
     RECT  86.796 11.501 86.814 11.549 ;
     RECT  31.716 11.659 31.734 11.789 ;
     RECT  42.084 11.659 42.102 11.789 ;
     RECT  70.884 11.357 70.902 11.789 ;
     RECT  81.072 11.357 81.09 11.789 ;
    LAYER M4 ;
     RECT  0.085 1.296 0.133 1.32 ;
     RECT  0.085 3.072 0.133 3.096 ;
     RECT  0.133 1.104 0.248 1.32 ;
     RECT  0.133 3.072 0.248 3.864 ;
     RECT  0.133 5.712 0.248 5.736 ;
     RECT  0.133 8.448 0.248 8.472 ;
     RECT  0.133 9.792 0.248 9.816 ;
     RECT  0.248 0.528 0.373 11.352 ;
     RECT  0.373 0.192 0.425 11.496 ;
     RECT  0.425 0.192 0.544 11.352 ;
     RECT  0.544 1.68 0.755 8.712 ;
     RECT  0.755 1.68 1.139 6.84 ;
     RECT  0.755 7.872 1.139 8.568 ;
     RECT  1.139 6.816 1.145 6.84 ;
     RECT  0.544 0.192 1.525 0.696 ;
     RECT  1.139 1.68 1.525 5.736 ;
     RECT  0.544 10.8 1.525 11.352 ;
     RECT  1.525 0.192 1.571 5.736 ;
     RECT  1.139 7.872 1.649 7.896 ;
     RECT  0.544 9.696 1.717 9.72 ;
     RECT  1.525 10.8 1.717 11.4 ;
     RECT  1.717 9.696 1.909 11.4 ;
     RECT  1.909 9.648 2.009 11.4 ;
     RECT  2.009 9.696 2.081 11.4 ;
     RECT  2.149 6.24 2.195 6.264 ;
     RECT  2.437 7.536 2.617 7.56 ;
     RECT  2.617 7.44 2.677 7.56 ;
     RECT  1.571 0.192 2.867 5.208 ;
     RECT  2.081 9.696 2.981 10.872 ;
     RECT  2.677 7.44 3.049 7.752 ;
     RECT  3.049 7.44 3.061 8.568 ;
     RECT  2.981 10.848 3.061 10.872 ;
     RECT  3.061 7.2 3.193 8.568 ;
     RECT  3.265 9.648 3.347 9.672 ;
     RECT  3.193 7.2 3.349 8.664 ;
     RECT  3.349 6.864 3.443 8.664 ;
     RECT  3.443 6.864 3.733 7.992 ;
     RECT  3.733 6.24 3.779 7.992 ;
     RECT  3.779 6.24 3.877 7.464 ;
     RECT  2.867 0.192 3.923 5.112 ;
     RECT  3.877 6.192 3.923 7.464 ;
     RECT  3.829 9.072 3.953 9.096 ;
     RECT  3.061 10.848 4.021 11.352 ;
     RECT  3.923 6.192 4.025 6.84 ;
     RECT  3.923 2.736 4.241 5.112 ;
     RECT  4.241 2.88 4.313 5.112 ;
     RECT  4.357 5.28 4.421 5.304 ;
     RECT  4.405 9.648 4.493 9.672 ;
     RECT  4.021 10.848 4.493 11.4 ;
     RECT  4.493 10.848 4.549 11.352 ;
     RECT  4.025 6.816 4.885 6.84 ;
     RECT  4.885 6.816 5.077 8.184 ;
     RECT  5.173 5.664 5.317 5.688 ;
     RECT  5.077 6.72 5.317 8.52 ;
     RECT  4.313 2.88 5.413 4.008 ;
     RECT  4.549 9.696 5.461 11.352 ;
     RECT  3.923 0.192 5.509 1.752 ;
     RECT  5.413 2.88 5.509 4.536 ;
     RECT  5.317 5.664 5.509 8.52 ;
     RECT  5.509 0.192 5.648 8.52 ;
     RECT  5.461 9.696 5.648 11.496 ;
     RECT  5.648 0.192 5.825 11.496 ;
     RECT  5.825 0.192 6.227 11.352 ;
     RECT  6.227 0.192 6.275 9.144 ;
     RECT  6.227 10.224 6.761 11.352 ;
     RECT  6.275 0.192 6.803 5.736 ;
     RECT  6.761 10.8 6.869 11.352 ;
     RECT  6.803 0.192 7.049 5.64 ;
     RECT  7.049 0.192 7.139 5.112 ;
     RECT  6.275 6.864 7.157 9.144 ;
     RECT  7.157 6.864 7.381 8.952 ;
     RECT  7.381 6.816 7.427 8.952 ;
     RECT  7.427 6.816 7.517 7.368 ;
     RECT  7.517 6.864 7.763 7.368 ;
     RECT  7.139 0.192 7.841 4.104 ;
     RECT  7.763 7.248 8.051 7.368 ;
     RECT  6.869 10.8 8.101 11.064 ;
     RECT  8.101 10.176 8.269 11.064 ;
     RECT  7.139 5.088 8.377 5.112 ;
     RECT  8.377 5.088 8.413 5.208 ;
     RECT  8.269 9.696 8.437 11.064 ;
     RECT  8.413 5.04 8.485 5.208 ;
     RECT  8.449 7.44 8.485 7.464 ;
     RECT  7.427 8.496 8.485 8.52 ;
     RECT  8.437 9.696 8.531 11.352 ;
     RECT  8.485 5.04 8.533 5.64 ;
     RECT  8.533 5.04 8.579 6.264 ;
     RECT  8.579 5.616 8.597 6.264 ;
     RECT  8.597 5.712 8.989 6.264 ;
     RECT  7.841 0.192 9.061 3.672 ;
     RECT  9.061 0.192 9.173 3.96 ;
     RECT  8.989 5.712 9.397 6.312 ;
     RECT  8.485 7.44 9.397 8.52 ;
     RECT  8.531 10.272 9.425 11.352 ;
     RECT  9.397 5.712 9.565 8.52 ;
     RECT  9.565 5.712 9.683 9.096 ;
     RECT  9.683 5.712 9.785 8.52 ;
     RECT  9.785 5.712 9.877 6.888 ;
     RECT  9.877 5.088 9.929 6.888 ;
     RECT  9.173 0.192 10.429 3.576 ;
     RECT  10.285 9.6 10.465 9.624 ;
     RECT  9.425 10.896 10.465 11.352 ;
     RECT  9.785 7.968 10.741 8.52 ;
     RECT  10.465 9.6 10.741 11.352 ;
     RECT  10.429 0.192 10.837 4.008 ;
     RECT  9.929 5.088 10.837 6.84 ;
     RECT  10.741 7.968 10.885 11.352 ;
     RECT  10.837 0.192 11.048 6.84 ;
     RECT  10.885 7.968 11.048 11.496 ;
     RECT  11.048 0.192 11.171 11.496 ;
     RECT  11.171 0.192 11.344 11.352 ;
     RECT  11.344 0.192 11.405 6.312 ;
     RECT  11.344 9.072 11.549 11.352 ;
     RECT  11.405 0.192 12.373 4.968 ;
     RECT  11.405 6.288 12.445 6.312 ;
     RECT  12.373 0.192 12.469 5.16 ;
     RECT  12.445 6.288 12.469 6.888 ;
     RECT  12.469 0.192 12.515 6.888 ;
     RECT  11.344 7.92 12.517 7.944 ;
     RECT  11.549 9.12 12.521 11.352 ;
     RECT  12.515 0.192 12.563 6.312 ;
     RECT  12.521 9.12 12.563 9.144 ;
     RECT  12.517 7.344 12.593 7.944 ;
     RECT  12.521 10.272 12.593 11.352 ;
     RECT  12.593 7.392 12.805 7.944 ;
     RECT  12.805 7.392 12.901 7.992 ;
     RECT  12.901 7.392 12.989 8.376 ;
     RECT  12.593 10.272 13.525 10.872 ;
     RECT  12.563 0.192 13.573 6.264 ;
     RECT  12.989 7.392 13.573 8.328 ;
     RECT  13.525 9.936 13.601 10.872 ;
     RECT  13.601 10.752 13.621 10.872 ;
     RECT  13.573 0.192 13.637 8.328 ;
     RECT  13.637 0.192 13.709 5.88 ;
     RECT  13.709 0.192 14.003 4.536 ;
     RECT  13.637 7.44 14.099 8.328 ;
     RECT  13.709 5.712 14.531 5.88 ;
     RECT  14.099 7.968 14.605 8.328 ;
     RECT  13.741 9.696 14.605 9.72 ;
     RECT  14.605 7.968 14.675 9.72 ;
     RECT  14.773 6.24 14.821 6.264 ;
     RECT  14.675 9.696 14.821 9.72 ;
     RECT  13.621 10.752 14.821 11.352 ;
     RECT  14.821 6.24 14.965 6.312 ;
     RECT  14.003 2.304 15.073 4.296 ;
     RECT  14.965 6.24 15.181 6.888 ;
     RECT  14.675 7.968 15.181 8.568 ;
     RECT  14.003 0.192 15.205 0.792 ;
     RECT  15.073 2.304 15.205 4.632 ;
     RECT  15.181 6.24 15.251 8.568 ;
     RECT  15.205 0.192 15.347 5.256 ;
     RECT  14.821 9.696 15.349 11.352 ;
     RECT  15.347 0.192 15.437 4.008 ;
     RECT  15.251 6.24 15.437 6.888 ;
     RECT  15.251 7.968 15.865 8.568 ;
     RECT  15.349 9.696 15.865 11.4 ;
     RECT  15.347 5.232 16.309 5.256 ;
     RECT  15.437 6.24 16.309 6.264 ;
     RECT  15.865 7.968 16.309 11.4 ;
     RECT  15.437 0.192 16.448 1.704 ;
     RECT  15.437 2.784 16.448 4.008 ;
     RECT  16.309 5.136 16.448 6.264 ;
     RECT  16.309 7.44 16.448 11.4 ;
     RECT  16.448 0.192 16.501 11.4 ;
     RECT  16.501 0.192 16.625 11.496 ;
     RECT  16.625 0.192 17.021 11.208 ;
     RECT  17.021 0.192 17.201 11.064 ;
     RECT  17.201 0.192 17.453 4.056 ;
     RECT  17.201 5.136 17.597 11.064 ;
     RECT  17.453 0.192 17.669 4.008 ;
     RECT  17.669 0.192 18.709 3.96 ;
     RECT  17.597 5.136 18.709 9.72 ;
     RECT  17.597 10.752 18.709 11.064 ;
     RECT  18.709 0.192 18.755 11.064 ;
     RECT  18.755 10.8 18.997 11.064 ;
     RECT  18.755 0.192 19.397 7.992 ;
     RECT  18.997 10.8 19.469 11.352 ;
     RECT  18.755 9.072 19.505 9.624 ;
     RECT  19.397 0.192 19.577 6.168 ;
     RECT  19.577 2.256 19.685 6.168 ;
     RECT  19.397 7.44 19.715 7.992 ;
     RECT  19.505 9.12 19.765 9.624 ;
     RECT  19.685 2.256 19.811 5.736 ;
     RECT  19.765 9.12 19.955 9.672 ;
     RECT  19.811 2.256 19.973 5.688 ;
     RECT  19.955 9.6 20.045 9.672 ;
     RECT  19.973 4.608 20.051 5.688 ;
     RECT  19.469 10.8 20.225 10.872 ;
     RECT  20.225 10.848 20.533 10.872 ;
     RECT  20.045 9.6 20.837 9.624 ;
     RECT  19.577 0.192 20.965 1.128 ;
     RECT  19.973 2.256 20.965 3.624 ;
     RECT  20.965 0.192 21.013 3.624 ;
     RECT  19.715 7.44 21.061 7.8 ;
     RECT  21.061 7.44 21.109 7.896 ;
     RECT  20.977 9.12 21.109 9.144 ;
     RECT  21.109 7.44 21.301 9.144 ;
     RECT  20.533 10.848 21.301 11.352 ;
     RECT  20.051 5.136 21.493 5.688 ;
     RECT  21.301 6.816 21.493 9.144 ;
     RECT  21.013 0.192 21.589 4.008 ;
     RECT  21.493 5.136 21.589 9.144 ;
     RECT  21.301 10.848 21.733 11.448 ;
     RECT  21.589 0.192 21.848 9.144 ;
     RECT  21.733 10.704 21.848 11.496 ;
     RECT  21.848 0.192 21.923 11.496 ;
     RECT  21.923 0.192 21.952 11.352 ;
     RECT  21.952 0.192 22.144 11.208 ;
     RECT  22.144 9.744 22.601 11.208 ;
     RECT  22.144 0.192 22.781 6.312 ;
     RECT  22.781 0.192 22.925 6.264 ;
     RECT  22.601 9.744 23.173 10.872 ;
     RECT  22.144 7.392 23.221 8.568 ;
     RECT  23.173 9.696 23.221 10.872 ;
     RECT  23.221 7.392 23.315 10.872 ;
     RECT  22.925 1.68 23.363 5.64 ;
     RECT  23.315 10.272 23.605 10.872 ;
     RECT  23.315 7.392 23.653 9.144 ;
     RECT  23.653 7.344 23.717 9.144 ;
     RECT  23.605 10.272 23.785 11.064 ;
     RECT  22.925 0.192 23.893 0.312 ;
     RECT  23.785 10.272 23.939 11.352 ;
     RECT  23.363 2.16 23.941 5.64 ;
     RECT  23.941 2.16 24.037 5.736 ;
     RECT  24.037 2.16 24.253 5.784 ;
     RECT  23.717 7.392 24.293 9.144 ;
     RECT  24.253 2.16 24.323 6.264 ;
     RECT  24.293 9.12 24.325 9.144 ;
     RECT  24.323 2.832 24.371 5.832 ;
     RECT  24.325 9.12 24.371 9.624 ;
     RECT  23.939 10.848 24.373 11.352 ;
     RECT  24.371 2.832 24.467 5.784 ;
     RECT  24.371 9.12 24.515 9.144 ;
     RECT  24.293 7.392 24.563 7.992 ;
     RECT  24.373 10.848 24.617 11.4 ;
     RECT  23.893 0.192 24.757 1.032 ;
     RECT  24.757 0.192 24.803 1.704 ;
     RECT  24.617 10.848 24.949 11.352 ;
     RECT  24.949 10.8 25.013 11.352 ;
     RECT  25.013 10.848 25.229 11.352 ;
     RECT  24.467 2.832 25.285 5.4 ;
     RECT  25.229 10.896 25.409 11.352 ;
     RECT  25.405 9.36 25.475 9.384 ;
     RECT  25.285 2.208 25.513 5.4 ;
     RECT  24.563 7.44 25.525 7.992 ;
     RECT  25.525 7.44 25.621 9.144 ;
     RECT  25.621 7.344 25.667 9.144 ;
     RECT  25.667 7.344 25.733 8.904 ;
     RECT  25.513 2.208 25.763 6.312 ;
     RECT  24.803 0.192 25.873 1.128 ;
     RECT  25.763 2.208 25.873 5.112 ;
     RECT  25.409 11.328 25.877 11.352 ;
     RECT  25.873 0.192 25.955 5.112 ;
     RECT  25.763 6.288 25.957 6.312 ;
     RECT  25.733 7.344 25.957 8.568 ;
     RECT  25.957 6.288 26.003 8.568 ;
     RECT  26.003 6.288 26.147 7.416 ;
     RECT  25.955 2.112 26.243 5.112 ;
     RECT  26.269 10.272 26.485 10.296 ;
     RECT  26.243 2.784 26.809 5.112 ;
     RECT  26.485 10.272 27.013 10.872 ;
     RECT  26.147 6.72 27.061 7.416 ;
     RECT  26.003 8.544 27.061 8.568 ;
     RECT  27.013 10.272 27.109 11.496 ;
     RECT  26.809 2.784 27.205 5.304 ;
     RECT  27.061 6.72 27.205 8.568 ;
     RECT  25.955 0.192 27.248 1.128 ;
     RECT  27.205 2.784 27.248 8.568 ;
     RECT  27.109 9.744 27.248 11.496 ;
     RECT  27.248 0.192 27.299 11.496 ;
     RECT  27.299 0.192 27.683 11.352 ;
     RECT  27.683 7.872 27.779 11.352 ;
     RECT  27.779 7.872 28.403 9.096 ;
     RECT  28.403 7.872 28.433 8.568 ;
     RECT  27.683 0.192 28.681 6.888 ;
     RECT  28.433 7.872 28.681 7.944 ;
     RECT  28.681 0.192 28.787 7.944 ;
     RECT  28.787 0.192 28.865 6.312 ;
     RECT  28.787 7.44 29.027 7.944 ;
     RECT  29.027 7.536 29.117 7.944 ;
     RECT  27.779 10.272 29.185 11.352 ;
     RECT  29.185 10.176 29.267 11.352 ;
     RECT  29.401 7.968 29.461 7.992 ;
     RECT  29.267 10.272 29.507 11.352 ;
     RECT  29.507 10.656 29.557 11.352 ;
     RECT  29.557 10.656 29.729 11.4 ;
     RECT  29.729 10.656 29.873 11.352 ;
     RECT  29.461 7.968 29.941 8.376 ;
     RECT  28.865 0.192 30.037 4.536 ;
     RECT  28.865 5.712 30.037 6.312 ;
     RECT  30.037 0.192 30.085 6.312 ;
     RECT  30.085 0.192 30.193 6.792 ;
     RECT  29.941 7.968 30.229 9.096 ;
     RECT  30.193 0.192 30.413 6.84 ;
     RECT  30.229 7.968 30.449 9.624 ;
     RECT  30.413 2.112 30.517 6.84 ;
     RECT  30.517 2.112 30.709 6.936 ;
     RECT  30.449 7.968 30.709 9.144 ;
     RECT  30.709 2.112 30.755 9.144 ;
     RECT  29.873 10.752 30.755 11.352 ;
     RECT  30.755 2.112 31.187 9.096 ;
     RECT  31.187 2.112 31.427 7.416 ;
     RECT  30.413 0.192 31.429 1.08 ;
     RECT  31.429 0.192 31.489 1.128 ;
     RECT  31.427 2.112 31.489 5.784 ;
     RECT  31.427 6.816 31.493 7.416 ;
     RECT  30.755 11.328 31.669 11.352 ;
     RECT  31.669 11.328 31.705 11.688 ;
     RECT  31.705 11.328 31.763 11.784 ;
     RECT  31.763 11.328 31.765 11.496 ;
     RECT  31.765 10.8 31.861 11.496 ;
     RECT  31.187 8.544 32.029 9.096 ;
     RECT  31.861 10.176 32.029 11.496 ;
     RECT  31.493 7.248 32.353 7.416 ;
     RECT  32.353 7.248 32.389 7.464 ;
     RECT  32.029 8.544 32.389 11.496 ;
     RECT  31.489 0.192 32.437 5.784 ;
     RECT  32.437 0.192 32.485 6.216 ;
     RECT  32.389 7.248 32.485 11.496 ;
     RECT  32.485 0.192 32.675 11.496 ;
     RECT  32.675 0.192 32.944 11.352 ;
     RECT  32.944 8.448 33.005 8.52 ;
     RECT  32.944 0.192 33.059 7.368 ;
     RECT  33.059 0.192 33.113 6.024 ;
     RECT  32.944 10.848 33.293 11.352 ;
     RECT  33.005 8.496 33.635 8.52 ;
     RECT  33.113 0.192 33.827 5.928 ;
     RECT  33.293 10.848 33.869 10.872 ;
     RECT  33.827 0.192 33.905 1.176 ;
     RECT  33.925 8.544 33.977 9.096 ;
     RECT  33.059 7.344 34.165 7.368 ;
     RECT  33.977 8.544 34.211 8.664 ;
     RECT  33.827 2.208 34.261 5.928 ;
     RECT  34.165 7.248 34.261 7.368 ;
     RECT  34.261 2.208 34.369 7.368 ;
     RECT  34.369 2.208 34.409 7.464 ;
     RECT  33.973 10.8 34.549 10.824 ;
     RECT  34.549 9.696 34.595 10.824 ;
     RECT  34.595 10.752 34.697 10.824 ;
     RECT  34.409 7.44 34.741 7.464 ;
     RECT  34.409 2.208 34.787 6.312 ;
     RECT  34.595 9.696 34.787 9.72 ;
     RECT  33.905 0.192 35.077 1.08 ;
     RECT  35.077 0.192 35.125 1.128 ;
     RECT  34.787 2.208 35.125 5.4 ;
     RECT  34.697 10.8 35.125 10.824 ;
     RECT  35.125 0.192 35.417 5.4 ;
     RECT  35.417 0.192 35.459 4.584 ;
     RECT  35.125 10.8 35.809 11.064 ;
     RECT  34.741 7.44 35.845 7.896 ;
     RECT  35.509 8.88 35.845 8.904 ;
     RECT  35.809 10.272 35.893 11.064 ;
     RECT  35.845 7.44 35.989 8.904 ;
     RECT  35.917 5.712 36.037 5.736 ;
     RECT  36.037 5.712 36.229 5.928 ;
     RECT  35.989 7.344 36.275 8.904 ;
     RECT  36.229 5.712 36.277 6.264 ;
     RECT  36.277 9.072 36.353 9.096 ;
     RECT  36.277 5.712 36.421 6.36 ;
     RECT  36.275 7.344 36.421 7.992 ;
     RECT  35.893 10.272 36.421 11.352 ;
     RECT  36.421 5.712 36.467 7.992 ;
     RECT  36.421 10.176 36.565 11.352 ;
     RECT  36.467 6.816 36.569 7.992 ;
     RECT  36.569 7.392 36.605 7.992 ;
     RECT  36.565 9.696 36.677 11.352 ;
     RECT  35.459 0.192 36.745 4.536 ;
     RECT  36.745 0.192 36.893 5.64 ;
     RECT  36.893 0.192 36.947 5.256 ;
     RECT  36.947 2.112 37.043 5.256 ;
     RECT  36.605 7.44 37.621 7.992 ;
     RECT  36.677 9.696 37.621 10.248 ;
     RECT  36.677 11.328 37.717 11.352 ;
     RECT  37.621 9.12 37.813 10.248 ;
     RECT  37.717 11.328 37.813 11.496 ;
     RECT  36.947 0.192 38.048 1.08 ;
     RECT  37.043 2.256 38.048 5.256 ;
     RECT  37.621 7.344 38.048 7.992 ;
     RECT  37.813 9.12 38.048 11.496 ;
     RECT  38.048 0.192 38.344 11.496 ;
     RECT  38.344 7.44 38.483 8.52 ;
     RECT  38.344 10.224 38.483 11.496 ;
     RECT  38.344 0.192 39.125 6.312 ;
     RECT  39.125 0.192 39.155 3.96 ;
     RECT  38.483 7.968 39.397 8.52 ;
     RECT  38.483 10.224 39.397 11.064 ;
     RECT  39.397 7.968 39.445 11.064 ;
     RECT  39.445 7.92 39.661 11.064 ;
     RECT  39.661 7.44 39.665 11.064 ;
     RECT  39.125 5.04 39.805 6.312 ;
     RECT  39.665 7.44 39.805 9.768 ;
     RECT  39.665 10.848 39.877 11.064 ;
     RECT  39.805 5.04 39.953 9.768 ;
     RECT  39.953 5.04 40.093 6.744 ;
     RECT  40.093 4.56 40.097 6.744 ;
     RECT  40.097 4.56 40.211 6.312 ;
     RECT  39.155 0.192 40.405 3.528 ;
     RECT  40.211 4.56 40.405 5.64 ;
     RECT  39.953 7.968 40.493 9.768 ;
     RECT  39.877 10.848 40.501 11.352 ;
     RECT  40.501 10.848 40.673 11.4 ;
     RECT  40.673 10.848 40.885 10.92 ;
     RECT  40.493 9.744 41.065 9.768 ;
     RECT  40.885 10.8 41.065 10.92 ;
     RECT  40.405 0.192 41.105 5.64 ;
     RECT  41.065 9.744 41.123 10.92 ;
     RECT  41.105 2.304 41.461 5.64 ;
     RECT  41.269 6.864 41.557 6.888 ;
     RECT  41.461 2.304 41.605 5.736 ;
     RECT  41.557 6.816 41.605 6.888 ;
     RECT  40.493 7.968 41.845 8.616 ;
     RECT  41.845 7.968 41.897 9.096 ;
     RECT  41.897 7.968 42.005 8.52 ;
     RECT  41.123 10.08 42.037 10.92 ;
     RECT  42.037 10.08 42.073 11.688 ;
     RECT  41.605 2.304 42.085 6.888 ;
     RECT  42.005 7.968 42.085 7.992 ;
     RECT  41.105 0.192 42.109 1.128 ;
     RECT  42.085 2.304 42.109 7.992 ;
     RECT  42.073 10.08 42.131 11.784 ;
     RECT  42.109 0.192 42.179 7.992 ;
     RECT  42.179 0.192 42.185 7.464 ;
     RECT  42.131 10.08 42.937 11.352 ;
     RECT  43.009 8.544 43.045 8.568 ;
     RECT  43.045 8.544 43.093 8.664 ;
     RECT  42.937 9.696 43.093 11.352 ;
     RECT  42.185 0.192 43.153 7.368 ;
     RECT  43.153 0.192 43.237 7.464 ;
     RECT  43.093 8.544 43.237 11.352 ;
     RECT  43.237 0.192 43.381 11.352 ;
     RECT  43.381 0.192 43.744 11.496 ;
     RECT  43.744 7.968 43.859 11.496 ;
     RECT  43.859 7.968 43.907 11.208 ;
     RECT  43.907 7.968 44.435 11.064 ;
     RECT  44.435 8.544 44.723 8.904 ;
     RECT  43.744 0.192 44.737 4.632 ;
     RECT  43.744 5.712 44.737 6.312 ;
     RECT  44.737 0.192 44.849 6.312 ;
     RECT  44.435 10.848 44.917 11.064 ;
     RECT  44.737 7.44 45.061 7.464 ;
     RECT  45.061 6.528 45.397 7.464 ;
     RECT  44.917 10.848 45.425 11.352 ;
     RECT  45.397 6.528 45.569 7.896 ;
     RECT  45.425 10.896 45.731 11.352 ;
     RECT  45.569 6.528 45.853 7.464 ;
     RECT  44.723 8.88 45.877 8.904 ;
     RECT  44.849 0.192 46.069 5.256 ;
     RECT  45.853 6.288 46.069 7.464 ;
     RECT  45.877 8.88 46.105 9.096 ;
     RECT  46.069 0.192 46.163 7.464 ;
     RECT  46.105 8.88 46.249 9.432 ;
     RECT  45.731 10.896 46.453 11.112 ;
     RECT  46.249 8.544 46.753 9.432 ;
     RECT  46.453 10.8 46.753 11.112 ;
     RECT  46.163 2.832 46.981 7.464 ;
     RECT  46.753 8.544 46.981 11.112 ;
     RECT  46.163 0.192 47.221 1.8 ;
     RECT  46.981 2.832 47.221 11.112 ;
     RECT  47.221 0.192 47.297 11.352 ;
     RECT  47.297 9.696 47.315 11.352 ;
     RECT  47.297 0.192 47.333 8.376 ;
     RECT  47.333 0.192 47.369 7.896 ;
     RECT  47.369 7.248 47.441 7.896 ;
     RECT  47.315 10.368 47.693 11.352 ;
     RECT  47.693 10.8 47.797 11.352 ;
     RECT  47.369 0.192 48.373 4.152 ;
     RECT  47.369 5.136 48.373 6.264 ;
     RECT  48.373 0.192 48.409 6.264 ;
     RECT  47.441 7.44 48.409 7.896 ;
     RECT  48.409 0.192 48.565 7.896 ;
     RECT  48.565 0.192 48.613 8.472 ;
     RECT  47.797 10.8 48.661 11.4 ;
     RECT  48.613 0.192 48.709 8.568 ;
     RECT  48.517 9.6 48.709 9.624 ;
     RECT  48.661 10.8 48.709 11.544 ;
     RECT  48.709 0.192 48.995 11.544 ;
     RECT  48.995 0.192 49.313 11.352 ;
     RECT  49.313 0.192 49.421 10.296 ;
     RECT  49.421 7.968 49.523 10.296 ;
     RECT  49.523 7.968 49.781 9.144 ;
     RECT  49.421 0.192 49.955 6.888 ;
     RECT  49.523 10.272 50.033 10.296 ;
     RECT  49.313 11.328 50.293 11.352 ;
     RECT  49.955 1.68 50.465 6.888 ;
     RECT  50.293 11.328 50.485 11.4 ;
     RECT  49.781 7.968 50.497 7.992 ;
     RECT  50.465 1.68 50.537 6.408 ;
     RECT  49.781 9.12 50.821 9.144 ;
     RECT  49.955 0.192 51.061 0.312 ;
     RECT  50.537 1.68 51.061 1.704 ;
     RECT  51.061 0.192 51.185 1.704 ;
     RECT  50.821 9.12 51.203 9.72 ;
     RECT  50.537 2.88 51.293 6.408 ;
     RECT  51.203 9.12 51.299 9.144 ;
     RECT  50.485 10.848 51.541 11.4 ;
     RECT  50.497 7.44 51.685 7.992 ;
     RECT  51.685 7.44 51.779 8.904 ;
     RECT  51.541 10.272 51.797 11.4 ;
     RECT  51.779 8.544 51.827 8.904 ;
     RECT  51.185 1.584 51.829 1.704 ;
     RECT  51.827 8.64 51.875 8.904 ;
     RECT  51.797 10.272 51.875 11.352 ;
     RECT  51.875 8.88 51.905 8.904 ;
     RECT  51.829 1.584 51.925 1.752 ;
     RECT  51.293 2.88 51.925 6.316 ;
     RECT  51.875 10.8 52.121 11.352 ;
     RECT  51.185 0.192 52.165 0.312 ;
     RECT  51.925 1.584 52.165 6.316 ;
     RECT  52.165 0.192 52.229 6.316 ;
     RECT  52.229 1.488 52.355 6.316 ;
     RECT  52.355 1.488 52.403 4.296 ;
     RECT  52.355 5.712 52.405 6.316 ;
     RECT  52.153 7.296 52.405 7.368 ;
     RECT  52.229 0.192 52.451 0.312 ;
     RECT  52.405 5.712 52.451 7.368 ;
     RECT  52.789 9.648 52.985 9.672 ;
     RECT  52.451 7.296 53.233 7.368 ;
     RECT  53.233 7.296 53.305 7.848 ;
     RECT  52.121 10.848 53.365 10.92 ;
     RECT  52.403 2.784 53.413 4.296 ;
     RECT  52.451 5.712 53.413 6.312 ;
     RECT  53.413 2.736 53.461 6.312 ;
     RECT  53.305 7.296 53.461 7.992 ;
     RECT  52.451 0.192 53.485 0.216 ;
     RECT  52.403 1.488 53.485 1.704 ;
     RECT  53.485 0.192 53.509 1.704 ;
     RECT  53.461 2.736 53.509 7.992 ;
     RECT  53.365 10.848 53.557 11.352 ;
     RECT  53.509 0.192 53.989 7.992 ;
     RECT  53.269 9.12 53.989 9.144 ;
     RECT  53.989 0.192 54.248 9.144 ;
     RECT  53.557 10.224 54.248 11.352 ;
     RECT  54.248 0.192 54.325 11.352 ;
     RECT  54.325 0.192 54.544 11.496 ;
     RECT  54.544 0.192 54.659 8.856 ;
     RECT  54.659 0.192 54.707 6.888 ;
     RECT  54.659 7.968 54.821 8.856 ;
     RECT  54.544 10.272 54.857 11.496 ;
     RECT  54.821 7.968 55.181 8.52 ;
     RECT  54.707 2.256 55.217 6.888 ;
     RECT  55.217 5.712 55.331 6.888 ;
     RECT  54.707 0.192 55.361 1.176 ;
     RECT  54.857 10.272 55.433 11.4 ;
     RECT  55.217 2.256 55.523 4.584 ;
     RECT  55.361 0.576 55.861 1.176 ;
     RECT  55.523 2.256 55.861 4.536 ;
     RECT  55.433 10.272 55.861 11.352 ;
     RECT  55.181 7.968 56.041 7.992 ;
     RECT  56.041 7.44 56.245 7.992 ;
     RECT  55.861 10.224 56.365 11.352 ;
     RECT  55.331 5.712 56.389 6.264 ;
     RECT  56.365 9.936 56.435 11.352 ;
     RECT  55.861 0.576 56.437 4.536 ;
     RECT  56.245 7.44 56.509 8.376 ;
     RECT  56.509 7.44 56.725 8.568 ;
     RECT  56.389 5.712 56.869 6.312 ;
     RECT  56.725 7.44 56.869 9.144 ;
     RECT  56.869 5.712 56.915 9.144 ;
     RECT  56.915 5.712 56.965 6.312 ;
     RECT  56.435 10.272 57.013 11.352 ;
     RECT  56.965 5.664 57.155 6.312 ;
     RECT  57.155 5.664 57.197 6.264 ;
     RECT  56.437 0.192 57.265 4.536 ;
     RECT  57.197 5.664 57.265 6.024 ;
     RECT  56.915 7.344 57.587 9.144 ;
     RECT  57.013 10.272 57.587 11.4 ;
     RECT  57.587 8.352 57.665 9.144 ;
     RECT  57.587 10.848 57.701 11.4 ;
     RECT  57.665 8.544 57.875 9.144 ;
     RECT  57.587 7.344 57.881 7.368 ;
     RECT  57.701 10.848 57.953 11.352 ;
     RECT  57.265 0.192 58.019 6.024 ;
     RECT  57.875 8.544 58.025 8.904 ;
     RECT  58.025 8.88 58.169 8.904 ;
     RECT  57.953 10.848 58.837 10.92 ;
     RECT  58.837 9.12 58.933 9.384 ;
     RECT  58.837 10.56 58.933 10.92 ;
     RECT  58.693 7.824 58.993 7.848 ;
     RECT  58.019 0.192 59.077 4.104 ;
     RECT  58.019 5.136 59.077 6.024 ;
     RECT  58.993 7.44 59.125 7.848 ;
     RECT  58.933 9.12 59.125 10.92 ;
     RECT  59.077 0.192 59.137 6.264 ;
     RECT  59.125 7.44 59.173 7.992 ;
     RECT  59.125 9.12 59.173 11.352 ;
     RECT  59.137 0.192 59.209 6.312 ;
     RECT  59.173 7.44 59.209 11.352 ;
     RECT  59.209 0.192 59.317 11.352 ;
     RECT  59.317 0.192 59.461 11.448 ;
     RECT  59.461 0.192 59.747 11.496 ;
     RECT  59.747 0.192 59.944 11.448 ;
     RECT  59.944 10.848 59.969 11.448 ;
     RECT  59.944 7.248 60.005 7.944 ;
     RECT  59.969 10.848 60.221 11.352 ;
     RECT  60.005 7.248 60.227 7.896 ;
     RECT  60.221 10.848 60.257 11.208 ;
     RECT  60.227 7.44 60.973 7.896 ;
     RECT  59.944 9.072 61.045 9.72 ;
     RECT  60.257 10.848 61.045 10.872 ;
     RECT  61.045 9.072 61.237 10.872 ;
     RECT  59.944 0.192 61.285 5.736 ;
     RECT  60.973 7.44 61.297 7.992 ;
     RECT  61.237 9.072 61.297 11.352 ;
     RECT  61.285 0.192 61.405 6.264 ;
     RECT  61.405 0.192 61.477 6.312 ;
     RECT  61.297 7.44 61.477 11.352 ;
     RECT  61.477 0.192 62.147 11.352 ;
     RECT  62.147 10.8 62.243 11.352 ;
     RECT  62.147 0.192 62.633 9.816 ;
     RECT  62.633 0.192 62.885 9.144 ;
     RECT  62.243 10.8 62.885 11.064 ;
     RECT  62.885 0.192 63.251 8.568 ;
     RECT  62.885 10.8 63.277 10.872 ;
     RECT  63.251 0.192 63.353 8.52 ;
     RECT  63.353 0.192 63.533 6.84 ;
     RECT  63.353 7.968 63.731 8.52 ;
     RECT  63.533 0.192 63.749 5.928 ;
     RECT  63.731 8.064 63.857 8.52 ;
     RECT  63.277 10.32 63.925 10.872 ;
     RECT  63.925 10.32 63.971 11.352 ;
     RECT  63.971 10.32 64.357 11.064 ;
     RECT  63.749 0.192 64.741 5.304 ;
     RECT  63.857 8.304 64.741 8.52 ;
     RECT  64.357 9.696 64.741 11.064 ;
     RECT  64.741 0.192 64.789 5.64 ;
     RECT  64.741 8.304 64.861 11.064 ;
     RECT  64.609 6.816 64.885 6.84 ;
     RECT  64.861 7.968 64.885 11.064 ;
     RECT  64.789 0.192 64.933 5.736 ;
     RECT  64.885 6.816 64.933 11.064 ;
     RECT  64.933 0.192 65.005 11.064 ;
     RECT  65.005 0.192 65.123 11.496 ;
     RECT  65.123 0.192 65.152 11.352 ;
     RECT  65.152 0.192 65.555 11.208 ;
     RECT  65.555 5.616 66.269 11.208 ;
     RECT  66.269 5.712 66.409 11.208 ;
     RECT  66.409 5.712 66.611 11.352 ;
     RECT  66.611 8.496 66.659 11.352 ;
     RECT  66.659 8.496 66.737 9.672 ;
     RECT  66.611 5.712 66.845 7.464 ;
     RECT  66.737 8.544 67.133 9.672 ;
     RECT  65.555 0.192 67.141 4.584 ;
     RECT  67.141 0.192 67.169 4.632 ;
     RECT  67.133 8.544 67.187 9.144 ;
     RECT  67.187 8.544 67.277 8.568 ;
     RECT  67.169 2.112 67.477 4.632 ;
     RECT  66.845 5.712 67.477 7.416 ;
     RECT  67.477 2.112 67.673 7.416 ;
     RECT  67.673 5.712 67.849 7.416 ;
     RECT  67.849 5.712 67.907 7.944 ;
     RECT  67.907 5.712 68.051 7.464 ;
     RECT  66.659 10.848 68.717 11.352 ;
     RECT  68.821 8.976 68.867 9 ;
     RECT  68.051 5.712 68.917 7.272 ;
     RECT  68.717 10.848 68.969 10.92 ;
     RECT  68.917 5.664 69.013 7.272 ;
     RECT  69.013 5.664 69.037 7.608 ;
     RECT  69.037 5.664 69.107 7.992 ;
     RECT  68.969 10.848 69.109 10.872 ;
     RECT  67.169 0.192 69.157 1.128 ;
     RECT  67.673 2.112 69.157 4.68 ;
     RECT  69.109 10.224 69.185 10.872 ;
     RECT  69.157 0.192 69.301 4.68 ;
     RECT  69.107 5.664 69.301 7.608 ;
     RECT  69.301 0.192 70.069 7.608 ;
     RECT  70.069 0.192 70.165 7.992 ;
     RECT  69.493 9.072 70.165 9.096 ;
     RECT  69.185 10.32 70.165 10.872 ;
     RECT  70.165 0.192 70.261 9.096 ;
     RECT  70.165 10.32 70.261 11.208 ;
     RECT  70.261 0.192 70.309 11.208 ;
     RECT  70.309 0.192 70.744 11.496 ;
     RECT  70.744 10.8 70.837 11.496 ;
     RECT  70.837 10.8 70.873 11.688 ;
     RECT  70.873 10.8 70.931 11.784 ;
     RECT  70.744 0.192 71.237 9.72 ;
     RECT  71.237 0.192 71.525 3.768 ;
     RECT  71.237 5.088 71.651 9.72 ;
     RECT  71.651 5.088 71.705 9 ;
     RECT  70.931 10.8 71.809 11.352 ;
     RECT  71.705 5.088 72.179 8.904 ;
     RECT  71.525 1.68 72.205 3.768 ;
     RECT  72.179 7.968 72.245 8.904 ;
     RECT  72.205 1.68 72.277 3.864 ;
     RECT  72.179 5.088 72.277 6.744 ;
     RECT  71.525 0.192 72.709 0.6 ;
     RECT  72.277 1.68 72.709 6.744 ;
     RECT  72.709 0.192 72.749 6.744 ;
     RECT  72.749 5.712 73.141 6.744 ;
     RECT  72.245 8.304 73.141 8.904 ;
     RECT  73.141 5.712 73.145 6.84 ;
     RECT  73.145 6.816 73.217 6.84 ;
     RECT  73.141 8.304 73.433 9.096 ;
     RECT  73.433 8.544 73.505 9.096 ;
     RECT  71.809 10.272 73.505 11.352 ;
     RECT  73.145 5.712 73.541 5.736 ;
     RECT  73.505 9.072 73.613 9.096 ;
     RECT  72.749 0.192 73.765 4.296 ;
     RECT  73.765 0.192 73.865 5.64 ;
     RECT  73.865 5.088 73.901 5.64 ;
     RECT  73.505 10.272 74.101 10.92 ;
     RECT  73.789 6.864 74.365 6.888 ;
     RECT  74.101 10.224 74.485 10.92 ;
     RECT  74.365 6.864 74.533 7.464 ;
     RECT  74.533 6.816 74.585 7.464 ;
     RECT  73.901 5.616 74.677 5.64 ;
     RECT  74.485 10.224 74.677 11.352 ;
     RECT  74.677 9.792 74.761 11.352 ;
     RECT  74.761 9.696 74.869 11.352 ;
     RECT  73.865 0.192 74.965 4.056 ;
     RECT  74.677 5.616 74.965 6.312 ;
     RECT  74.869 9.648 75.061 11.352 ;
     RECT  74.585 7.44 75.205 7.464 ;
     RECT  75.061 9.648 75.637 11.4 ;
     RECT  75.205 7.44 75.733 7.992 ;
     RECT  75.637 9.648 75.805 11.448 ;
     RECT  74.965 0.192 75.848 6.312 ;
     RECT  75.733 7.44 75.848 8.52 ;
     RECT  75.805 9.648 75.848 11.496 ;
     RECT  75.848 0.192 75.875 11.496 ;
     RECT  75.875 0.192 76.144 11.448 ;
     RECT  76.144 9.648 76.205 11.448 ;
     RECT  76.144 0.192 76.403 7.464 ;
     RECT  76.403 0.192 77.365 5.16 ;
     RECT  76.403 6.24 77.389 7.464 ;
     RECT  77.269 8.496 77.389 8.52 ;
     RECT  77.389 6.24 77.537 8.52 ;
     RECT  77.365 0.192 77.557 5.256 ;
     RECT  77.537 6.24 77.557 7.992 ;
     RECT  76.205 9.648 77.785 11.064 ;
     RECT  77.557 0.192 77.891 7.992 ;
     RECT  77.785 9.12 77.941 11.064 ;
     RECT  77.891 6.864 77.987 7.368 ;
     RECT  77.987 7.248 78.005 7.368 ;
     RECT  77.941 9.12 78.041 11.352 ;
     RECT  78.041 9.12 78.221 11.064 ;
     RECT  77.891 0.192 78.659 5.784 ;
     RECT  78.221 9.12 78.797 9.384 ;
     RECT  78.005 7.344 78.973 7.368 ;
     RECT  78.221 10.8 79.049 11.064 ;
     RECT  79.049 10.848 79.093 11.064 ;
     RECT  78.797 9.12 79.187 9.144 ;
     RECT  78.973 6.864 79.571 7.368 ;
     RECT  79.571 7.104 79.589 7.368 ;
     RECT  79.093 10.848 79.661 11.352 ;
     RECT  79.661 10.848 79.805 10.92 ;
     RECT  78.659 0.192 79.861 5.688 ;
     RECT  79.189 8.544 80.129 8.568 ;
     RECT  80.053 7.392 80.533 7.416 ;
     RECT  79.861 0.192 80.629 5.976 ;
     RECT  80.533 7.392 80.629 7.848 ;
     RECT  79.805 10.848 80.629 10.872 ;
     RECT  80.629 10.8 80.821 10.872 ;
     RECT  80.821 10.8 80.917 11.352 ;
     RECT  80.917 10.704 81.013 11.496 ;
     RECT  81.013 10.704 81.061 11.688 ;
     RECT  81.061 10.704 81.107 11.784 ;
     RECT  80.629 0.192 81.248 7.848 ;
     RECT  81.107 10.704 81.248 11.496 ;
     RECT  81.248 0.192 81.251 11.496 ;
     RECT  81.251 0.192 81.352 11.352 ;
     RECT  81.352 0.192 81.785 11.208 ;
     RECT  81.785 0.192 82.115 11.064 ;
     RECT  82.115 7.44 82.289 11.064 ;
     RECT  82.289 10.944 82.325 11.064 ;
     RECT  82.115 0.192 82.643 6.264 ;
     RECT  82.289 7.44 82.643 9.768 ;
     RECT  82.325 11.04 82.933 11.064 ;
     RECT  82.643 0.192 82.979 5.736 ;
     RECT  82.643 7.44 83.219 9.096 ;
     RECT  82.933 11.04 83.317 11.352 ;
     RECT  83.219 7.44 83.509 8.568 ;
     RECT  83.509 6.816 83.699 8.568 ;
     RECT  82.979 0.192 83.987 5.16 ;
     RECT  83.699 6.816 84.377 8.472 ;
     RECT  83.317 10.848 84.469 11.352 ;
     RECT  84.377 7.968 84.611 8.472 ;
     RECT  84.611 7.968 84.755 7.992 ;
     RECT  84.377 6.816 84.841 6.84 ;
     RECT  85.021 9.648 85.091 9.672 ;
     RECT  83.987 0.192 85.141 4.968 ;
     RECT  84.841 6.288 85.381 6.84 ;
     RECT  85.381 6.288 85.417 6.888 ;
     RECT  85.165 9.12 85.475 9.144 ;
     RECT  85.141 0.192 85.477 5.16 ;
     RECT  85.417 6.288 85.477 7.464 ;
     RECT  84.469 10.8 85.493 11.352 ;
     RECT  85.477 0.192 85.523 7.464 ;
     RECT  85.493 10.8 85.621 10.872 ;
     RECT  85.621 10.224 86.581 10.872 ;
     RECT  85.523 0.192 86.648 7.416 ;
     RECT  86.581 10.224 86.648 11.496 ;
     RECT  86.648 0.192 86.773 11.496 ;
     RECT  86.773 0.192 86.825 11.544 ;
     RECT  86.825 0.192 87.041 11.496 ;
     RECT  87.041 0.192 87.203 11.352 ;
     RECT  87.203 0.192 87.221 9.192 ;
     RECT  87.221 0.192 87.293 4.296 ;
     RECT  87.203 10.176 88.085 11.352 ;
     RECT  88.085 10.176 88.211 10.2 ;
     RECT  87.293 0.192 88.261 4.008 ;
     RECT  88.085 11.328 88.265 11.352 ;
     RECT  87.221 5.664 88.297 9.192 ;
     RECT  88.297 5.664 88.333 9.72 ;
     RECT  88.333 5.28 88.355 9.72 ;
     RECT  88.261 0.192 88.513 4.056 ;
     RECT  88.355 5.28 88.513 9.24 ;
     RECT  88.513 0.192 88.547 9.24 ;
     RECT  88.547 0.192 88.589 6.84 ;
     RECT  88.547 7.872 88.625 9.24 ;
     RECT  88.625 7.968 88.913 9.24 ;
     RECT  88.309 11.376 89.269 11.4 ;
     RECT  88.913 8.448 89.417 9.24 ;
     RECT  88.589 0.192 89.653 5.352 ;
     RECT  89.653 0.192 89.701 5.4 ;
     RECT  88.589 6.816 89.701 6.84 ;
     RECT  89.701 6.816 89.747 7.464 ;
     RECT  89.269 11.328 89.845 11.4 ;
     RECT  89.417 8.448 89.881 9.096 ;
     RECT  89.701 0.192 89.893 5.64 ;
     RECT  89.747 6.816 89.893 6.84 ;
     RECT  89.845 10.848 89.993 11.4 ;
     RECT  89.893 0.192 90.083 6.84 ;
     RECT  90.083 6.816 90.209 6.84 ;
     RECT  89.881 7.968 90.613 9.096 ;
     RECT  90.613 7.968 90.673 9.192 ;
     RECT  90.673 7.968 90.853 9.72 ;
     RECT  90.853 7.248 90.893 9.72 ;
     RECT  90.893 9.696 90.995 9.72 ;
     RECT  90.893 7.248 91.213 8.568 ;
     RECT  89.993 10.848 91.381 11.352 ;
     RECT  91.213 6.864 91.477 8.568 ;
     RECT  90.083 0.192 91.717 5.736 ;
     RECT  91.477 6.816 91.717 8.568 ;
     RECT  91.381 10.8 91.909 11.352 ;
     RECT  91.717 0.192 92.048 8.568 ;
     RECT  91.909 10.8 92.048 11.592 ;
     RECT  92.048 0.192 92.195 11.592 ;
     RECT  92.195 0.192 92.344 11.352 ;
     RECT  92.344 0.192 92.819 9.144 ;
     RECT  92.344 10.272 93.443 11.352 ;
     RECT  92.819 2.256 93.493 9.144 ;
     RECT  93.443 10.272 93.493 10.296 ;
     RECT  93.493 2.256 93.917 10.296 ;
     RECT  93.917 2.256 93.971 4.68 ;
     RECT  92.819 0.192 93.973 1.128 ;
     RECT  93.917 5.664 94.019 10.296 ;
     RECT  94.019 9.696 94.595 10.296 ;
     RECT  93.443 11.328 94.645 11.352 ;
     RECT  94.595 9.696 94.673 9.72 ;
     RECT  93.971 2.832 94.885 4.68 ;
     RECT  94.019 5.664 94.885 8.568 ;
     RECT  93.973 0.192 94.981 1.752 ;
     RECT  94.885 2.832 94.981 8.568 ;
     RECT  94.645 11.328 95.029 11.4 ;
     RECT  95.029 10.848 95.069 11.4 ;
     RECT  94.981 0.192 95.123 8.568 ;
     RECT  95.123 7.248 95.171 8.568 ;
     RECT  95.123 0.192 95.213 6.264 ;
     RECT  95.171 7.248 95.249 8.088 ;
     RECT  95.249 7.44 95.429 8.088 ;
     RECT  95.213 5.856 95.507 6.264 ;
     RECT  95.429 7.44 96.421 7.464 ;
     RECT  95.213 0.192 96.757 4.872 ;
     RECT  95.507 5.856 96.757 5.88 ;
     RECT  96.421 7.44 96.757 8.664 ;
     RECT  95.069 10.848 96.757 11.352 ;
     RECT  96.757 0.192 96.793 6.264 ;
     RECT  96.793 0.192 96.805 6.312 ;
     RECT  96.757 7.44 96.805 9.096 ;
     RECT  96.805 0.192 96.829 9.096 ;
     RECT  96.757 10.848 96.901 11.4 ;
     RECT  96.901 10.8 96.949 11.4 ;
     RECT  96.829 0.192 97.448 9.144 ;
     RECT  96.949 10.272 97.448 11.4 ;
     RECT  97.448 0.192 97.525 11.4 ;
     RECT  97.525 0.192 97.805 11.496 ;
     RECT  97.805 0.192 97.907 11.352 ;
     RECT  97.907 0.192 98.195 9.72 ;
     RECT  98.195 9.12 98.309 9.72 ;
     RECT  98.195 0.192 98.531 7.944 ;
     RECT  98.531 0.192 98.627 6.312 ;
     RECT  98.309 9.12 98.627 9.144 ;
     RECT  98.627 5.616 98.633 6.312 ;
     RECT  98.531 7.44 98.813 7.944 ;
     RECT  98.813 7.44 99.011 7.464 ;
     RECT  97.907 10.8 99.029 11.352 ;
     RECT  98.633 6 99.589 6.312 ;
     RECT  99.589 6 99.641 6.6 ;
     RECT  99.637 9.408 99.673 9.432 ;
     RECT  99.673 9.264 99.829 9.432 ;
     RECT  99.829 9.072 99.893 9.432 ;
     RECT  99.641 6 99.971 6.312 ;
     RECT  98.627 0.192 100.213 4.536 ;
     RECT  99.029 10.848 100.213 11.352 ;
     RECT  100.213 9.696 100.289 11.352 ;
     RECT  100.213 0.192 100.465 4.584 ;
     RECT  100.117 5.664 100.465 5.688 ;
     RECT  100.465 0.192 100.643 5.688 ;
     RECT  100.069 7.44 100.645 7.464 ;
     RECT  100.643 2.784 100.649 5.688 ;
     RECT  100.645 6.816 100.721 7.896 ;
     RECT  100.721 7.392 100.937 7.896 ;
     RECT  100.937 7.44 101.029 7.896 ;
     RECT  101.029 7.44 101.413 7.944 ;
     RECT  100.289 9.696 101.459 9.768 ;
     RECT  100.643 0.192 101.549 1.704 ;
     RECT  100.289 10.848 101.557 11.352 ;
     RECT  101.413 7.44 101.581 8.376 ;
     RECT  101.581 7.44 101.585 9.144 ;
     RECT  101.557 10.224 101.749 11.352 ;
     RECT  100.649 2.784 101.845 5.64 ;
     RECT  101.845 2.784 102.037 6.168 ;
     RECT  101.585 7.44 102.037 7.8 ;
     RECT  102.037 2.784 102.445 7.8 ;
     RECT  102.445 2.208 102.565 7.8 ;
     RECT  101.585 9.12 102.565 9.144 ;
     RECT  101.549 0.192 102.709 1.128 ;
     RECT  102.565 2.208 102.709 9.144 ;
     RECT  101.749 10.224 102.709 11.4 ;
     RECT  102.709 0.192 102.901 11.4 ;
     RECT  102.901 0.192 103.061 11.496 ;
     RECT  103.061 0.192 103.144 11.352 ;
     RECT  103.144 0.192 103.313 8.568 ;
     RECT  103.313 6.576 103.421 8.568 ;
     RECT  103.144 10.272 103.601 11.352 ;
     RECT  103.421 8.544 103.667 8.568 ;
     RECT  103.421 6.576 103.745 7.368 ;
     RECT  103.313 0.192 103.817 5.112 ;
     RECT  103.817 0.192 103.853 4.44 ;
     RECT  103.601 10.848 104.033 11.352 ;
     RECT  103.853 0.192 104.147 3.768 ;
     RECT  104.147 0.192 104.291 3.432 ;
     RECT  103.745 7.344 104.357 7.368 ;
     RECT  104.291 2.304 104.537 3.432 ;
     RECT  104.537 2.304 104.819 2.904 ;
     RECT  104.033 10.848 104.861 10.872 ;
     RECT  104.819 2.304 104.933 2.328 ;
     RECT  104.291 0.192 104.969 1.176 ;
     RECT  104.969 0.192 105.257 0.216 ;
    LAYER M5 ;
     RECT  0.384 0.144 104.664 0.181 ;
     RECT  0.384 0.181 104.904 0.227 ;
     RECT  0.384 0.227 52.44 0.323 ;
     RECT  79.68 0.227 104.904 0.323 ;
     RECT  0.384 0.323 22.728 0.517 ;
     RECT  0.24 0.517 22.728 0.707 ;
     RECT  0.24 0.707 0.552 1.093 ;
     RECT  0.144 1.093 0.552 1.285 ;
     RECT  53.568 0.227 78.552 1.285 ;
     RECT  23.904 0.323 52.2 1.477 ;
     RECT  53.568 1.285 78.6 1.525 ;
     RECT  79.872 0.323 104.904 1.525 ;
     RECT  23.904 1.477 52.44 1.573 ;
     RECT  53.568 1.525 104.904 1.573 ;
     RECT  0.096 1.285 0.552 1.669 ;
     RECT  1.536 0.707 22.728 1.669 ;
     RECT  23.904 1.573 104.904 1.669 ;
     RECT  0.096 1.669 104.904 2.339 ;
     RECT  0.096 2.339 104.808 2.435 ;
     RECT  0.096 2.435 14.04 2.915 ;
     RECT  15.024 2.435 104.808 2.915 ;
     RECT  0.096 2.915 7.368 3.107 ;
     RECT  8.448 2.915 14.04 3.397 ;
     RECT  15.024 2.915 104.52 3.397 ;
     RECT  8.448 3.397 104.52 3.443 ;
     RECT  8.448 3.443 104.136 3.779 ;
     RECT  8.448 3.779 103.752 4.259 ;
     RECT  8.448 4.259 88.968 4.331 ;
     RECT  90 4.259 103.752 4.459 ;
     RECT  90 4.459 103.704 4.595 ;
     RECT  0.144 3.107 7.368 5.077 ;
     RECT  8.448 4.331 73.848 5.077 ;
     RECT  0.144 5.077 73.848 5.171 ;
     RECT  0.144 5.171 36.84 5.219 ;
     RECT  74.832 4.331 88.968 5.365 ;
     RECT  90 4.595 103.656 5.365 ;
     RECT  64.752 5.171 73.848 5.605 ;
     RECT  74.832 5.365 103.656 5.605 ;
     RECT  0.144 5.219 1.56 5.747 ;
     RECT  64.752 5.605 103.656 5.803 ;
     RECT  79.008 5.803 103.656 5.987 ;
     RECT  48.336 5.171 63.768 6.059 ;
     RECT  2.784 5.219 36.84 6.229 ;
     RECT  38.04 5.171 47.352 6.229 ;
     RECT  48.336 6.059 57.576 6.229 ;
     RECT  2.16 6.229 36.84 6.315 ;
     RECT  38.04 6.229 57.576 6.323 ;
     RECT  80.64 5.987 103.656 6.323 ;
     RECT  2.784 6.315 36.84 6.515 ;
     RECT  64.752 5.803 77.976 6.851 ;
     RECT  73.296 6.851 77.976 6.899 ;
     RECT  80.64 6.323 85.512 7.093 ;
     RECT  14.064 6.515 36.84 7.333 ;
     RECT  38.04 6.323 47.256 7.333 ;
     RECT  48.24 6.323 57.576 7.333 ;
     RECT  74.4 6.899 77.976 7.333 ;
     RECT  79.008 5.987 79.56 7.333 ;
     RECT  86.496 6.323 103.656 7.333 ;
     RECT  74.4 7.333 79.56 7.381 ;
     RECT  80.544 7.093 85.512 7.381 ;
     RECT  86.496 7.333 104.28 7.381 ;
     RECT  14.064 7.333 47.256 7.475 ;
     RECT  48.24 7.333 57.864 7.475 ;
     RECT  74.4 7.381 104.28 7.475 ;
     RECT  2.784 6.515 13.08 7.717 ;
     RECT  59.088 6.059 63.768 7.797 ;
     RECT  48.384 7.475 57.864 7.813 ;
     RECT  58.896 7.797 63.768 7.813 ;
     RECT  48.384 7.813 63.768 7.851 ;
     RECT  0.24 5.747 1.128 7.861 ;
     RECT  48.384 7.851 59.952 7.915 ;
     RECT  14.064 7.475 19.944 8.003 ;
     RECT  59.136 7.915 59.952 8.003 ;
     RECT  2.688 7.717 13.08 8.181 ;
     RECT  14.064 8.003 18.744 8.181 ;
     RECT  60.96 7.851 63.768 8.293 ;
     RECT  64.752 6.851 72.312 8.293 ;
     RECT  2.688 8.181 18.744 8.339 ;
     RECT  21.072 7.475 47.256 8.341 ;
     RECT  0.24 7.861 1.608 8.437 ;
     RECT  75.168 7.475 82.632 8.485 ;
     RECT  83.664 7.475 95.448 8.485 ;
     RECT  75.168 8.485 95.448 8.491 ;
     RECT  73.296 6.899 73.32 8.579 ;
     RECT  75.168 8.491 84.312 8.579 ;
     RECT  99.696 7.475 104.28 8.579 ;
     RECT  2.688 8.339 13.08 8.675 ;
     RECT  96.432 7.475 98.616 8.675 ;
     RECT  0.144 8.437 1.608 8.723 ;
     RECT  60.96 8.293 72.312 9.003 ;
     RECT  14.064 8.339 18.744 9.061 ;
     RECT  19.92 8.003 19.944 9.061 ;
     RECT  68.16 9.003 72.312 9.061 ;
     RECT  21.072 8.341 47.304 9.155 ;
     RECT  48.384 7.915 58.008 9.155 ;
     RECT  60.96 9.003 67.176 9.155 ;
     RECT  75.168 8.579 83.208 9.155 ;
     RECT  85.44 8.491 95.448 9.155 ;
     RECT  96.768 8.675 98.616 9.155 ;
     RECT  57.552 9.155 58.008 9.349 ;
     RECT  59.184 8.003 59.952 9.349 ;
     RECT  99.696 8.579 103.152 9.397 ;
     RECT  14.064 9.061 19.944 9.589 ;
     RECT  21.072 9.155 24.36 9.589 ;
     RECT  57.552 9.349 59.952 9.589 ;
     RECT  60.96 9.155 67.08 9.589 ;
     RECT  84.288 8.579 84.312 9.589 ;
     RECT  85.44 9.155 93.768 9.589 ;
     RECT  1.584 8.723 1.608 9.637 ;
     RECT  2.688 8.675 2.712 9.637 ;
     RECT  3.84 8.675 13.08 9.637 ;
     RECT  75.168 9.155 77.496 9.637 ;
     RECT  14.064 9.589 24.36 9.643 ;
     RECT  79.872 9.155 83.208 9.643 ;
     RECT  96.768 9.155 98.184 9.643 ;
     RECT  78.528 9.155 78.744 9.707 ;
     RECT  1.584 9.637 13.08 9.731 ;
     RECT  14.064 9.643 19.992 9.731 ;
     RECT  51.168 9.155 53.016 9.731 ;
     RECT  74.88 9.637 77.496 9.781 ;
     RECT  0.144 8.723 0.552 9.827 ;
     RECT  1.728 9.731 13.08 9.925 ;
     RECT  84.288 9.589 93.768 10.165 ;
     RECT  94.848 9.155 95.448 10.165 ;
     RECT  51.744 9.731 53.016 10.213 ;
     RECT  54 9.155 56.424 10.213 ;
     RECT  68.16 9.061 73.176 10.213 ;
     RECT  74.688 9.781 77.496 10.213 ;
     RECT  68.16 10.213 77.496 10.261 ;
     RECT  78.528 9.707 78.552 10.261 ;
     RECT  99.648 9.397 103.152 10.261 ;
     RECT  104.256 8.579 104.28 10.261 ;
     RECT  51.744 10.213 56.424 10.293 ;
     RECT  57.552 9.589 67.08 10.293 ;
     RECT  25.344 9.155 47.304 10.357 ;
     RECT  48.384 9.155 50.136 10.357 ;
     RECT  1.728 9.925 13.56 10.741 ;
     RECT  14.832 9.731 19.992 10.741 ;
     RECT  0.24 9.827 0.552 10.789 ;
     RECT  1.728 10.741 19.992 10.789 ;
     RECT  25.344 10.357 50.136 10.789 ;
     RECT  68.16 10.261 78.552 10.789 ;
     RECT  79.872 9.643 83.16 10.789 ;
     RECT  96.768 9.643 98.136 10.789 ;
     RECT  99.648 10.261 104.28 10.789 ;
     RECT  0.24 10.789 20.184 10.837 ;
     RECT  21.504 9.643 23.928 10.837 ;
     RECT  24.96 10.789 50.136 10.837 ;
     RECT  51.744 10.293 67.08 10.837 ;
     RECT  68.16 10.789 83.16 10.837 ;
     RECT  84.288 10.165 95.448 10.837 ;
     RECT  96.768 10.789 104.28 10.837 ;
     RECT  0.24 10.837 104.664 11.363 ;
     RECT  0.384 11.363 104.664 11.728 ;
     RECT  31.728 11.728 31.752 11.795 ;
     RECT  42.096 11.728 42.12 11.795 ;
     RECT  70.896 11.728 70.92 11.795 ;
     RECT  81.072 11.728 81.096 11.795 ;
    LAYER M6 ;
     RECT  0 2.572 1.093 3.436 ;
     RECT  1.093 2.24 1.669 3.436 ;
     RECT  1.669 2.24 2.821 4.192 ;
     RECT  0.613 5.952 2.821 6.304 ;
     RECT  2.821 2.24 3.107 7.456 ;
     RECT  0 9.228 3.301 10.092 ;
     RECT  3.107 7.424 3.397 7.456 ;
     RECT  3.107 2.24 3.443 5.984 ;
     RECT  3.443 2.572 4.163 5.984 ;
     RECT  3.301 9.228 4.595 10.208 ;
     RECT  3.397 7.424 4.885 7.584 ;
     RECT  4.885 7.36 4.931 7.584 ;
     RECT  4.163 2.572 5.077 3.68 ;
     RECT  4.163 5.248 5.509 5.984 ;
     RECT  4.595 9.228 6.037 10.092 ;
     RECT  5.077 1.088 6.131 3.68 ;
     RECT  6.131 1.344 6.227 3.68 ;
     RECT  6.227 1.344 6.323 3.436 ;
     RECT  5.509 5.12 6.467 5.984 ;
     RECT  4.931 7.36 6.515 7.392 ;
     RECT  6.037 9.228 8.147 10.208 ;
     RECT  6.323 2.572 8.485 3.436 ;
     RECT  6.467 5.184 8.579 5.984 ;
     RECT  8.485 2.572 9.155 3.68 ;
     RECT  8.579 5.504 9.589 5.984 ;
     RECT  6.853 7.552 9.589 7.584 ;
     RECT  9.155 2.572 9.637 3.552 ;
     RECT  9.589 5.504 9.683 7.584 ;
     RECT  9.637 1.664 10.307 3.552 ;
     RECT  8.147 9.228 10.789 10.092 ;
     RECT  9.683 5.504 10.837 6.368 ;
     RECT  10.307 2.572 10.931 3.552 ;
     RECT  10.789 9.228 12.085 10.592 ;
     RECT  10.931 2.572 12.613 3.436 ;
     RECT  10.837 5.184 12.613 6.368 ;
     RECT  12.085 8.192 13.139 10.592 ;
     RECT  13.139 9.228 13.571 10.592 ;
     RECT  13.571 9.228 14.629 10.208 ;
     RECT  12.613 2.572 15.349 6.368 ;
     RECT  15.349 2.432 15.395 6.368 ;
     RECT  14.629 8.96 15.637 10.208 ;
     RECT  15.395 5.184 15.683 6.368 ;
     RECT  15.683 5.952 15.829 6.368 ;
     RECT  15.637 8.192 15.925 10.208 ;
     RECT  15.395 2.432 17.077 3.872 ;
     RECT  15.829 5.952 17.077 6.56 ;
     RECT  15.925 8.192 18.755 10.72 ;
     RECT  17.077 2.432 18.851 6.56 ;
     RECT  18.037 0.768 18.899 0.8 ;
     RECT  18.851 2.572 19.333 6.56 ;
     RECT  18.755 8.192 19.333 10.092 ;
     RECT  19.333 2.572 19.379 10.092 ;
     RECT  19.379 2.572 21.733 5.984 ;
     RECT  19.379 7.552 22.451 10.092 ;
     RECT  21.733 1.984 23.987 5.984 ;
     RECT  23.987 1.984 25.621 4.384 ;
     RECT  23.987 5.952 25.621 5.984 ;
     RECT  25.621 1.984 26.435 5.984 ;
     RECT  26.435 1.984 26.485 4.064 ;
     RECT  26.485 1.088 26.579 4.064 ;
     RECT  26.579 1.088 27.731 4 ;
     RECT  27.731 1.088 27.779 1.12 ;
     RECT  27.731 2.432 27.877 4 ;
     RECT  22.451 8.192 27.877 10.092 ;
     RECT  27.877 8.192 29.267 10.336 ;
     RECT  27.877 2.432 29.459 4.576 ;
     RECT  29.459 2.572 30.083 4.576 ;
     RECT  26.435 5.952 30.565 5.984 ;
     RECT  29.267 8.192 30.707 10.208 ;
     RECT  30.565 5.952 30.997 6.688 ;
     RECT  30.083 2.572 32.389 4.128 ;
     RECT  32.389 2.572 32.437 4.576 ;
     RECT  30.997 5.952 32.437 7.392 ;
     RECT  30.707 9.228 32.437 10.208 ;
     RECT  32.437 2.572 33.107 10.208 ;
     RECT  33.107 2.572 33.251 4.576 ;
     RECT  33.251 2.572 34.741 3.436 ;
     RECT  33.107 5.952 34.741 10.208 ;
     RECT  34.741 5.952 35.411 10.848 ;
     RECT  34.837 0.96 35.845 0.992 ;
     RECT  34.741 2.304 35.845 3.436 ;
     RECT  35.845 0.96 35.939 3.436 ;
     RECT  35.939 1.728 37.139 3.436 ;
     RECT  37.139 2.112 37.429 3.436 ;
     RECT  37.429 2.112 37.573 4.448 ;
     RECT  37.573 2.112 37.667 4.576 ;
     RECT  35.411 5.952 37.667 10.208 ;
     RECT  37.667 2.572 37.909 4.576 ;
     RECT  37.667 5.952 37.909 6.553 ;
     RECT  37.909 2.572 39.061 6.553 ;
     RECT  37.667 8.448 39.061 10.208 ;
     RECT  39.061 2.572 39.443 10.208 ;
     RECT  39.443 2.572 41.315 10.092 ;
     RECT  41.315 2.572 41.507 7.776 ;
     RECT  41.507 2.572 43.333 4.192 ;
     RECT  41.507 5.696 43.333 7.776 ;
     RECT  43.333 2.572 45.539 7.776 ;
     RECT  45.539 2.572 46.835 7.648 ;
     RECT  46.835 2.572 46.883 4.064 ;
     RECT  46.883 2.572 47.269 3.552 ;
     RECT  47.269 1.728 48.037 3.552 ;
     RECT  48.037 1.344 48.373 3.552 ;
     RECT  48.373 1.344 49.379 3.872 ;
     RECT  49.379 1.664 49.763 3.872 ;
     RECT  46.835 5.952 50.053 7.648 ;
     RECT  50.053 5.952 50.677 7.712 ;
     RECT  50.101 0.256 50.771 0.288 ;
     RECT  49.763 1.664 50.819 3.436 ;
     RECT  50.819 2.24 50.867 3.436 ;
     RECT  50.867 2.572 51.205 3.436 ;
     RECT  51.205 2.572 51.253 3.552 ;
     RECT  50.677 5.248 51.733 7.712 ;
     RECT  51.253 2.572 51.971 3.616 ;
     RECT  51.971 2.572 52.019 3.552 ;
     RECT  51.733 5.248 52.835 7.84 ;
     RECT  52.019 2.572 52.981 3.436 ;
     RECT  52.981 2.112 54.085 3.436 ;
     RECT  52.835 6.528 54.179 7.84 ;
     RECT  54.085 2.112 55.237 4.96 ;
     RECT  54.179 6.528 55.237 7.392 ;
     RECT  55.237 2.112 55.331 7.392 ;
     RECT  55.331 2.112 55.427 6.88 ;
     RECT  41.315 9.228 56.389 10.092 ;
     RECT  55.427 2.24 56.483 6.88 ;
     RECT  56.483 2.24 57.877 6.56 ;
     RECT  56.725 7.872 58.739 7.904 ;
     RECT  56.389 9.228 58.883 10.336 ;
     RECT  57.877 1.92 58.885 6.56 ;
     RECT  58.885 1.92 59.411 7.84 ;
     RECT  59.411 2.572 60.227 7.84 ;
     RECT  60.227 2.572 60.949 7.392 ;
     RECT  60.949 1.088 61.043 7.392 ;
     RECT  61.043 1.088 61.619 6.56 ;
     RECT  61.619 1.088 61.667 1.12 ;
     RECT  58.883 9.228 62.101 10.092 ;
     RECT  61.619 2.572 63.155 6.56 ;
     RECT  63.155 2.572 63.205 4.832 ;
     RECT  63.205 2.24 64.451 4.832 ;
     RECT  64.451 2.572 65.509 4.832 ;
     RECT  63.155 6.528 65.509 6.56 ;
     RECT  62.101 9.228 65.557 10.336 ;
     RECT  65.509 2.572 66.661 6.56 ;
     RECT  65.557 9.024 67.093 10.336 ;
     RECT  66.661 2.572 68.245 7.136 ;
     RECT  68.245 2.112 69.011 7.136 ;
     RECT  69.011 2.572 69.827 7.136 ;
     RECT  67.093 8.96 69.971 10.336 ;
     RECT  69.827 2.572 70.837 7.072 ;
     RECT  70.837 1.28 70.883 7.072 ;
     RECT  69.971 8.96 71.699 10.092 ;
     RECT  70.883 1.28 71.843 6.816 ;
     RECT  71.699 9.228 71.845 10.092 ;
     RECT  71.843 2.572 73.811 6.816 ;
     RECT  71.845 9.228 74.147 10.528 ;
     RECT  73.811 2.572 74.533 4.704 ;
     RECT  74.533 1.664 74.629 4.704 ;
     RECT  74.629 1.344 75.011 4.704 ;
     RECT  75.011 1.344 75.299 4 ;
     RECT  75.299 1.664 75.347 4 ;
     RECT  74.147 9.228 76.403 10.336 ;
     RECT  75.347 2.572 76.837 4 ;
     RECT  73.811 6.208 76.885 6.816 ;
     RECT  76.837 2.572 77.603 4.576 ;
     RECT  77.603 2.572 77.893 4.064 ;
     RECT  77.893 2.432 78.373 4.064 ;
     RECT  76.885 6.208 78.613 7.136 ;
     RECT  78.373 1.664 78.901 4.064 ;
     RECT  78.613 5.76 78.901 7.136 ;
     RECT  76.403 9.228 79.189 10.092 ;
     RECT  78.901 1.664 79.283 7.136 ;
     RECT  79.283 2.304 80.869 7.136 ;
     RECT  81.013 11.456 81.443 11.488 ;
     RECT  80.869 1.664 81.731 7.136 ;
     RECT  81.731 2.432 82.115 7.136 ;
     RECT  82.115 4.928 82.403 6.24 ;
     RECT  82.115 2.432 84.901 3.436 ;
     RECT  82.403 4.928 84.901 5.472 ;
     RECT  79.189 8.448 85.045 10.092 ;
     RECT  85.045 8.448 85.477 10.208 ;
     RECT  84.901 2.432 86.339 5.472 ;
     RECT  86.339 2.432 86.387 3.616 ;
     RECT  86.387 2.432 86.435 3.552 ;
     RECT  86.339 4.928 86.485 5.472 ;
     RECT  85.477 7.424 86.485 10.208 ;
     RECT  86.485 4.928 86.531 10.208 ;
     RECT  86.435 2.432 87.157 3.436 ;
     RECT  87.157 1.536 87.733 3.436 ;
     RECT  87.733 1.088 88.165 3.436 ;
     RECT  86.531 4.928 88.165 6.56 ;
     RECT  86.531 8.448 88.643 10.208 ;
     RECT  88.165 1.088 88.691 6.56 ;
     RECT  88.691 2.304 90.899 6.56 ;
     RECT  90.899 2.304 91.477 3.552 ;
     RECT  90.899 5.44 91.571 6.56 ;
     RECT  91.477 1.088 91.859 3.552 ;
     RECT  91.859 1.088 92.483 3.436 ;
     RECT  92.483 1.664 92.675 3.436 ;
     RECT  91.571 5.632 93.061 6.56 ;
     RECT  93.061 5.12 94.115 6.56 ;
     RECT  92.675 2.572 94.549 3.436 ;
     RECT  88.643 9.228 94.549 10.208 ;
     RECT  94.115 6.528 94.645 6.56 ;
     RECT  94.549 7.936 94.645 10.528 ;
     RECT  94.645 6.528 94.835 10.528 ;
     RECT  94.115 5.12 94.931 5.152 ;
     RECT  94.835 6.592 94.931 10.528 ;
     RECT  94.549 2.572 95.701 3.552 ;
     RECT  95.701 2.368 96.181 3.552 ;
     RECT  94.931 6.592 96.181 6.624 ;
     RECT  96.181 2.368 96.229 4.32 ;
     RECT  94.931 7.936 96.467 10.528 ;
     RECT  96.229 2.24 96.757 4.32 ;
     RECT  96.467 9.228 96.947 10.528 ;
     RECT  96.757 1.536 97.187 4.32 ;
     RECT  97.187 1.536 97.859 3.808 ;
     RECT  97.859 2.24 98.003 3.808 ;
     RECT  98.003 2.304 98.723 3.808 ;
     RECT  98.723 2.304 98.915 3.68 ;
     RECT  98.915 2.432 100.261 3.68 ;
     RECT  100.261 2.432 100.643 4.064 ;
     RECT  96.181 6.016 101.029 6.624 ;
     RECT  100.643 2.572 101.845 4.064 ;
     RECT  101.029 6.016 102.227 7.904 ;
     RECT  96.947 9.228 102.227 10.336 ;
     RECT  102.227 6.592 103.283 7.904 ;
     RECT  101.845 2.572 103.763 4.448 ;
     RECT  103.763 2.572 104.245 3.436 ;
     RECT  104.245 0.192 104.915 0.224 ;
     RECT  104.245 1.664 104.915 3.436 ;
     RECT  104.915 2.572 105.84 3.436 ;
     RECT  102.227 9.228 105.84 10.092 ;
  END
END ot_attn_bank_sn544
END LIBRARY
